VERSION 5.8 ;
BUSBITCHARS "[]" ;
DIVIDERCHAR "/" ;
UNITS
    DATABASE MICRONS 1000 ;
END UNITS

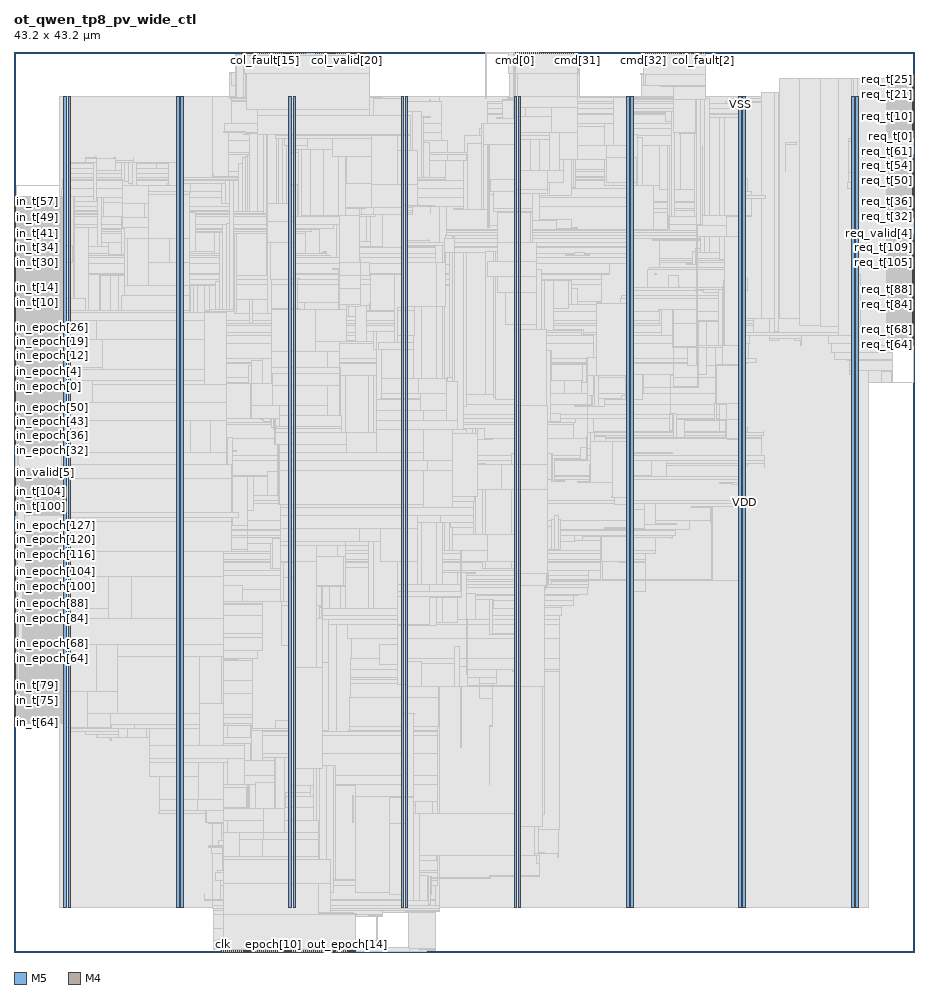
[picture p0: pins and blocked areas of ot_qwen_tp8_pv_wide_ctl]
MACRO ot_qwen_tp8_pv_wide_ctl
  FOREIGN ot_qwen_tp8_pv_wide_ctl 0 0 ;
  CLASS BLOCK ;
  SIZE 43.2 BY 43.2 ;
  PIN busy
    DIRECTION OUTPUT ;
    USE SIGNAL ;
    PORT
      LAYER M5 ;
        RECT  9.936 0 9.96 0.084 ;
    END
  END busy
  PIN clk
    DIRECTION INPUT ;
    USE SIGNAL ;
    PORT
      LAYER M5 ;
        RECT  10.032 0 10.056 0.084 ;
    END
  END clk
  PIN cmd[0]
    DIRECTION OUTPUT ;
    USE SIGNAL ;
    PORT
      LAYER M5 ;
        RECT  24.048 43.116 24.072 43.2 ;
    END
  END cmd[0]
  PIN cmd[10]
    DIRECTION OUTPUT ;
    USE SIGNAL ;
    PORT
      LAYER M5 ;
        RECT  25.008 43.116 25.032 43.2 ;
    END
  END cmd[10]
  PIN cmd[11]
    DIRECTION OUTPUT ;
    USE SIGNAL ;
    PORT
      LAYER M5 ;
        RECT  25.104 43.116 25.128 43.2 ;
    END
  END cmd[11]
  PIN cmd[12]
    DIRECTION OUTPUT ;
    USE SIGNAL ;
    PORT
      LAYER M5 ;
        RECT  25.2 43.116 25.224 43.2 ;
    END
  END cmd[12]
  PIN cmd[13]
    DIRECTION OUTPUT ;
    USE SIGNAL ;
    PORT
      LAYER M5 ;
        RECT  25.296 43.116 25.32 43.2 ;
    END
  END cmd[13]
  PIN cmd[14]
    DIRECTION OUTPUT ;
    USE SIGNAL ;
    PORT
      LAYER M5 ;
        RECT  25.392 43.116 25.416 43.2 ;
    END
  END cmd[14]
  PIN cmd[15]
    DIRECTION OUTPUT ;
    USE SIGNAL ;
    PORT
      LAYER M5 ;
        RECT  25.488 43.116 25.512 43.2 ;
    END
  END cmd[15]
  PIN cmd[16]
    DIRECTION OUTPUT ;
    USE SIGNAL ;
    PORT
      LAYER M5 ;
        RECT  25.584 43.116 25.608 43.2 ;
    END
  END cmd[16]
  PIN cmd[17]
    DIRECTION OUTPUT ;
    USE SIGNAL ;
    PORT
      LAYER M5 ;
        RECT  25.68 43.116 25.704 43.2 ;
    END
  END cmd[17]
  PIN cmd[18]
    DIRECTION OUTPUT ;
    USE SIGNAL ;
    PORT
      LAYER M5 ;
        RECT  25.776 43.116 25.8 43.2 ;
    END
  END cmd[18]
  PIN cmd[19]
    DIRECTION OUTPUT ;
    USE SIGNAL ;
    PORT
      LAYER M5 ;
        RECT  25.872 43.116 25.896 43.2 ;
    END
  END cmd[19]
  PIN cmd[1]
    DIRECTION OUTPUT ;
    USE SIGNAL ;
    PORT
      LAYER M5 ;
        RECT  24.144 43.116 24.168 43.2 ;
    END
  END cmd[1]
  PIN cmd[20]
    DIRECTION OUTPUT ;
    USE SIGNAL ;
    PORT
      LAYER M5 ;
        RECT  25.968 43.116 25.992 43.2 ;
    END
  END cmd[20]
  PIN cmd[21]
    DIRECTION OUTPUT ;
    USE SIGNAL ;
    PORT
      LAYER M5 ;
        RECT  26.064 43.116 26.088 43.2 ;
    END
  END cmd[21]
  PIN cmd[22]
    DIRECTION OUTPUT ;
    USE SIGNAL ;
    PORT
      LAYER M5 ;
        RECT  26.16 43.116 26.184 43.2 ;
    END
  END cmd[22]
  PIN cmd[23]
    DIRECTION OUTPUT ;
    USE SIGNAL ;
    PORT
      LAYER M5 ;
        RECT  26.256 43.116 26.28 43.2 ;
    END
  END cmd[23]
  PIN cmd[24]
    DIRECTION OUTPUT ;
    USE SIGNAL ;
    PORT
      LAYER M5 ;
        RECT  26.352 43.116 26.376 43.2 ;
    END
  END cmd[24]
  PIN cmd[25]
    DIRECTION OUTPUT ;
    USE SIGNAL ;
    PORT
      LAYER M5 ;
        RECT  26.448 43.116 26.472 43.2 ;
    END
  END cmd[25]
  PIN cmd[26]
    DIRECTION OUTPUT ;
    USE SIGNAL ;
    PORT
      LAYER M5 ;
        RECT  26.544 43.116 26.568 43.2 ;
    END
  END cmd[26]
  PIN cmd[27]
    DIRECTION OUTPUT ;
    USE SIGNAL ;
    PORT
      LAYER M5 ;
        RECT  26.64 43.116 26.664 43.2 ;
    END
  END cmd[27]
  PIN cmd[28]
    DIRECTION OUTPUT ;
    USE SIGNAL ;
    PORT
      LAYER M5 ;
        RECT  26.736 43.116 26.76 43.2 ;
    END
  END cmd[28]
  PIN cmd[29]
    DIRECTION OUTPUT ;
    USE SIGNAL ;
    PORT
      LAYER M5 ;
        RECT  26.832 43.116 26.856 43.2 ;
    END
  END cmd[29]
  PIN cmd[2]
    DIRECTION OUTPUT ;
    USE SIGNAL ;
    PORT
      LAYER M5 ;
        RECT  24.24 43.116 24.264 43.2 ;
    END
  END cmd[2]
  PIN cmd[30]
    DIRECTION OUTPUT ;
    USE SIGNAL ;
    PORT
      LAYER M5 ;
        RECT  26.928 43.116 26.952 43.2 ;
    END
  END cmd[30]
  PIN cmd[31]
    DIRECTION OUTPUT ;
    USE SIGNAL ;
    PORT
      LAYER M5 ;
        RECT  27.024 43.116 27.048 43.2 ;
    END
  END cmd[31]
  PIN cmd[32]
    DIRECTION OUTPUT ;
    USE SIGNAL ;
    PORT
      LAYER M5 ;
        RECT  30.192 43.116 30.216 43.2 ;
    END
  END cmd[32]
  PIN cmd[33]
    DIRECTION OUTPUT ;
    USE SIGNAL ;
    PORT
      LAYER M5 ;
        RECT  30.288 43.116 30.312 43.2 ;
    END
  END cmd[33]
  PIN cmd[34]
    DIRECTION OUTPUT ;
    USE SIGNAL ;
    PORT
      LAYER M5 ;
        RECT  30.384 43.116 30.408 43.2 ;
    END
  END cmd[34]
  PIN cmd[35]
    DIRECTION OUTPUT ;
    USE SIGNAL ;
    PORT
      LAYER M5 ;
        RECT  30.48 43.116 30.504 43.2 ;
    END
  END cmd[35]
  PIN cmd[36]
    DIRECTION OUTPUT ;
    USE SIGNAL ;
    PORT
      LAYER M5 ;
        RECT  30.576 43.116 30.6 43.2 ;
    END
  END cmd[36]
  PIN cmd[37]
    DIRECTION OUTPUT ;
    USE SIGNAL ;
    PORT
      LAYER M5 ;
        RECT  30.672 43.116 30.696 43.2 ;
    END
  END cmd[37]
  PIN cmd[38]
    DIRECTION OUTPUT ;
    USE SIGNAL ;
    PORT
      LAYER M5 ;
        RECT  30.768 43.116 30.792 43.2 ;
    END
  END cmd[38]
  PIN cmd[39]
    DIRECTION OUTPUT ;
    USE SIGNAL ;
    PORT
      LAYER M5 ;
        RECT  30.864 43.116 30.888 43.2 ;
    END
  END cmd[39]
  PIN cmd[3]
    DIRECTION OUTPUT ;
    USE SIGNAL ;
    PORT
      LAYER M5 ;
        RECT  24.336 43.116 24.36 43.2 ;
    END
  END cmd[3]
  PIN cmd[40]
    DIRECTION OUTPUT ;
    USE SIGNAL ;
    PORT
      LAYER M5 ;
        RECT  30.96 43.116 30.984 43.2 ;
    END
  END cmd[40]
  PIN cmd[41]
    DIRECTION OUTPUT ;
    USE SIGNAL ;
    PORT
      LAYER M5 ;
        RECT  31.056 43.116 31.08 43.2 ;
    END
  END cmd[41]
  PIN cmd[42]
    DIRECTION OUTPUT ;
    USE SIGNAL ;
    PORT
      LAYER M5 ;
        RECT  31.152 43.116 31.176 43.2 ;
    END
  END cmd[42]
  PIN cmd[43]
    DIRECTION OUTPUT ;
    USE SIGNAL ;
    PORT
      LAYER M5 ;
        RECT  31.248 43.116 31.272 43.2 ;
    END
  END cmd[43]
  PIN cmd[44]
    DIRECTION OUTPUT ;
    USE SIGNAL ;
    PORT
      LAYER M5 ;
        RECT  31.344 43.116 31.368 43.2 ;
    END
  END cmd[44]
  PIN cmd[45]
    DIRECTION OUTPUT ;
    USE SIGNAL ;
    PORT
      LAYER M5 ;
        RECT  31.44 43.116 31.464 43.2 ;
    END
  END cmd[45]
  PIN cmd[46]
    DIRECTION OUTPUT ;
    USE SIGNAL ;
    PORT
      LAYER M5 ;
        RECT  31.536 43.116 31.56 43.2 ;
    END
  END cmd[46]
  PIN cmd[47]
    DIRECTION OUTPUT ;
    USE SIGNAL ;
    PORT
      LAYER M5 ;
        RECT  31.632 43.116 31.656 43.2 ;
    END
  END cmd[47]
  PIN cmd[48]
    DIRECTION OUTPUT ;
    USE SIGNAL ;
    PORT
      LAYER M5 ;
        RECT  31.728 43.116 31.752 43.2 ;
    END
  END cmd[48]
  PIN cmd[49]
    DIRECTION OUTPUT ;
    USE SIGNAL ;
    PORT
      LAYER M5 ;
        RECT  31.824 43.116 31.848 43.2 ;
    END
  END cmd[49]
  PIN cmd[4]
    DIRECTION OUTPUT ;
    USE SIGNAL ;
    PORT
      LAYER M5 ;
        RECT  24.432 43.116 24.456 43.2 ;
    END
  END cmd[4]
  PIN cmd[50]
    DIRECTION OUTPUT ;
    USE SIGNAL ;
    PORT
      LAYER M5 ;
        RECT  31.92 43.116 31.944 43.2 ;
    END
  END cmd[50]
  PIN cmd[51]
    DIRECTION OUTPUT ;
    USE SIGNAL ;
    PORT
      LAYER M5 ;
        RECT  32.016 43.116 32.04 43.2 ;
    END
  END cmd[51]
  PIN cmd[52]
    DIRECTION OUTPUT ;
    USE SIGNAL ;
    PORT
      LAYER M5 ;
        RECT  32.112 43.116 32.136 43.2 ;
    END
  END cmd[52]
  PIN cmd[53]
    DIRECTION OUTPUT ;
    USE SIGNAL ;
    PORT
      LAYER M5 ;
        RECT  32.208 43.116 32.232 43.2 ;
    END
  END cmd[53]
  PIN cmd[54]
    DIRECTION OUTPUT ;
    USE SIGNAL ;
    PORT
      LAYER M5 ;
        RECT  32.304 43.116 32.328 43.2 ;
    END
  END cmd[54]
  PIN cmd[55]
    DIRECTION OUTPUT ;
    USE SIGNAL ;
    PORT
      LAYER M5 ;
        RECT  32.4 43.116 32.424 43.2 ;
    END
  END cmd[55]
  PIN cmd[56]
    DIRECTION OUTPUT ;
    USE SIGNAL ;
    PORT
      LAYER M5 ;
        RECT  32.496 43.116 32.52 43.2 ;
    END
  END cmd[56]
  PIN cmd[57]
    DIRECTION OUTPUT ;
    USE SIGNAL ;
    PORT
      LAYER M5 ;
        RECT  32.592 43.116 32.616 43.2 ;
    END
  END cmd[57]
  PIN cmd[58]
    DIRECTION OUTPUT ;
    USE SIGNAL ;
    PORT
      LAYER M5 ;
        RECT  32.688 43.116 32.712 43.2 ;
    END
  END cmd[58]
  PIN cmd[59]
    DIRECTION OUTPUT ;
    USE SIGNAL ;
    PORT
      LAYER M5 ;
        RECT  32.784 43.116 32.808 43.2 ;
    END
  END cmd[59]
  PIN cmd[5]
    DIRECTION OUTPUT ;
    USE SIGNAL ;
    PORT
      LAYER M5 ;
        RECT  24.528 43.116 24.552 43.2 ;
    END
  END cmd[5]
  PIN cmd[6]
    DIRECTION OUTPUT ;
    USE SIGNAL ;
    PORT
      LAYER M5 ;
        RECT  24.624 43.116 24.648 43.2 ;
    END
  END cmd[6]
  PIN cmd[7]
    DIRECTION OUTPUT ;
    USE SIGNAL ;
    PORT
      LAYER M5 ;
        RECT  24.72 43.116 24.744 43.2 ;
    END
  END cmd[7]
  PIN cmd[8]
    DIRECTION OUTPUT ;
    USE SIGNAL ;
    PORT
      LAYER M5 ;
        RECT  24.816 43.116 24.84 43.2 ;
    END
  END cmd[8]
  PIN cmd[9]
    DIRECTION OUTPUT ;
    USE SIGNAL ;
    PORT
      LAYER M5 ;
        RECT  24.912 43.116 24.936 43.2 ;
    END
  END cmd[9]
  PIN col_fault[0]
    DIRECTION INPUT ;
    USE SIGNAL ;
    PORT
      LAYER M5 ;
        RECT  32.88 43.116 32.904 43.2 ;
    END
  END col_fault[0]
  PIN col_fault[10]
    DIRECTION INPUT ;
    USE SIGNAL ;
    PORT
      LAYER M5 ;
        RECT  11.568 43.116 11.592 43.2 ;
    END
  END col_fault[10]
  PIN col_fault[11]
    DIRECTION INPUT ;
    USE SIGNAL ;
    PORT
      LAYER M5 ;
        RECT  11.664 43.116 11.688 43.2 ;
    END
  END col_fault[11]
  PIN col_fault[12]
    DIRECTION INPUT ;
    USE SIGNAL ;
    PORT
      LAYER M5 ;
        RECT  11.76 43.116 11.784 43.2 ;
    END
  END col_fault[12]
  PIN col_fault[13]
    DIRECTION INPUT ;
    USE SIGNAL ;
    PORT
      LAYER M5 ;
        RECT  11.856 43.116 11.88 43.2 ;
    END
  END col_fault[13]
  PIN col_fault[14]
    DIRECTION INPUT ;
    USE SIGNAL ;
    PORT
      LAYER M5 ;
        RECT  11.952 43.116 11.976 43.2 ;
    END
  END col_fault[14]
  PIN col_fault[15]
    DIRECTION INPUT ;
    USE SIGNAL ;
    PORT
      LAYER M5 ;
        RECT  12.048 43.116 12.072 43.2 ;
    END
  END col_fault[15]
  PIN col_fault[16]
    DIRECTION INPUT ;
    USE SIGNAL ;
    PORT
      LAYER M5 ;
        RECT  12.144 43.116 12.168 43.2 ;
    END
  END col_fault[16]
  PIN col_fault[17]
    DIRECTION INPUT ;
    USE SIGNAL ;
    PORT
      LAYER M5 ;
        RECT  12.24 43.116 12.264 43.2 ;
    END
  END col_fault[17]
  PIN col_fault[18]
    DIRECTION INPUT ;
    USE SIGNAL ;
    PORT
      LAYER M5 ;
        RECT  12.336 43.116 12.36 43.2 ;
    END
  END col_fault[18]
  PIN col_fault[19]
    DIRECTION INPUT ;
    USE SIGNAL ;
    PORT
      LAYER M5 ;
        RECT  12.432 43.116 12.456 43.2 ;
    END
  END col_fault[19]
  PIN col_fault[1]
    DIRECTION INPUT ;
    USE SIGNAL ;
    PORT
      LAYER M5 ;
        RECT  32.976 43.116 33 43.2 ;
    END
  END col_fault[1]
  PIN col_fault[20]
    DIRECTION INPUT ;
    USE SIGNAL ;
    PORT
      LAYER M5 ;
        RECT  12.528 43.116 12.552 43.2 ;
    END
  END col_fault[20]
  PIN col_fault[21]
    DIRECTION INPUT ;
    USE SIGNAL ;
    PORT
      LAYER M5 ;
        RECT  12.624 43.116 12.648 43.2 ;
    END
  END col_fault[21]
  PIN col_fault[22]
    DIRECTION INPUT ;
    USE SIGNAL ;
    PORT
      LAYER M5 ;
        RECT  12.72 43.116 12.744 43.2 ;
    END
  END col_fault[22]
  PIN col_fault[23]
    DIRECTION INPUT ;
    USE SIGNAL ;
    PORT
      LAYER M5 ;
        RECT  12.816 43.116 12.84 43.2 ;
    END
  END col_fault[23]
  PIN col_fault[24]
    DIRECTION INPUT ;
    USE SIGNAL ;
    PORT
      LAYER M5 ;
        RECT  12.912 43.116 12.936 43.2 ;
    END
  END col_fault[24]
  PIN col_fault[25]
    DIRECTION INPUT ;
    USE SIGNAL ;
    PORT
      LAYER M5 ;
        RECT  13.008 43.116 13.032 43.2 ;
    END
  END col_fault[25]
  PIN col_fault[26]
    DIRECTION INPUT ;
    USE SIGNAL ;
    PORT
      LAYER M5 ;
        RECT  13.104 43.116 13.128 43.2 ;
    END
  END col_fault[26]
  PIN col_fault[27]
    DIRECTION INPUT ;
    USE SIGNAL ;
    PORT
      LAYER M5 ;
        RECT  13.2 43.116 13.224 43.2 ;
    END
  END col_fault[27]
  PIN col_fault[28]
    DIRECTION INPUT ;
    USE SIGNAL ;
    PORT
      LAYER M5 ;
        RECT  13.296 43.116 13.32 43.2 ;
    END
  END col_fault[28]
  PIN col_fault[29]
    DIRECTION INPUT ;
    USE SIGNAL ;
    PORT
      LAYER M5 ;
        RECT  13.392 43.116 13.416 43.2 ;
    END
  END col_fault[29]
  PIN col_fault[2]
    DIRECTION INPUT ;
    USE SIGNAL ;
    PORT
      LAYER M5 ;
        RECT  33.072 43.116 33.096 43.2 ;
    END
  END col_fault[2]
  PIN col_fault[30]
    DIRECTION INPUT ;
    USE SIGNAL ;
    PORT
      LAYER M5 ;
        RECT  13.488 43.116 13.512 43.2 ;
    END
  END col_fault[30]
  PIN col_fault[31]
    DIRECTION INPUT ;
    USE SIGNAL ;
    PORT
      LAYER M5 ;
        RECT  13.584 43.116 13.608 43.2 ;
    END
  END col_fault[31]
  PIN col_fault[3]
    DIRECTION INPUT ;
    USE SIGNAL ;
    PORT
      LAYER M5 ;
        RECT  33.168 43.116 33.192 43.2 ;
    END
  END col_fault[3]
  PIN col_fault[4]
    DIRECTION INPUT ;
    USE SIGNAL ;
    PORT
      LAYER M5 ;
        RECT  10.992 43.116 11.016 43.2 ;
    END
  END col_fault[4]
  PIN col_fault[5]
    DIRECTION INPUT ;
    USE SIGNAL ;
    PORT
      LAYER M5 ;
        RECT  11.088 43.116 11.112 43.2 ;
    END
  END col_fault[5]
  PIN col_fault[6]
    DIRECTION INPUT ;
    USE SIGNAL ;
    PORT
      LAYER M5 ;
        RECT  11.184 43.116 11.208 43.2 ;
    END
  END col_fault[6]
  PIN col_fault[7]
    DIRECTION INPUT ;
    USE SIGNAL ;
    PORT
      LAYER M5 ;
        RECT  11.28 43.116 11.304 43.2 ;
    END
  END col_fault[7]
  PIN col_fault[8]
    DIRECTION INPUT ;
    USE SIGNAL ;
    PORT
      LAYER M5 ;
        RECT  11.376 43.116 11.4 43.2 ;
    END
  END col_fault[8]
  PIN col_fault[9]
    DIRECTION INPUT ;
    USE SIGNAL ;
    PORT
      LAYER M5 ;
        RECT  11.472 43.116 11.496 43.2 ;
    END
  END col_fault[9]
  PIN col_valid[0]
    DIRECTION INPUT ;
    USE SIGNAL ;
    PORT
      LAYER M5 ;
        RECT  13.68 43.116 13.704 43.2 ;
    END
  END col_valid[0]
  PIN col_valid[10]
    DIRECTION INPUT ;
    USE SIGNAL ;
    PORT
      LAYER M5 ;
        RECT  15.024 43.116 15.048 43.2 ;
    END
  END col_valid[10]
  PIN col_valid[11]
    DIRECTION INPUT ;
    USE SIGNAL ;
    PORT
      LAYER M5 ;
        RECT  15.12 43.116 15.144 43.2 ;
    END
  END col_valid[11]
  PIN col_valid[12]
    DIRECTION INPUT ;
    USE SIGNAL ;
    PORT
      LAYER M5 ;
        RECT  15.216 43.116 15.24 43.2 ;
    END
  END col_valid[12]
  PIN col_valid[13]
    DIRECTION INPUT ;
    USE SIGNAL ;
    PORT
      LAYER M5 ;
        RECT  15.312 43.116 15.336 43.2 ;
    END
  END col_valid[13]
  PIN col_valid[14]
    DIRECTION INPUT ;
    USE SIGNAL ;
    PORT
      LAYER M5 ;
        RECT  15.408 43.116 15.432 43.2 ;
    END
  END col_valid[14]
  PIN col_valid[15]
    DIRECTION INPUT ;
    USE SIGNAL ;
    PORT
      LAYER M5 ;
        RECT  15.504 43.116 15.528 43.2 ;
    END
  END col_valid[15]
  PIN col_valid[16]
    DIRECTION INPUT ;
    USE SIGNAL ;
    PORT
      LAYER M5 ;
        RECT  15.6 43.116 15.624 43.2 ;
    END
  END col_valid[16]
  PIN col_valid[17]
    DIRECTION INPUT ;
    USE SIGNAL ;
    PORT
      LAYER M5 ;
        RECT  15.696 43.116 15.72 43.2 ;
    END
  END col_valid[17]
  PIN col_valid[18]
    DIRECTION INPUT ;
    USE SIGNAL ;
    PORT
      LAYER M5 ;
        RECT  15.792 43.116 15.816 43.2 ;
    END
  END col_valid[18]
  PIN col_valid[19]
    DIRECTION INPUT ;
    USE SIGNAL ;
    PORT
      LAYER M5 ;
        RECT  15.888 43.116 15.912 43.2 ;
    END
  END col_valid[19]
  PIN col_valid[1]
    DIRECTION INPUT ;
    USE SIGNAL ;
    PORT
      LAYER M5 ;
        RECT  13.776 43.116 13.8 43.2 ;
    END
  END col_valid[1]
  PIN col_valid[20]
    DIRECTION INPUT ;
    USE SIGNAL ;
    PORT
      LAYER M5 ;
        RECT  15.984 43.116 16.008 43.2 ;
    END
  END col_valid[20]
  PIN col_valid[21]
    DIRECTION INPUT ;
    USE SIGNAL ;
    PORT
      LAYER M5 ;
        RECT  16.08 43.116 16.104 43.2 ;
    END
  END col_valid[21]
  PIN col_valid[22]
    DIRECTION INPUT ;
    USE SIGNAL ;
    PORT
      LAYER M5 ;
        RECT  16.176 43.116 16.2 43.2 ;
    END
  END col_valid[22]
  PIN col_valid[23]
    DIRECTION INPUT ;
    USE SIGNAL ;
    PORT
      LAYER M5 ;
        RECT  16.272 43.116 16.296 43.2 ;
    END
  END col_valid[23]
  PIN col_valid[24]
    DIRECTION INPUT ;
    USE SIGNAL ;
    PORT
      LAYER M5 ;
        RECT  16.368 43.116 16.392 43.2 ;
    END
  END col_valid[24]
  PIN col_valid[25]
    DIRECTION INPUT ;
    USE SIGNAL ;
    PORT
      LAYER M5 ;
        RECT  16.464 43.116 16.488 43.2 ;
    END
  END col_valid[25]
  PIN col_valid[26]
    DIRECTION INPUT ;
    USE SIGNAL ;
    PORT
      LAYER M5 ;
        RECT  16.56 43.116 16.584 43.2 ;
    END
  END col_valid[26]
  PIN col_valid[27]
    DIRECTION INPUT ;
    USE SIGNAL ;
    PORT
      LAYER M5 ;
        RECT  16.656 43.116 16.68 43.2 ;
    END
  END col_valid[27]
  PIN col_valid[28]
    DIRECTION INPUT ;
    USE SIGNAL ;
    PORT
      LAYER M5 ;
        RECT  16.752 43.116 16.776 43.2 ;
    END
  END col_valid[28]
  PIN col_valid[29]
    DIRECTION INPUT ;
    USE SIGNAL ;
    PORT
      LAYER M5 ;
        RECT  16.848 43.116 16.872 43.2 ;
    END
  END col_valid[29]
  PIN col_valid[2]
    DIRECTION INPUT ;
    USE SIGNAL ;
    PORT
      LAYER M5 ;
        RECT  13.872 43.116 13.896 43.2 ;
    END
  END col_valid[2]
  PIN col_valid[30]
    DIRECTION INPUT ;
    USE SIGNAL ;
    PORT
      LAYER M5 ;
        RECT  16.944 43.116 16.968 43.2 ;
    END
  END col_valid[30]
  PIN col_valid[31]
    DIRECTION INPUT ;
    USE SIGNAL ;
    PORT
      LAYER M5 ;
        RECT  17.04 43.116 17.064 43.2 ;
    END
  END col_valid[31]
  PIN col_valid[3]
    DIRECTION INPUT ;
    USE SIGNAL ;
    PORT
      LAYER M5 ;
        RECT  13.968 43.116 13.992 43.2 ;
    END
  END col_valid[3]
  PIN col_valid[4]
    DIRECTION INPUT ;
    USE SIGNAL ;
    PORT
      LAYER M5 ;
        RECT  14.448 43.116 14.472 43.2 ;
    END
  END col_valid[4]
  PIN col_valid[5]
    DIRECTION INPUT ;
    USE SIGNAL ;
    PORT
      LAYER M5 ;
        RECT  14.544 43.116 14.568 43.2 ;
    END
  END col_valid[5]
  PIN col_valid[6]
    DIRECTION INPUT ;
    USE SIGNAL ;
    PORT
      LAYER M5 ;
        RECT  14.64 43.116 14.664 43.2 ;
    END
  END col_valid[6]
  PIN col_valid[7]
    DIRECTION INPUT ;
    USE SIGNAL ;
    PORT
      LAYER M5 ;
        RECT  14.736 43.116 14.76 43.2 ;
    END
  END col_valid[7]
  PIN col_valid[8]
    DIRECTION INPUT ;
    USE SIGNAL ;
    PORT
      LAYER M5 ;
        RECT  14.832 43.116 14.856 43.2 ;
    END
  END col_valid[8]
  PIN col_valid[9]
    DIRECTION INPUT ;
    USE SIGNAL ;
    PORT
      LAYER M5 ;
        RECT  14.928 43.116 14.952 43.2 ;
    END
  END col_valid[9]
  PIN context_len[0]
    DIRECTION INPUT ;
    USE SIGNAL ;
    PORT
      LAYER M5 ;
        RECT  10.128 0 10.152 0.084 ;
    END
  END context_len[0]
  PIN context_len[10]
    DIRECTION INPUT ;
    USE SIGNAL ;
    PORT
      LAYER M5 ;
        RECT  11.088 0 11.112 0.084 ;
    END
  END context_len[10]
  PIN context_len[11]
    DIRECTION INPUT ;
    USE SIGNAL ;
    PORT
      LAYER M5 ;
        RECT  11.184 0 11.208 0.084 ;
    END
  END context_len[11]
  PIN context_len[12]
    DIRECTION INPUT ;
    USE SIGNAL ;
    PORT
      LAYER M5 ;
        RECT  11.28 0 11.304 0.084 ;
    END
  END context_len[12]
  PIN context_len[13]
    DIRECTION INPUT ;
    USE SIGNAL ;
    PORT
      LAYER M5 ;
        RECT  11.376 0 11.4 0.084 ;
    END
  END context_len[13]
  PIN context_len[1]
    DIRECTION INPUT ;
    USE SIGNAL ;
    PORT
      LAYER M5 ;
        RECT  10.224 0 10.248 0.084 ;
    END
  END context_len[1]
  PIN context_len[2]
    DIRECTION INPUT ;
    USE SIGNAL ;
    PORT
      LAYER M5 ;
        RECT  10.32 0 10.344 0.084 ;
    END
  END context_len[2]
  PIN context_len[3]
    DIRECTION INPUT ;
    USE SIGNAL ;
    PORT
      LAYER M5 ;
        RECT  10.416 0 10.44 0.084 ;
    END
  END context_len[3]
  PIN context_len[4]
    DIRECTION INPUT ;
    USE SIGNAL ;
    PORT
      LAYER M5 ;
        RECT  10.512 0 10.536 0.084 ;
    END
  END context_len[4]
  PIN context_len[5]
    DIRECTION INPUT ;
    USE SIGNAL ;
    PORT
      LAYER M5 ;
        RECT  10.608 0 10.632 0.084 ;
    END
  END context_len[5]
  PIN context_len[6]
    DIRECTION INPUT ;
    USE SIGNAL ;
    PORT
      LAYER M5 ;
        RECT  10.704 0 10.728 0.084 ;
    END
  END context_len[6]
  PIN context_len[7]
    DIRECTION INPUT ;
    USE SIGNAL ;
    PORT
      LAYER M5 ;
        RECT  10.8 0 10.824 0.084 ;
    END
  END context_len[7]
  PIN context_len[8]
    DIRECTION INPUT ;
    USE SIGNAL ;
    PORT
      LAYER M5 ;
        RECT  10.896 0 10.92 0.084 ;
    END
  END context_len[8]
  PIN context_len[9]
    DIRECTION INPUT ;
    USE SIGNAL ;
    PORT
      LAYER M5 ;
        RECT  10.992 0 11.016 0.084 ;
    END
  END context_len[9]
  PIN epoch[0]
    DIRECTION INPUT ;
    USE SIGNAL ;
    PORT
      LAYER M5 ;
        RECT  11.472 0 11.496 0.084 ;
    END
  END epoch[0]
  PIN epoch[10]
    DIRECTION INPUT ;
    USE SIGNAL ;
    PORT
      LAYER M5 ;
        RECT  12.432 0 12.456 0.084 ;
    END
  END epoch[10]
  PIN epoch[11]
    DIRECTION INPUT ;
    USE SIGNAL ;
    PORT
      LAYER M5 ;
        RECT  12.528 0 12.552 0.084 ;
    END
  END epoch[11]
  PIN epoch[12]
    DIRECTION INPUT ;
    USE SIGNAL ;
    PORT
      LAYER M5 ;
        RECT  12.624 0 12.648 0.084 ;
    END
  END epoch[12]
  PIN epoch[13]
    DIRECTION INPUT ;
    USE SIGNAL ;
    PORT
      LAYER M5 ;
        RECT  12.72 0 12.744 0.084 ;
    END
  END epoch[13]
  PIN epoch[14]
    DIRECTION INPUT ;
    USE SIGNAL ;
    PORT
      LAYER M5 ;
        RECT  12.816 0 12.84 0.084 ;
    END
  END epoch[14]
  PIN epoch[15]
    DIRECTION INPUT ;
    USE SIGNAL ;
    PORT
      LAYER M5 ;
        RECT  12.912 0 12.936 0.084 ;
    END
  END epoch[15]
  PIN epoch[1]
    DIRECTION INPUT ;
    USE SIGNAL ;
    PORT
      LAYER M5 ;
        RECT  11.568 0 11.592 0.084 ;
    END
  END epoch[1]
  PIN epoch[2]
    DIRECTION INPUT ;
    USE SIGNAL ;
    PORT
      LAYER M5 ;
        RECT  11.664 0 11.688 0.084 ;
    END
  END epoch[2]
  PIN epoch[3]
    DIRECTION INPUT ;
    USE SIGNAL ;
    PORT
      LAYER M5 ;
        RECT  11.76 0 11.784 0.084 ;
    END
  END epoch[3]
  PIN epoch[4]
    DIRECTION INPUT ;
    USE SIGNAL ;
    PORT
      LAYER M5 ;
        RECT  11.856 0 11.88 0.084 ;
    END
  END epoch[4]
  PIN epoch[5]
    DIRECTION INPUT ;
    USE SIGNAL ;
    PORT
      LAYER M5 ;
        RECT  11.952 0 11.976 0.084 ;
    END
  END epoch[5]
  PIN epoch[6]
    DIRECTION INPUT ;
    USE SIGNAL ;
    PORT
      LAYER M5 ;
        RECT  12.048 0 12.072 0.084 ;
    END
  END epoch[6]
  PIN epoch[7]
    DIRECTION INPUT ;
    USE SIGNAL ;
    PORT
      LAYER M5 ;
        RECT  12.144 0 12.168 0.084 ;
    END
  END epoch[7]
  PIN epoch[8]
    DIRECTION INPUT ;
    USE SIGNAL ;
    PORT
      LAYER M5 ;
        RECT  12.24 0 12.264 0.084 ;
    END
  END epoch[8]
  PIN epoch[9]
    DIRECTION INPUT ;
    USE SIGNAL ;
    PORT
      LAYER M5 ;
        RECT  12.336 0 12.36 0.084 ;
    END
  END epoch[9]
  PIN fault
    DIRECTION OUTPUT ;
    USE SIGNAL ;
    PORT
      LAYER M5 ;
        RECT  13.008 0 13.032 0.084 ;
    END
  END fault
  PIN in_epoch[0]
    DIRECTION INPUT ;
    USE SIGNAL ;
    PORT
      LAYER M4 ;
        RECT  0 27.12 0.084 27.144 ;
    END
  END in_epoch[0]
  PIN in_epoch[100]
    DIRECTION INPUT ;
    USE SIGNAL ;
    PORT
      LAYER M4 ;
        RECT  0 17.52 0.084 17.544 ;
    END
  END in_epoch[100]
  PIN in_epoch[101]
    DIRECTION INPUT ;
    USE SIGNAL ;
    PORT
      LAYER M4 ;
        RECT  0 17.616 0.084 17.64 ;
    END
  END in_epoch[101]
  PIN in_epoch[102]
    DIRECTION INPUT ;
    USE SIGNAL ;
    PORT
      LAYER M4 ;
        RECT  0 17.712 0.084 17.736 ;
    END
  END in_epoch[102]
  PIN in_epoch[103]
    DIRECTION INPUT ;
    USE SIGNAL ;
    PORT
      LAYER M4 ;
        RECT  0 17.808 0.084 17.832 ;
    END
  END in_epoch[103]
  PIN in_epoch[104]
    DIRECTION INPUT ;
    USE SIGNAL ;
    PORT
      LAYER M4 ;
        RECT  0 17.904 0.084 17.928 ;
    END
  END in_epoch[104]
  PIN in_epoch[105]
    DIRECTION INPUT ;
    USE SIGNAL ;
    PORT
      LAYER M4 ;
        RECT  0 18 0.084 18.024 ;
    END
  END in_epoch[105]
  PIN in_epoch[106]
    DIRECTION INPUT ;
    USE SIGNAL ;
    PORT
      LAYER M4 ;
        RECT  0 18.096 0.084 18.12 ;
    END
  END in_epoch[106]
  PIN in_epoch[107]
    DIRECTION INPUT ;
    USE SIGNAL ;
    PORT
      LAYER M4 ;
        RECT  0 18.192 0.084 18.216 ;
    END
  END in_epoch[107]
  PIN in_epoch[108]
    DIRECTION INPUT ;
    USE SIGNAL ;
    PORT
      LAYER M4 ;
        RECT  0 18.288 0.084 18.312 ;
    END
  END in_epoch[108]
  PIN in_epoch[109]
    DIRECTION INPUT ;
    USE SIGNAL ;
    PORT
      LAYER M4 ;
        RECT  0 18.384 0.084 18.408 ;
    END
  END in_epoch[109]
  PIN in_epoch[10]
    DIRECTION INPUT ;
    USE SIGNAL ;
    PORT
      LAYER M4 ;
        RECT  0 28.08 0.084 28.104 ;
    END
  END in_epoch[10]
  PIN in_epoch[110]
    DIRECTION INPUT ;
    USE SIGNAL ;
    PORT
      LAYER M4 ;
        RECT  0 18.48 0.084 18.504 ;
    END
  END in_epoch[110]
  PIN in_epoch[111]
    DIRECTION INPUT ;
    USE SIGNAL ;
    PORT
      LAYER M4 ;
        RECT  0 18.576 0.084 18.6 ;
    END
  END in_epoch[111]
  PIN in_epoch[112]
    DIRECTION INPUT ;
    USE SIGNAL ;
    PORT
      LAYER M4 ;
        RECT  0 18.672 0.084 18.696 ;
    END
  END in_epoch[112]
  PIN in_epoch[113]
    DIRECTION INPUT ;
    USE SIGNAL ;
    PORT
      LAYER M4 ;
        RECT  0 18.768 0.084 18.792 ;
    END
  END in_epoch[113]
  PIN in_epoch[114]
    DIRECTION INPUT ;
    USE SIGNAL ;
    PORT
      LAYER M4 ;
        RECT  0 18.864 0.084 18.888 ;
    END
  END in_epoch[114]
  PIN in_epoch[115]
    DIRECTION INPUT ;
    USE SIGNAL ;
    PORT
      LAYER M4 ;
        RECT  0 18.96 0.084 18.984 ;
    END
  END in_epoch[115]
  PIN in_epoch[116]
    DIRECTION INPUT ;
    USE SIGNAL ;
    PORT
      LAYER M4 ;
        RECT  0 19.056 0.084 19.08 ;
    END
  END in_epoch[116]
  PIN in_epoch[117]
    DIRECTION INPUT ;
    USE SIGNAL ;
    PORT
      LAYER M4 ;
        RECT  0 19.152 0.084 19.176 ;
    END
  END in_epoch[117]
  PIN in_epoch[118]
    DIRECTION INPUT ;
    USE SIGNAL ;
    PORT
      LAYER M4 ;
        RECT  0 19.248 0.084 19.272 ;
    END
  END in_epoch[118]
  PIN in_epoch[119]
    DIRECTION INPUT ;
    USE SIGNAL ;
    PORT
      LAYER M4 ;
        RECT  0 19.344 0.084 19.368 ;
    END
  END in_epoch[119]
  PIN in_epoch[11]
    DIRECTION INPUT ;
    USE SIGNAL ;
    PORT
      LAYER M4 ;
        RECT  0 28.176 0.084 28.2 ;
    END
  END in_epoch[11]
  PIN in_epoch[120]
    DIRECTION INPUT ;
    USE SIGNAL ;
    PORT
      LAYER M4 ;
        RECT  0 19.44 0.084 19.464 ;
    END
  END in_epoch[120]
  PIN in_epoch[121]
    DIRECTION INPUT ;
    USE SIGNAL ;
    PORT
      LAYER M4 ;
        RECT  0 19.536 0.084 19.56 ;
    END
  END in_epoch[121]
  PIN in_epoch[122]
    DIRECTION INPUT ;
    USE SIGNAL ;
    PORT
      LAYER M4 ;
        RECT  0 19.632 0.084 19.656 ;
    END
  END in_epoch[122]
  PIN in_epoch[123]
    DIRECTION INPUT ;
    USE SIGNAL ;
    PORT
      LAYER M4 ;
        RECT  0 19.728 0.084 19.752 ;
    END
  END in_epoch[123]
  PIN in_epoch[124]
    DIRECTION INPUT ;
    USE SIGNAL ;
    PORT
      LAYER M4 ;
        RECT  0 19.824 0.084 19.848 ;
    END
  END in_epoch[124]
  PIN in_epoch[125]
    DIRECTION INPUT ;
    USE SIGNAL ;
    PORT
      LAYER M4 ;
        RECT  0 19.92 0.084 19.944 ;
    END
  END in_epoch[125]
  PIN in_epoch[126]
    DIRECTION INPUT ;
    USE SIGNAL ;
    PORT
      LAYER M4 ;
        RECT  0 20.016 0.084 20.04 ;
    END
  END in_epoch[126]
  PIN in_epoch[127]
    DIRECTION INPUT ;
    USE SIGNAL ;
    PORT
      LAYER M4 ;
        RECT  0 20.112 0.084 20.136 ;
    END
  END in_epoch[127]
  PIN in_epoch[12]
    DIRECTION INPUT ;
    USE SIGNAL ;
    PORT
      LAYER M4 ;
        RECT  0 28.272 0.084 28.296 ;
    END
  END in_epoch[12]
  PIN in_epoch[13]
    DIRECTION INPUT ;
    USE SIGNAL ;
    PORT
      LAYER M4 ;
        RECT  0 28.368 0.084 28.392 ;
    END
  END in_epoch[13]
  PIN in_epoch[14]
    DIRECTION INPUT ;
    USE SIGNAL ;
    PORT
      LAYER M4 ;
        RECT  0 28.464 0.084 28.488 ;
    END
  END in_epoch[14]
  PIN in_epoch[15]
    DIRECTION INPUT ;
    USE SIGNAL ;
    PORT
      LAYER M4 ;
        RECT  0 28.56 0.084 28.584 ;
    END
  END in_epoch[15]
  PIN in_epoch[16]
    DIRECTION INPUT ;
    USE SIGNAL ;
    PORT
      LAYER M4 ;
        RECT  0 28.656 0.084 28.68 ;
    END
  END in_epoch[16]
  PIN in_epoch[17]
    DIRECTION INPUT ;
    USE SIGNAL ;
    PORT
      LAYER M4 ;
        RECT  0 28.752 0.084 28.776 ;
    END
  END in_epoch[17]
  PIN in_epoch[18]
    DIRECTION INPUT ;
    USE SIGNAL ;
    PORT
      LAYER M4 ;
        RECT  0 28.848 0.084 28.872 ;
    END
  END in_epoch[18]
  PIN in_epoch[19]
    DIRECTION INPUT ;
    USE SIGNAL ;
    PORT
      LAYER M4 ;
        RECT  0 28.944 0.084 28.968 ;
    END
  END in_epoch[19]
  PIN in_epoch[1]
    DIRECTION INPUT ;
    USE SIGNAL ;
    PORT
      LAYER M4 ;
        RECT  0 27.216 0.084 27.24 ;
    END
  END in_epoch[1]
  PIN in_epoch[20]
    DIRECTION INPUT ;
    USE SIGNAL ;
    PORT
      LAYER M4 ;
        RECT  0 29.04 0.084 29.064 ;
    END
  END in_epoch[20]
  PIN in_epoch[21]
    DIRECTION INPUT ;
    USE SIGNAL ;
    PORT
      LAYER M4 ;
        RECT  0 29.136 0.084 29.16 ;
    END
  END in_epoch[21]
  PIN in_epoch[22]
    DIRECTION INPUT ;
    USE SIGNAL ;
    PORT
      LAYER M4 ;
        RECT  0 29.232 0.084 29.256 ;
    END
  END in_epoch[22]
  PIN in_epoch[23]
    DIRECTION INPUT ;
    USE SIGNAL ;
    PORT
      LAYER M4 ;
        RECT  0 29.328 0.084 29.352 ;
    END
  END in_epoch[23]
  PIN in_epoch[24]
    DIRECTION INPUT ;
    USE SIGNAL ;
    PORT
      LAYER M4 ;
        RECT  0 29.424 0.084 29.448 ;
    END
  END in_epoch[24]
  PIN in_epoch[25]
    DIRECTION INPUT ;
    USE SIGNAL ;
    PORT
      LAYER M4 ;
        RECT  0 29.52 0.084 29.544 ;
    END
  END in_epoch[25]
  PIN in_epoch[26]
    DIRECTION INPUT ;
    USE SIGNAL ;
    PORT
      LAYER M4 ;
        RECT  0 29.616 0.084 29.64 ;
    END
  END in_epoch[26]
  PIN in_epoch[27]
    DIRECTION INPUT ;
    USE SIGNAL ;
    PORT
      LAYER M4 ;
        RECT  0 29.712 0.084 29.736 ;
    END
  END in_epoch[27]
  PIN in_epoch[28]
    DIRECTION INPUT ;
    USE SIGNAL ;
    PORT
      LAYER M4 ;
        RECT  0 29.808 0.084 29.832 ;
    END
  END in_epoch[28]
  PIN in_epoch[29]
    DIRECTION INPUT ;
    USE SIGNAL ;
    PORT
      LAYER M4 ;
        RECT  0 29.904 0.084 29.928 ;
    END
  END in_epoch[29]
  PIN in_epoch[2]
    DIRECTION INPUT ;
    USE SIGNAL ;
    PORT
      LAYER M4 ;
        RECT  0 27.312 0.084 27.336 ;
    END
  END in_epoch[2]
  PIN in_epoch[30]
    DIRECTION INPUT ;
    USE SIGNAL ;
    PORT
      LAYER M4 ;
        RECT  0 30 0.084 30.024 ;
    END
  END in_epoch[30]
  PIN in_epoch[31]
    DIRECTION INPUT ;
    USE SIGNAL ;
    PORT
      LAYER M4 ;
        RECT  0 30.096 0.084 30.12 ;
    END
  END in_epoch[31]
  PIN in_epoch[32]
    DIRECTION INPUT ;
    USE SIGNAL ;
    PORT
      LAYER M4 ;
        RECT  0 24.048 0.084 24.072 ;
    END
  END in_epoch[32]
  PIN in_epoch[33]
    DIRECTION INPUT ;
    USE SIGNAL ;
    PORT
      LAYER M4 ;
        RECT  0 24.144 0.084 24.168 ;
    END
  END in_epoch[33]
  PIN in_epoch[34]
    DIRECTION INPUT ;
    USE SIGNAL ;
    PORT
      LAYER M4 ;
        RECT  0 24.24 0.084 24.264 ;
    END
  END in_epoch[34]
  PIN in_epoch[35]
    DIRECTION INPUT ;
    USE SIGNAL ;
    PORT
      LAYER M4 ;
        RECT  0 24.336 0.084 24.36 ;
    END
  END in_epoch[35]
  PIN in_epoch[36]
    DIRECTION INPUT ;
    USE SIGNAL ;
    PORT
      LAYER M4 ;
        RECT  0 24.432 0.084 24.456 ;
    END
  END in_epoch[36]
  PIN in_epoch[37]
    DIRECTION INPUT ;
    USE SIGNAL ;
    PORT
      LAYER M4 ;
        RECT  0 24.528 0.084 24.552 ;
    END
  END in_epoch[37]
  PIN in_epoch[38]
    DIRECTION INPUT ;
    USE SIGNAL ;
    PORT
      LAYER M4 ;
        RECT  0 24.624 0.084 24.648 ;
    END
  END in_epoch[38]
  PIN in_epoch[39]
    DIRECTION INPUT ;
    USE SIGNAL ;
    PORT
      LAYER M4 ;
        RECT  0 24.72 0.084 24.744 ;
    END
  END in_epoch[39]
  PIN in_epoch[3]
    DIRECTION INPUT ;
    USE SIGNAL ;
    PORT
      LAYER M4 ;
        RECT  0 27.408 0.084 27.432 ;
    END
  END in_epoch[3]
  PIN in_epoch[40]
    DIRECTION INPUT ;
    USE SIGNAL ;
    PORT
      LAYER M4 ;
        RECT  0 24.816 0.084 24.84 ;
    END
  END in_epoch[40]
  PIN in_epoch[41]
    DIRECTION INPUT ;
    USE SIGNAL ;
    PORT
      LAYER M4 ;
        RECT  0 24.912 0.084 24.936 ;
    END
  END in_epoch[41]
  PIN in_epoch[42]
    DIRECTION INPUT ;
    USE SIGNAL ;
    PORT
      LAYER M4 ;
        RECT  0 25.008 0.084 25.032 ;
    END
  END in_epoch[42]
  PIN in_epoch[43]
    DIRECTION INPUT ;
    USE SIGNAL ;
    PORT
      LAYER M4 ;
        RECT  0 25.104 0.084 25.128 ;
    END
  END in_epoch[43]
  PIN in_epoch[44]
    DIRECTION INPUT ;
    USE SIGNAL ;
    PORT
      LAYER M4 ;
        RECT  0 25.2 0.084 25.224 ;
    END
  END in_epoch[44]
  PIN in_epoch[45]
    DIRECTION INPUT ;
    USE SIGNAL ;
    PORT
      LAYER M4 ;
        RECT  0 25.296 0.084 25.32 ;
    END
  END in_epoch[45]
  PIN in_epoch[46]
    DIRECTION INPUT ;
    USE SIGNAL ;
    PORT
      LAYER M4 ;
        RECT  0 25.392 0.084 25.416 ;
    END
  END in_epoch[46]
  PIN in_epoch[47]
    DIRECTION INPUT ;
    USE SIGNAL ;
    PORT
      LAYER M4 ;
        RECT  0 25.488 0.084 25.512 ;
    END
  END in_epoch[47]
  PIN in_epoch[48]
    DIRECTION INPUT ;
    USE SIGNAL ;
    PORT
      LAYER M4 ;
        RECT  0 25.584 0.084 25.608 ;
    END
  END in_epoch[48]
  PIN in_epoch[49]
    DIRECTION INPUT ;
    USE SIGNAL ;
    PORT
      LAYER M4 ;
        RECT  0 25.68 0.084 25.704 ;
    END
  END in_epoch[49]
  PIN in_epoch[4]
    DIRECTION INPUT ;
    USE SIGNAL ;
    PORT
      LAYER M4 ;
        RECT  0 27.504 0.084 27.528 ;
    END
  END in_epoch[4]
  PIN in_epoch[50]
    DIRECTION INPUT ;
    USE SIGNAL ;
    PORT
      LAYER M4 ;
        RECT  0 25.776 0.084 25.8 ;
    END
  END in_epoch[50]
  PIN in_epoch[51]
    DIRECTION INPUT ;
    USE SIGNAL ;
    PORT
      LAYER M4 ;
        RECT  0 25.872 0.084 25.896 ;
    END
  END in_epoch[51]
  PIN in_epoch[52]
    DIRECTION INPUT ;
    USE SIGNAL ;
    PORT
      LAYER M4 ;
        RECT  0 25.968 0.084 25.992 ;
    END
  END in_epoch[52]
  PIN in_epoch[53]
    DIRECTION INPUT ;
    USE SIGNAL ;
    PORT
      LAYER M4 ;
        RECT  0 26.064 0.084 26.088 ;
    END
  END in_epoch[53]
  PIN in_epoch[54]
    DIRECTION INPUT ;
    USE SIGNAL ;
    PORT
      LAYER M4 ;
        RECT  0 26.16 0.084 26.184 ;
    END
  END in_epoch[54]
  PIN in_epoch[55]
    DIRECTION INPUT ;
    USE SIGNAL ;
    PORT
      LAYER M4 ;
        RECT  0 26.256 0.084 26.28 ;
    END
  END in_epoch[55]
  PIN in_epoch[56]
    DIRECTION INPUT ;
    USE SIGNAL ;
    PORT
      LAYER M4 ;
        RECT  0 26.352 0.084 26.376 ;
    END
  END in_epoch[56]
  PIN in_epoch[57]
    DIRECTION INPUT ;
    USE SIGNAL ;
    PORT
      LAYER M4 ;
        RECT  0 26.448 0.084 26.472 ;
    END
  END in_epoch[57]
  PIN in_epoch[58]
    DIRECTION INPUT ;
    USE SIGNAL ;
    PORT
      LAYER M4 ;
        RECT  0 26.544 0.084 26.568 ;
    END
  END in_epoch[58]
  PIN in_epoch[59]
    DIRECTION INPUT ;
    USE SIGNAL ;
    PORT
      LAYER M4 ;
        RECT  0 26.64 0.084 26.664 ;
    END
  END in_epoch[59]
  PIN in_epoch[5]
    DIRECTION INPUT ;
    USE SIGNAL ;
    PORT
      LAYER M4 ;
        RECT  0 27.6 0.084 27.624 ;
    END
  END in_epoch[5]
  PIN in_epoch[60]
    DIRECTION INPUT ;
    USE SIGNAL ;
    PORT
      LAYER M4 ;
        RECT  0 26.736 0.084 26.76 ;
    END
  END in_epoch[60]
  PIN in_epoch[61]
    DIRECTION INPUT ;
    USE SIGNAL ;
    PORT
      LAYER M4 ;
        RECT  0 26.832 0.084 26.856 ;
    END
  END in_epoch[61]
  PIN in_epoch[62]
    DIRECTION INPUT ;
    USE SIGNAL ;
    PORT
      LAYER M4 ;
        RECT  0 26.928 0.084 26.952 ;
    END
  END in_epoch[62]
  PIN in_epoch[63]
    DIRECTION INPUT ;
    USE SIGNAL ;
    PORT
      LAYER M4 ;
        RECT  0 27.024 0.084 27.048 ;
    END
  END in_epoch[63]
  PIN in_epoch[64]
    DIRECTION INPUT ;
    USE SIGNAL ;
    PORT
      LAYER M4 ;
        RECT  0 14.064 0.084 14.088 ;
    END
  END in_epoch[64]
  PIN in_epoch[65]
    DIRECTION INPUT ;
    USE SIGNAL ;
    PORT
      LAYER M4 ;
        RECT  0 14.16 0.084 14.184 ;
    END
  END in_epoch[65]
  PIN in_epoch[66]
    DIRECTION INPUT ;
    USE SIGNAL ;
    PORT
      LAYER M4 ;
        RECT  0 14.256 0.084 14.28 ;
    END
  END in_epoch[66]
  PIN in_epoch[67]
    DIRECTION INPUT ;
    USE SIGNAL ;
    PORT
      LAYER M4 ;
        RECT  0 14.352 0.084 14.376 ;
    END
  END in_epoch[67]
  PIN in_epoch[68]
    DIRECTION INPUT ;
    USE SIGNAL ;
    PORT
      LAYER M4 ;
        RECT  0 14.448 0.084 14.472 ;
    END
  END in_epoch[68]
  PIN in_epoch[69]
    DIRECTION INPUT ;
    USE SIGNAL ;
    PORT
      LAYER M4 ;
        RECT  0 14.544 0.084 14.568 ;
    END
  END in_epoch[69]
  PIN in_epoch[6]
    DIRECTION INPUT ;
    USE SIGNAL ;
    PORT
      LAYER M4 ;
        RECT  0 27.696 0.084 27.72 ;
    END
  END in_epoch[6]
  PIN in_epoch[70]
    DIRECTION INPUT ;
    USE SIGNAL ;
    PORT
      LAYER M4 ;
        RECT  0 14.64 0.084 14.664 ;
    END
  END in_epoch[70]
  PIN in_epoch[71]
    DIRECTION INPUT ;
    USE SIGNAL ;
    PORT
      LAYER M4 ;
        RECT  0 14.736 0.084 14.76 ;
    END
  END in_epoch[71]
  PIN in_epoch[72]
    DIRECTION INPUT ;
    USE SIGNAL ;
    PORT
      LAYER M4 ;
        RECT  0 14.832 0.084 14.856 ;
    END
  END in_epoch[72]
  PIN in_epoch[73]
    DIRECTION INPUT ;
    USE SIGNAL ;
    PORT
      LAYER M4 ;
        RECT  0 14.928 0.084 14.952 ;
    END
  END in_epoch[73]
  PIN in_epoch[74]
    DIRECTION INPUT ;
    USE SIGNAL ;
    PORT
      LAYER M4 ;
        RECT  0 15.024 0.084 15.048 ;
    END
  END in_epoch[74]
  PIN in_epoch[75]
    DIRECTION INPUT ;
    USE SIGNAL ;
    PORT
      LAYER M4 ;
        RECT  0 15.12 0.084 15.144 ;
    END
  END in_epoch[75]
  PIN in_epoch[76]
    DIRECTION INPUT ;
    USE SIGNAL ;
    PORT
      LAYER M4 ;
        RECT  0 15.216 0.084 15.24 ;
    END
  END in_epoch[76]
  PIN in_epoch[77]
    DIRECTION INPUT ;
    USE SIGNAL ;
    PORT
      LAYER M4 ;
        RECT  0 15.312 0.084 15.336 ;
    END
  END in_epoch[77]
  PIN in_epoch[78]
    DIRECTION INPUT ;
    USE SIGNAL ;
    PORT
      LAYER M4 ;
        RECT  0 15.408 0.084 15.432 ;
    END
  END in_epoch[78]
  PIN in_epoch[79]
    DIRECTION INPUT ;
    USE SIGNAL ;
    PORT
      LAYER M4 ;
        RECT  0 15.504 0.084 15.528 ;
    END
  END in_epoch[79]
  PIN in_epoch[7]
    DIRECTION INPUT ;
    USE SIGNAL ;
    PORT
      LAYER M4 ;
        RECT  0 27.792 0.084 27.816 ;
    END
  END in_epoch[7]
  PIN in_epoch[80]
    DIRECTION INPUT ;
    USE SIGNAL ;
    PORT
      LAYER M4 ;
        RECT  0 15.6 0.084 15.624 ;
    END
  END in_epoch[80]
  PIN in_epoch[81]
    DIRECTION INPUT ;
    USE SIGNAL ;
    PORT
      LAYER M4 ;
        RECT  0 15.696 0.084 15.72 ;
    END
  END in_epoch[81]
  PIN in_epoch[82]
    DIRECTION INPUT ;
    USE SIGNAL ;
    PORT
      LAYER M4 ;
        RECT  0 15.792 0.084 15.816 ;
    END
  END in_epoch[82]
  PIN in_epoch[83]
    DIRECTION INPUT ;
    USE SIGNAL ;
    PORT
      LAYER M4 ;
        RECT  0 15.888 0.084 15.912 ;
    END
  END in_epoch[83]
  PIN in_epoch[84]
    DIRECTION INPUT ;
    USE SIGNAL ;
    PORT
      LAYER M4 ;
        RECT  0 15.984 0.084 16.008 ;
    END
  END in_epoch[84]
  PIN in_epoch[85]
    DIRECTION INPUT ;
    USE SIGNAL ;
    PORT
      LAYER M4 ;
        RECT  0 16.08 0.084 16.104 ;
    END
  END in_epoch[85]
  PIN in_epoch[86]
    DIRECTION INPUT ;
    USE SIGNAL ;
    PORT
      LAYER M4 ;
        RECT  0 16.176 0.084 16.2 ;
    END
  END in_epoch[86]
  PIN in_epoch[87]
    DIRECTION INPUT ;
    USE SIGNAL ;
    PORT
      LAYER M4 ;
        RECT  0 16.272 0.084 16.296 ;
    END
  END in_epoch[87]
  PIN in_epoch[88]
    DIRECTION INPUT ;
    USE SIGNAL ;
    PORT
      LAYER M4 ;
        RECT  0 16.368 0.084 16.392 ;
    END
  END in_epoch[88]
  PIN in_epoch[89]
    DIRECTION INPUT ;
    USE SIGNAL ;
    PORT
      LAYER M4 ;
        RECT  0 16.464 0.084 16.488 ;
    END
  END in_epoch[89]
  PIN in_epoch[8]
    DIRECTION INPUT ;
    USE SIGNAL ;
    PORT
      LAYER M4 ;
        RECT  0 27.888 0.084 27.912 ;
    END
  END in_epoch[8]
  PIN in_epoch[90]
    DIRECTION INPUT ;
    USE SIGNAL ;
    PORT
      LAYER M4 ;
        RECT  0 16.56 0.084 16.584 ;
    END
  END in_epoch[90]
  PIN in_epoch[91]
    DIRECTION INPUT ;
    USE SIGNAL ;
    PORT
      LAYER M4 ;
        RECT  0 16.656 0.084 16.68 ;
    END
  END in_epoch[91]
  PIN in_epoch[92]
    DIRECTION INPUT ;
    USE SIGNAL ;
    PORT
      LAYER M4 ;
        RECT  0 16.752 0.084 16.776 ;
    END
  END in_epoch[92]
  PIN in_epoch[93]
    DIRECTION INPUT ;
    USE SIGNAL ;
    PORT
      LAYER M4 ;
        RECT  0 16.848 0.084 16.872 ;
    END
  END in_epoch[93]
  PIN in_epoch[94]
    DIRECTION INPUT ;
    USE SIGNAL ;
    PORT
      LAYER M4 ;
        RECT  0 16.944 0.084 16.968 ;
    END
  END in_epoch[94]
  PIN in_epoch[95]
    DIRECTION INPUT ;
    USE SIGNAL ;
    PORT
      LAYER M4 ;
        RECT  0 17.04 0.084 17.064 ;
    END
  END in_epoch[95]
  PIN in_epoch[96]
    DIRECTION INPUT ;
    USE SIGNAL ;
    PORT
      LAYER M4 ;
        RECT  0 17.136 0.084 17.16 ;
    END
  END in_epoch[96]
  PIN in_epoch[97]
    DIRECTION INPUT ;
    USE SIGNAL ;
    PORT
      LAYER M4 ;
        RECT  0 17.232 0.084 17.256 ;
    END
  END in_epoch[97]
  PIN in_epoch[98]
    DIRECTION INPUT ;
    USE SIGNAL ;
    PORT
      LAYER M4 ;
        RECT  0 17.328 0.084 17.352 ;
    END
  END in_epoch[98]
  PIN in_epoch[99]
    DIRECTION INPUT ;
    USE SIGNAL ;
    PORT
      LAYER M4 ;
        RECT  0 17.424 0.084 17.448 ;
    END
  END in_epoch[99]
  PIN in_epoch[9]
    DIRECTION INPUT ;
    USE SIGNAL ;
    PORT
      LAYER M4 ;
        RECT  0 27.984 0.084 28.008 ;
    END
  END in_epoch[9]
  PIN in_t[0]
    DIRECTION INPUT ;
    USE SIGNAL ;
    PORT
      LAYER M4 ;
        RECT  0 30.192 0.084 30.216 ;
    END
  END in_t[0]
  PIN in_t[100]
    DIRECTION INPUT ;
    USE SIGNAL ;
    PORT
      LAYER M4 ;
        RECT  0 21.36 0.084 21.384 ;
    END
  END in_t[100]
  PIN in_t[101]
    DIRECTION INPUT ;
    USE SIGNAL ;
    PORT
      LAYER M4 ;
        RECT  0 21.456 0.084 21.48 ;
    END
  END in_t[101]
  PIN in_t[102]
    DIRECTION INPUT ;
    USE SIGNAL ;
    PORT
      LAYER M4 ;
        RECT  0 21.552 0.084 21.576 ;
    END
  END in_t[102]
  PIN in_t[103]
    DIRECTION INPUT ;
    USE SIGNAL ;
    PORT
      LAYER M4 ;
        RECT  0 21.648 0.084 21.672 ;
    END
  END in_t[103]
  PIN in_t[104]
    DIRECTION INPUT ;
    USE SIGNAL ;
    PORT
      LAYER M4 ;
        RECT  0 21.744 0.084 21.768 ;
    END
  END in_t[104]
  PIN in_t[105]
    DIRECTION INPUT ;
    USE SIGNAL ;
    PORT
      LAYER M4 ;
        RECT  0 21.84 0.084 21.864 ;
    END
  END in_t[105]
  PIN in_t[106]
    DIRECTION INPUT ;
    USE SIGNAL ;
    PORT
      LAYER M4 ;
        RECT  0 21.936 0.084 21.96 ;
    END
  END in_t[106]
  PIN in_t[107]
    DIRECTION INPUT ;
    USE SIGNAL ;
    PORT
      LAYER M4 ;
        RECT  0 22.032 0.084 22.056 ;
    END
  END in_t[107]
  PIN in_t[108]
    DIRECTION INPUT ;
    USE SIGNAL ;
    PORT
      LAYER M4 ;
        RECT  0 22.128 0.084 22.152 ;
    END
  END in_t[108]
  PIN in_t[109]
    DIRECTION INPUT ;
    USE SIGNAL ;
    PORT
      LAYER M4 ;
        RECT  0 22.224 0.084 22.248 ;
    END
  END in_t[109]
  PIN in_t[10]
    DIRECTION INPUT ;
    USE SIGNAL ;
    PORT
      LAYER M4 ;
        RECT  0 31.152 0.084 31.176 ;
    END
  END in_t[10]
  PIN in_t[110]
    DIRECTION INPUT ;
    USE SIGNAL ;
    PORT
      LAYER M4 ;
        RECT  0 22.32 0.084 22.344 ;
    END
  END in_t[110]
  PIN in_t[111]
    DIRECTION INPUT ;
    USE SIGNAL ;
    PORT
      LAYER M4 ;
        RECT  0 22.416 0.084 22.44 ;
    END
  END in_t[111]
  PIN in_t[11]
    DIRECTION INPUT ;
    USE SIGNAL ;
    PORT
      LAYER M4 ;
        RECT  0 31.248 0.084 31.272 ;
    END
  END in_t[11]
  PIN in_t[12]
    DIRECTION INPUT ;
    USE SIGNAL ;
    PORT
      LAYER M4 ;
        RECT  0 31.344 0.084 31.368 ;
    END
  END in_t[12]
  PIN in_t[13]
    DIRECTION INPUT ;
    USE SIGNAL ;
    PORT
      LAYER M4 ;
        RECT  0 31.44 0.084 31.464 ;
    END
  END in_t[13]
  PIN in_t[14]
    DIRECTION INPUT ;
    USE SIGNAL ;
    PORT
      LAYER M4 ;
        RECT  0 31.536 0.084 31.56 ;
    END
  END in_t[14]
  PIN in_t[15]
    DIRECTION INPUT ;
    USE SIGNAL ;
    PORT
      LAYER M4 ;
        RECT  0 31.632 0.084 31.656 ;
    END
  END in_t[15]
  PIN in_t[16]
    DIRECTION INPUT ;
    USE SIGNAL ;
    PORT
      LAYER M4 ;
        RECT  0 31.728 0.084 31.752 ;
    END
  END in_t[16]
  PIN in_t[17]
    DIRECTION INPUT ;
    USE SIGNAL ;
    PORT
      LAYER M4 ;
        RECT  0 31.824 0.084 31.848 ;
    END
  END in_t[17]
  PIN in_t[18]
    DIRECTION INPUT ;
    USE SIGNAL ;
    PORT
      LAYER M4 ;
        RECT  0 31.92 0.084 31.944 ;
    END
  END in_t[18]
  PIN in_t[19]
    DIRECTION INPUT ;
    USE SIGNAL ;
    PORT
      LAYER M4 ;
        RECT  0 32.016 0.084 32.04 ;
    END
  END in_t[19]
  PIN in_t[1]
    DIRECTION INPUT ;
    USE SIGNAL ;
    PORT
      LAYER M4 ;
        RECT  0 30.288 0.084 30.312 ;
    END
  END in_t[1]
  PIN in_t[20]
    DIRECTION INPUT ;
    USE SIGNAL ;
    PORT
      LAYER M4 ;
        RECT  0 32.112 0.084 32.136 ;
    END
  END in_t[20]
  PIN in_t[21]
    DIRECTION INPUT ;
    USE SIGNAL ;
    PORT
      LAYER M4 ;
        RECT  0 32.208 0.084 32.232 ;
    END
  END in_t[21]
  PIN in_t[22]
    DIRECTION INPUT ;
    USE SIGNAL ;
    PORT
      LAYER M4 ;
        RECT  0 32.304 0.084 32.328 ;
    END
  END in_t[22]
  PIN in_t[23]
    DIRECTION INPUT ;
    USE SIGNAL ;
    PORT
      LAYER M4 ;
        RECT  0 32.4 0.084 32.424 ;
    END
  END in_t[23]
  PIN in_t[24]
    DIRECTION INPUT ;
    USE SIGNAL ;
    PORT
      LAYER M4 ;
        RECT  0 32.496 0.084 32.52 ;
    END
  END in_t[24]
  PIN in_t[25]
    DIRECTION INPUT ;
    USE SIGNAL ;
    PORT
      LAYER M4 ;
        RECT  0 32.592 0.084 32.616 ;
    END
  END in_t[25]
  PIN in_t[26]
    DIRECTION INPUT ;
    USE SIGNAL ;
    PORT
      LAYER M4 ;
        RECT  0 32.688 0.084 32.712 ;
    END
  END in_t[26]
  PIN in_t[27]
    DIRECTION INPUT ;
    USE SIGNAL ;
    PORT
      LAYER M4 ;
        RECT  0 32.784 0.084 32.808 ;
    END
  END in_t[27]
  PIN in_t[28]
    DIRECTION INPUT ;
    USE SIGNAL ;
    PORT
      LAYER M4 ;
        RECT  0 32.88 0.084 32.904 ;
    END
  END in_t[28]
  PIN in_t[29]
    DIRECTION INPUT ;
    USE SIGNAL ;
    PORT
      LAYER M4 ;
        RECT  0 32.976 0.084 33 ;
    END
  END in_t[29]
  PIN in_t[2]
    DIRECTION INPUT ;
    USE SIGNAL ;
    PORT
      LAYER M4 ;
        RECT  0 30.384 0.084 30.408 ;
    END
  END in_t[2]
  PIN in_t[30]
    DIRECTION INPUT ;
    USE SIGNAL ;
    PORT
      LAYER M4 ;
        RECT  0 33.072 0.084 33.096 ;
    END
  END in_t[30]
  PIN in_t[31]
    DIRECTION INPUT ;
    USE SIGNAL ;
    PORT
      LAYER M4 ;
        RECT  0 33.168 0.084 33.192 ;
    END
  END in_t[31]
  PIN in_t[32]
    DIRECTION INPUT ;
    USE SIGNAL ;
    PORT
      LAYER M4 ;
        RECT  0 33.264 0.084 33.288 ;
    END
  END in_t[32]
  PIN in_t[33]
    DIRECTION INPUT ;
    USE SIGNAL ;
    PORT
      LAYER M4 ;
        RECT  0 33.36 0.084 33.384 ;
    END
  END in_t[33]
  PIN in_t[34]
    DIRECTION INPUT ;
    USE SIGNAL ;
    PORT
      LAYER M4 ;
        RECT  0 33.456 0.084 33.48 ;
    END
  END in_t[34]
  PIN in_t[35]
    DIRECTION INPUT ;
    USE SIGNAL ;
    PORT
      LAYER M4 ;
        RECT  0 33.552 0.084 33.576 ;
    END
  END in_t[35]
  PIN in_t[36]
    DIRECTION INPUT ;
    USE SIGNAL ;
    PORT
      LAYER M4 ;
        RECT  0 33.648 0.084 33.672 ;
    END
  END in_t[36]
  PIN in_t[37]
    DIRECTION INPUT ;
    USE SIGNAL ;
    PORT
      LAYER M4 ;
        RECT  0 33.744 0.084 33.768 ;
    END
  END in_t[37]
  PIN in_t[38]
    DIRECTION INPUT ;
    USE SIGNAL ;
    PORT
      LAYER M4 ;
        RECT  0 33.84 0.084 33.864 ;
    END
  END in_t[38]
  PIN in_t[39]
    DIRECTION INPUT ;
    USE SIGNAL ;
    PORT
      LAYER M4 ;
        RECT  0 33.936 0.084 33.96 ;
    END
  END in_t[39]
  PIN in_t[3]
    DIRECTION INPUT ;
    USE SIGNAL ;
    PORT
      LAYER M4 ;
        RECT  0 30.48 0.084 30.504 ;
    END
  END in_t[3]
  PIN in_t[40]
    DIRECTION INPUT ;
    USE SIGNAL ;
    PORT
      LAYER M4 ;
        RECT  0 34.032 0.084 34.056 ;
    END
  END in_t[40]
  PIN in_t[41]
    DIRECTION INPUT ;
    USE SIGNAL ;
    PORT
      LAYER M4 ;
        RECT  0 34.128 0.084 34.152 ;
    END
  END in_t[41]
  PIN in_t[42]
    DIRECTION INPUT ;
    USE SIGNAL ;
    PORT
      LAYER M4 ;
        RECT  0 34.224 0.084 34.248 ;
    END
  END in_t[42]
  PIN in_t[43]
    DIRECTION INPUT ;
    USE SIGNAL ;
    PORT
      LAYER M4 ;
        RECT  0 34.32 0.084 34.344 ;
    END
  END in_t[43]
  PIN in_t[44]
    DIRECTION INPUT ;
    USE SIGNAL ;
    PORT
      LAYER M4 ;
        RECT  0 34.416 0.084 34.44 ;
    END
  END in_t[44]
  PIN in_t[45]
    DIRECTION INPUT ;
    USE SIGNAL ;
    PORT
      LAYER M4 ;
        RECT  0 34.512 0.084 34.536 ;
    END
  END in_t[45]
  PIN in_t[46]
    DIRECTION INPUT ;
    USE SIGNAL ;
    PORT
      LAYER M4 ;
        RECT  0 34.608 0.084 34.632 ;
    END
  END in_t[46]
  PIN in_t[47]
    DIRECTION INPUT ;
    USE SIGNAL ;
    PORT
      LAYER M4 ;
        RECT  0 34.704 0.084 34.728 ;
    END
  END in_t[47]
  PIN in_t[48]
    DIRECTION INPUT ;
    USE SIGNAL ;
    PORT
      LAYER M4 ;
        RECT  0 34.8 0.084 34.824 ;
    END
  END in_t[48]
  PIN in_t[49]
    DIRECTION INPUT ;
    USE SIGNAL ;
    PORT
      LAYER M4 ;
        RECT  0 34.896 0.084 34.92 ;
    END
  END in_t[49]
  PIN in_t[4]
    DIRECTION INPUT ;
    USE SIGNAL ;
    PORT
      LAYER M4 ;
        RECT  0 30.576 0.084 30.6 ;
    END
  END in_t[4]
  PIN in_t[50]
    DIRECTION INPUT ;
    USE SIGNAL ;
    PORT
      LAYER M4 ;
        RECT  0 34.992 0.084 35.016 ;
    END
  END in_t[50]
  PIN in_t[51]
    DIRECTION INPUT ;
    USE SIGNAL ;
    PORT
      LAYER M4 ;
        RECT  0 35.088 0.084 35.112 ;
    END
  END in_t[51]
  PIN in_t[52]
    DIRECTION INPUT ;
    USE SIGNAL ;
    PORT
      LAYER M4 ;
        RECT  0 35.184 0.084 35.208 ;
    END
  END in_t[52]
  PIN in_t[53]
    DIRECTION INPUT ;
    USE SIGNAL ;
    PORT
      LAYER M4 ;
        RECT  0 35.28 0.084 35.304 ;
    END
  END in_t[53]
  PIN in_t[54]
    DIRECTION INPUT ;
    USE SIGNAL ;
    PORT
      LAYER M4 ;
        RECT  0 35.376 0.084 35.4 ;
    END
  END in_t[54]
  PIN in_t[55]
    DIRECTION INPUT ;
    USE SIGNAL ;
    PORT
      LAYER M4 ;
        RECT  0 35.472 0.084 35.496 ;
    END
  END in_t[55]
  PIN in_t[56]
    DIRECTION INPUT ;
    USE SIGNAL ;
    PORT
      LAYER M4 ;
        RECT  0 35.568 0.084 35.592 ;
    END
  END in_t[56]
  PIN in_t[57]
    DIRECTION INPUT ;
    USE SIGNAL ;
    PORT
      LAYER M4 ;
        RECT  0 35.664 0.084 35.688 ;
    END
  END in_t[57]
  PIN in_t[58]
    DIRECTION INPUT ;
    USE SIGNAL ;
    PORT
      LAYER M4 ;
        RECT  0 35.76 0.084 35.784 ;
    END
  END in_t[58]
  PIN in_t[59]
    DIRECTION INPUT ;
    USE SIGNAL ;
    PORT
      LAYER M4 ;
        RECT  0 35.856 0.084 35.88 ;
    END
  END in_t[59]
  PIN in_t[5]
    DIRECTION INPUT ;
    USE SIGNAL ;
    PORT
      LAYER M4 ;
        RECT  0 30.672 0.084 30.696 ;
    END
  END in_t[5]
  PIN in_t[60]
    DIRECTION INPUT ;
    USE SIGNAL ;
    PORT
      LAYER M4 ;
        RECT  0 35.952 0.084 35.976 ;
    END
  END in_t[60]
  PIN in_t[61]
    DIRECTION INPUT ;
    USE SIGNAL ;
    PORT
      LAYER M4 ;
        RECT  0 36.048 0.084 36.072 ;
    END
  END in_t[61]
  PIN in_t[62]
    DIRECTION INPUT ;
    USE SIGNAL ;
    PORT
      LAYER M4 ;
        RECT  0 36.144 0.084 36.168 ;
    END
  END in_t[62]
  PIN in_t[63]
    DIRECTION INPUT ;
    USE SIGNAL ;
    PORT
      LAYER M4 ;
        RECT  0 36.24 0.084 36.264 ;
    END
  END in_t[63]
  PIN in_t[64]
    DIRECTION INPUT ;
    USE SIGNAL ;
    PORT
      LAYER M4 ;
        RECT  0 10.992 0.084 11.016 ;
    END
  END in_t[64]
  PIN in_t[65]
    DIRECTION INPUT ;
    USE SIGNAL ;
    PORT
      LAYER M4 ;
        RECT  0 11.088 0.084 11.112 ;
    END
  END in_t[65]
  PIN in_t[66]
    DIRECTION INPUT ;
    USE SIGNAL ;
    PORT
      LAYER M4 ;
        RECT  0 11.184 0.084 11.208 ;
    END
  END in_t[66]
  PIN in_t[67]
    DIRECTION INPUT ;
    USE SIGNAL ;
    PORT
      LAYER M4 ;
        RECT  0 11.28 0.084 11.304 ;
    END
  END in_t[67]
  PIN in_t[68]
    DIRECTION INPUT ;
    USE SIGNAL ;
    PORT
      LAYER M4 ;
        RECT  0 11.376 0.084 11.4 ;
    END
  END in_t[68]
  PIN in_t[69]
    DIRECTION INPUT ;
    USE SIGNAL ;
    PORT
      LAYER M4 ;
        RECT  0 11.472 0.084 11.496 ;
    END
  END in_t[69]
  PIN in_t[6]
    DIRECTION INPUT ;
    USE SIGNAL ;
    PORT
      LAYER M4 ;
        RECT  0 30.768 0.084 30.792 ;
    END
  END in_t[6]
  PIN in_t[70]
    DIRECTION INPUT ;
    USE SIGNAL ;
    PORT
      LAYER M4 ;
        RECT  0 11.568 0.084 11.592 ;
    END
  END in_t[70]
  PIN in_t[71]
    DIRECTION INPUT ;
    USE SIGNAL ;
    PORT
      LAYER M4 ;
        RECT  0 11.664 0.084 11.688 ;
    END
  END in_t[71]
  PIN in_t[72]
    DIRECTION INPUT ;
    USE SIGNAL ;
    PORT
      LAYER M4 ;
        RECT  0 11.76 0.084 11.784 ;
    END
  END in_t[72]
  PIN in_t[73]
    DIRECTION INPUT ;
    USE SIGNAL ;
    PORT
      LAYER M4 ;
        RECT  0 11.856 0.084 11.88 ;
    END
  END in_t[73]
  PIN in_t[74]
    DIRECTION INPUT ;
    USE SIGNAL ;
    PORT
      LAYER M4 ;
        RECT  0 11.952 0.084 11.976 ;
    END
  END in_t[74]
  PIN in_t[75]
    DIRECTION INPUT ;
    USE SIGNAL ;
    PORT
      LAYER M4 ;
        RECT  0 12.048 0.084 12.072 ;
    END
  END in_t[75]
  PIN in_t[76]
    DIRECTION INPUT ;
    USE SIGNAL ;
    PORT
      LAYER M4 ;
        RECT  0 12.144 0.084 12.168 ;
    END
  END in_t[76]
  PIN in_t[77]
    DIRECTION INPUT ;
    USE SIGNAL ;
    PORT
      LAYER M4 ;
        RECT  0 12.24 0.084 12.264 ;
    END
  END in_t[77]
  PIN in_t[78]
    DIRECTION INPUT ;
    USE SIGNAL ;
    PORT
      LAYER M4 ;
        RECT  0 12.336 0.084 12.36 ;
    END
  END in_t[78]
  PIN in_t[79]
    DIRECTION INPUT ;
    USE SIGNAL ;
    PORT
      LAYER M4 ;
        RECT  0 12.432 0.084 12.456 ;
    END
  END in_t[79]
  PIN in_t[7]
    DIRECTION INPUT ;
    USE SIGNAL ;
    PORT
      LAYER M4 ;
        RECT  0 30.864 0.084 30.888 ;
    END
  END in_t[7]
  PIN in_t[80]
    DIRECTION INPUT ;
    USE SIGNAL ;
    PORT
      LAYER M4 ;
        RECT  0 12.528 0.084 12.552 ;
    END
  END in_t[80]
  PIN in_t[81]
    DIRECTION INPUT ;
    USE SIGNAL ;
    PORT
      LAYER M4 ;
        RECT  0 12.624 0.084 12.648 ;
    END
  END in_t[81]
  PIN in_t[82]
    DIRECTION INPUT ;
    USE SIGNAL ;
    PORT
      LAYER M4 ;
        RECT  0 12.72 0.084 12.744 ;
    END
  END in_t[82]
  PIN in_t[83]
    DIRECTION INPUT ;
    USE SIGNAL ;
    PORT
      LAYER M4 ;
        RECT  0 12.816 0.084 12.84 ;
    END
  END in_t[83]
  PIN in_t[84]
    DIRECTION INPUT ;
    USE SIGNAL ;
    PORT
      LAYER M4 ;
        RECT  0 12.912 0.084 12.936 ;
    END
  END in_t[84]
  PIN in_t[85]
    DIRECTION INPUT ;
    USE SIGNAL ;
    PORT
      LAYER M4 ;
        RECT  0 13.008 0.084 13.032 ;
    END
  END in_t[85]
  PIN in_t[86]
    DIRECTION INPUT ;
    USE SIGNAL ;
    PORT
      LAYER M4 ;
        RECT  0 13.104 0.084 13.128 ;
    END
  END in_t[86]
  PIN in_t[87]
    DIRECTION INPUT ;
    USE SIGNAL ;
    PORT
      LAYER M4 ;
        RECT  0 13.2 0.084 13.224 ;
    END
  END in_t[87]
  PIN in_t[88]
    DIRECTION INPUT ;
    USE SIGNAL ;
    PORT
      LAYER M4 ;
        RECT  0 13.296 0.084 13.32 ;
    END
  END in_t[88]
  PIN in_t[89]
    DIRECTION INPUT ;
    USE SIGNAL ;
    PORT
      LAYER M4 ;
        RECT  0 13.392 0.084 13.416 ;
    END
  END in_t[89]
  PIN in_t[8]
    DIRECTION INPUT ;
    USE SIGNAL ;
    PORT
      LAYER M4 ;
        RECT  0 30.96 0.084 30.984 ;
    END
  END in_t[8]
  PIN in_t[90]
    DIRECTION INPUT ;
    USE SIGNAL ;
    PORT
      LAYER M4 ;
        RECT  0 13.488 0.084 13.512 ;
    END
  END in_t[90]
  PIN in_t[91]
    DIRECTION INPUT ;
    USE SIGNAL ;
    PORT
      LAYER M4 ;
        RECT  0 13.584 0.084 13.608 ;
    END
  END in_t[91]
  PIN in_t[92]
    DIRECTION INPUT ;
    USE SIGNAL ;
    PORT
      LAYER M4 ;
        RECT  0 13.68 0.084 13.704 ;
    END
  END in_t[92]
  PIN in_t[93]
    DIRECTION INPUT ;
    USE SIGNAL ;
    PORT
      LAYER M4 ;
        RECT  0 13.776 0.084 13.8 ;
    END
  END in_t[93]
  PIN in_t[94]
    DIRECTION INPUT ;
    USE SIGNAL ;
    PORT
      LAYER M4 ;
        RECT  0 13.872 0.084 13.896 ;
    END
  END in_t[94]
  PIN in_t[95]
    DIRECTION INPUT ;
    USE SIGNAL ;
    PORT
      LAYER M4 ;
        RECT  0 13.968 0.084 13.992 ;
    END
  END in_t[95]
  PIN in_t[96]
    DIRECTION INPUT ;
    USE SIGNAL ;
    PORT
      LAYER M4 ;
        RECT  0 20.976 0.084 21 ;
    END
  END in_t[96]
  PIN in_t[97]
    DIRECTION INPUT ;
    USE SIGNAL ;
    PORT
      LAYER M4 ;
        RECT  0 21.072 0.084 21.096 ;
    END
  END in_t[97]
  PIN in_t[98]
    DIRECTION INPUT ;
    USE SIGNAL ;
    PORT
      LAYER M4 ;
        RECT  0 21.168 0.084 21.192 ;
    END
  END in_t[98]
  PIN in_t[99]
    DIRECTION INPUT ;
    USE SIGNAL ;
    PORT
      LAYER M4 ;
        RECT  0 21.264 0.084 21.288 ;
    END
  END in_t[99]
  PIN in_t[9]
    DIRECTION INPUT ;
    USE SIGNAL ;
    PORT
      LAYER M4 ;
        RECT  0 31.056 0.084 31.08 ;
    END
  END in_t[9]
  PIN in_valid[0]
    DIRECTION INPUT ;
    USE SIGNAL ;
    PORT
      LAYER M4 ;
        RECT  0 22.512 0.084 22.536 ;
    END
  END in_valid[0]
  PIN in_valid[1]
    DIRECTION INPUT ;
    USE SIGNAL ;
    PORT
      LAYER M4 ;
        RECT  0 22.608 0.084 22.632 ;
    END
  END in_valid[1]
  PIN in_valid[2]
    DIRECTION INPUT ;
    USE SIGNAL ;
    PORT
      LAYER M4 ;
        RECT  0 22.704 0.084 22.728 ;
    END
  END in_valid[2]
  PIN in_valid[3]
    DIRECTION INPUT ;
    USE SIGNAL ;
    PORT
      LAYER M4 ;
        RECT  0 22.8 0.084 22.824 ;
    END
  END in_valid[3]
  PIN in_valid[4]
    DIRECTION INPUT ;
    USE SIGNAL ;
    PORT
      LAYER M4 ;
        RECT  0 22.896 0.084 22.92 ;
    END
  END in_valid[4]
  PIN in_valid[5]
    DIRECTION INPUT ;
    USE SIGNAL ;
    PORT
      LAYER M4 ;
        RECT  0 22.992 0.084 23.016 ;
    END
  END in_valid[5]
  PIN in_valid[6]
    DIRECTION INPUT ;
    USE SIGNAL ;
    PORT
      LAYER M4 ;
        RECT  0 23.088 0.084 23.112 ;
    END
  END in_valid[6]
  PIN in_valid[7]
    DIRECTION INPUT ;
    USE SIGNAL ;
    PORT
      LAYER M4 ;
        RECT  0 23.184 0.084 23.208 ;
    END
  END in_valid[7]
  PIN out_age[0]
    DIRECTION OUTPUT ;
    USE SIGNAL ;
    PORT
      LAYER M5 ;
        RECT  13.104 0 13.128 0.084 ;
    END
  END out_age[0]
  PIN out_age[10]
    DIRECTION OUTPUT ;
    USE SIGNAL ;
    PORT
      LAYER M5 ;
        RECT  14.064 0 14.088 0.084 ;
    END
  END out_age[10]
  PIN out_age[11]
    DIRECTION OUTPUT ;
    USE SIGNAL ;
    PORT
      LAYER M5 ;
        RECT  14.16 0 14.184 0.084 ;
    END
  END out_age[11]
  PIN out_age[12]
    DIRECTION OUTPUT ;
    USE SIGNAL ;
    PORT
      LAYER M5 ;
        RECT  14.256 0 14.28 0.084 ;
    END
  END out_age[12]
  PIN out_age[13]
    DIRECTION OUTPUT ;
    USE SIGNAL ;
    PORT
      LAYER M5 ;
        RECT  14.352 0 14.376 0.084 ;
    END
  END out_age[13]
  PIN out_age[14]
    DIRECTION OUTPUT ;
    USE SIGNAL ;
    PORT
      LAYER M5 ;
        RECT  14.448 0 14.472 0.084 ;
    END
  END out_age[14]
  PIN out_age[15]
    DIRECTION OUTPUT ;
    USE SIGNAL ;
    PORT
      LAYER M5 ;
        RECT  14.544 0 14.568 0.084 ;
    END
  END out_age[15]
  PIN out_age[1]
    DIRECTION OUTPUT ;
    USE SIGNAL ;
    PORT
      LAYER M5 ;
        RECT  13.2 0 13.224 0.084 ;
    END
  END out_age[1]
  PIN out_age[2]
    DIRECTION OUTPUT ;
    USE SIGNAL ;
    PORT
      LAYER M5 ;
        RECT  13.296 0 13.32 0.084 ;
    END
  END out_age[2]
  PIN out_age[3]
    DIRECTION OUTPUT ;
    USE SIGNAL ;
    PORT
      LAYER M5 ;
        RECT  13.392 0 13.416 0.084 ;
    END
  END out_age[3]
  PIN out_age[4]
    DIRECTION OUTPUT ;
    USE SIGNAL ;
    PORT
      LAYER M5 ;
        RECT  13.488 0 13.512 0.084 ;
    END
  END out_age[4]
  PIN out_age[5]
    DIRECTION OUTPUT ;
    USE SIGNAL ;
    PORT
      LAYER M5 ;
        RECT  13.584 0 13.608 0.084 ;
    END
  END out_age[5]
  PIN out_age[6]
    DIRECTION OUTPUT ;
    USE SIGNAL ;
    PORT
      LAYER M5 ;
        RECT  13.68 0 13.704 0.084 ;
    END
  END out_age[6]
  PIN out_age[7]
    DIRECTION OUTPUT ;
    USE SIGNAL ;
    PORT
      LAYER M5 ;
        RECT  13.776 0 13.8 0.084 ;
    END
  END out_age[7]
  PIN out_age[8]
    DIRECTION OUTPUT ;
    USE SIGNAL ;
    PORT
      LAYER M5 ;
        RECT  13.872 0 13.896 0.084 ;
    END
  END out_age[8]
  PIN out_age[9]
    DIRECTION OUTPUT ;
    USE SIGNAL ;
    PORT
      LAYER M5 ;
        RECT  13.968 0 13.992 0.084 ;
    END
  END out_age[9]
  PIN out_epoch[0]
    DIRECTION OUTPUT ;
    USE SIGNAL ;
    PORT
      LAYER M5 ;
        RECT  14.64 0 14.664 0.084 ;
    END
  END out_epoch[0]
  PIN out_epoch[10]
    DIRECTION OUTPUT ;
    USE SIGNAL ;
    PORT
      LAYER M5 ;
        RECT  15.6 0 15.624 0.084 ;
    END
  END out_epoch[10]
  PIN out_epoch[11]
    DIRECTION OUTPUT ;
    USE SIGNAL ;
    PORT
      LAYER M5 ;
        RECT  15.696 0 15.72 0.084 ;
    END
  END out_epoch[11]
  PIN out_epoch[12]
    DIRECTION OUTPUT ;
    USE SIGNAL ;
    PORT
      LAYER M5 ;
        RECT  15.792 0 15.816 0.084 ;
    END
  END out_epoch[12]
  PIN out_epoch[13]
    DIRECTION OUTPUT ;
    USE SIGNAL ;
    PORT
      LAYER M5 ;
        RECT  15.888 0 15.912 0.084 ;
    END
  END out_epoch[13]
  PIN out_epoch[14]
    DIRECTION OUTPUT ;
    USE SIGNAL ;
    PORT
      LAYER M5 ;
        RECT  15.984 0 16.008 0.084 ;
    END
  END out_epoch[14]
  PIN out_epoch[15]
    DIRECTION OUTPUT ;
    USE SIGNAL ;
    PORT
      LAYER M5 ;
        RECT  16.08 0 16.104 0.084 ;
    END
  END out_epoch[15]
  PIN out_epoch[1]
    DIRECTION OUTPUT ;
    USE SIGNAL ;
    PORT
      LAYER M5 ;
        RECT  14.736 0 14.76 0.084 ;
    END
  END out_epoch[1]
  PIN out_epoch[2]
    DIRECTION OUTPUT ;
    USE SIGNAL ;
    PORT
      LAYER M5 ;
        RECT  14.832 0 14.856 0.084 ;
    END
  END out_epoch[2]
  PIN out_epoch[3]
    DIRECTION OUTPUT ;
    USE SIGNAL ;
    PORT
      LAYER M5 ;
        RECT  14.928 0 14.952 0.084 ;
    END
  END out_epoch[3]
  PIN out_epoch[4]
    DIRECTION OUTPUT ;
    USE SIGNAL ;
    PORT
      LAYER M5 ;
        RECT  15.024 0 15.048 0.084 ;
    END
  END out_epoch[4]
  PIN out_epoch[5]
    DIRECTION OUTPUT ;
    USE SIGNAL ;
    PORT
      LAYER M5 ;
        RECT  15.12 0 15.144 0.084 ;
    END
  END out_epoch[5]
  PIN out_epoch[6]
    DIRECTION OUTPUT ;
    USE SIGNAL ;
    PORT
      LAYER M5 ;
        RECT  15.216 0 15.24 0.084 ;
    END
  END out_epoch[6]
  PIN out_epoch[7]
    DIRECTION OUTPUT ;
    USE SIGNAL ;
    PORT
      LAYER M5 ;
        RECT  15.312 0 15.336 0.084 ;
    END
  END out_epoch[7]
  PIN out_epoch[8]
    DIRECTION OUTPUT ;
    USE SIGNAL ;
    PORT
      LAYER M5 ;
        RECT  15.408 0 15.432 0.084 ;
    END
  END out_epoch[8]
  PIN out_epoch[9]
    DIRECTION OUTPUT ;
    USE SIGNAL ;
    PORT
      LAYER M5 ;
        RECT  15.504 0 15.528 0.084 ;
    END
  END out_epoch[9]
  PIN pair_id
    DIRECTION INPUT ;
    USE SIGNAL ;
    PORT
      LAYER M5 ;
        RECT  16.176 0 16.2 0.084 ;
    END
  END pair_id
  PIN req_t[0]
    DIRECTION OUTPUT ;
    USE SIGNAL ;
    PORT
      LAYER M4 ;
        RECT  43.116 39.12 43.2 39.144 ;
    END
  END req_t[0]
  PIN req_t[100]
    DIRECTION OUTPUT ;
    USE SIGNAL ;
    PORT
      LAYER M4 ;
        RECT  43.116 32.592 43.2 32.616 ;
    END
  END req_t[100]
  PIN req_t[101]
    DIRECTION OUTPUT ;
    USE SIGNAL ;
    PORT
      LAYER M4 ;
        RECT  43.116 32.688 43.2 32.712 ;
    END
  END req_t[101]
  PIN req_t[102]
    DIRECTION OUTPUT ;
    USE SIGNAL ;
    PORT
      LAYER M4 ;
        RECT  43.116 32.784 43.2 32.808 ;
    END
  END req_t[102]
  PIN req_t[103]
    DIRECTION OUTPUT ;
    USE SIGNAL ;
    PORT
      LAYER M4 ;
        RECT  43.116 32.88 43.2 32.904 ;
    END
  END req_t[103]
  PIN req_t[104]
    DIRECTION OUTPUT ;
    USE SIGNAL ;
    PORT
      LAYER M4 ;
        RECT  43.116 32.976 43.2 33 ;
    END
  END req_t[104]
  PIN req_t[105]
    DIRECTION OUTPUT ;
    USE SIGNAL ;
    PORT
      LAYER M4 ;
        RECT  43.116 33.072 43.2 33.096 ;
    END
  END req_t[105]
  PIN req_t[106]
    DIRECTION OUTPUT ;
    USE SIGNAL ;
    PORT
      LAYER M4 ;
        RECT  43.116 33.168 43.2 33.192 ;
    END
  END req_t[106]
  PIN req_t[107]
    DIRECTION OUTPUT ;
    USE SIGNAL ;
    PORT
      LAYER M4 ;
        RECT  43.116 33.264 43.2 33.288 ;
    END
  END req_t[107]
  PIN req_t[108]
    DIRECTION OUTPUT ;
    USE SIGNAL ;
    PORT
      LAYER M4 ;
        RECT  43.116 33.36 43.2 33.384 ;
    END
  END req_t[108]
  PIN req_t[109]
    DIRECTION OUTPUT ;
    USE SIGNAL ;
    PORT
      LAYER M4 ;
        RECT  43.116 33.456 43.2 33.48 ;
    END
  END req_t[109]
  PIN req_t[10]
    DIRECTION OUTPUT ;
    USE SIGNAL ;
    PORT
      LAYER M4 ;
        RECT  43.116 40.08 43.2 40.104 ;
    END
  END req_t[10]
  PIN req_t[110]
    DIRECTION OUTPUT ;
    USE SIGNAL ;
    PORT
      LAYER M4 ;
        RECT  43.116 33.552 43.2 33.576 ;
    END
  END req_t[110]
  PIN req_t[111]
    DIRECTION OUTPUT ;
    USE SIGNAL ;
    PORT
      LAYER M4 ;
        RECT  43.116 33.648 43.2 33.672 ;
    END
  END req_t[111]
  PIN req_t[11]
    DIRECTION OUTPUT ;
    USE SIGNAL ;
    PORT
      LAYER M4 ;
        RECT  43.116 40.176 43.2 40.2 ;
    END
  END req_t[11]
  PIN req_t[12]
    DIRECTION OUTPUT ;
    USE SIGNAL ;
    PORT
      LAYER M4 ;
        RECT  43.116 40.272 43.2 40.296 ;
    END
  END req_t[12]
  PIN req_t[13]
    DIRECTION OUTPUT ;
    USE SIGNAL ;
    PORT
      LAYER M4 ;
        RECT  43.116 40.368 43.2 40.392 ;
    END
  END req_t[13]
  PIN req_t[14]
    DIRECTION OUTPUT ;
    USE SIGNAL ;
    PORT
      LAYER M4 ;
        RECT  43.116 40.464 43.2 40.488 ;
    END
  END req_t[14]
  PIN req_t[15]
    DIRECTION OUTPUT ;
    USE SIGNAL ;
    PORT
      LAYER M4 ;
        RECT  43.116 40.56 43.2 40.584 ;
    END
  END req_t[15]
  PIN req_t[16]
    DIRECTION OUTPUT ;
    USE SIGNAL ;
    PORT
      LAYER M4 ;
        RECT  43.116 40.656 43.2 40.68 ;
    END
  END req_t[16]
  PIN req_t[17]
    DIRECTION OUTPUT ;
    USE SIGNAL ;
    PORT
      LAYER M4 ;
        RECT  43.116 40.752 43.2 40.776 ;
    END
  END req_t[17]
  PIN req_t[18]
    DIRECTION OUTPUT ;
    USE SIGNAL ;
    PORT
      LAYER M4 ;
        RECT  43.116 40.848 43.2 40.872 ;
    END
  END req_t[18]
  PIN req_t[19]
    DIRECTION OUTPUT ;
    USE SIGNAL ;
    PORT
      LAYER M4 ;
        RECT  43.116 40.944 43.2 40.968 ;
    END
  END req_t[19]
  PIN req_t[1]
    DIRECTION OUTPUT ;
    USE SIGNAL ;
    PORT
      LAYER M4 ;
        RECT  43.116 39.216 43.2 39.24 ;
    END
  END req_t[1]
  PIN req_t[20]
    DIRECTION OUTPUT ;
    USE SIGNAL ;
    PORT
      LAYER M4 ;
        RECT  43.116 41.04 43.2 41.064 ;
    END
  END req_t[20]
  PIN req_t[21]
    DIRECTION OUTPUT ;
    USE SIGNAL ;
    PORT
      LAYER M4 ;
        RECT  43.116 41.136 43.2 41.16 ;
    END
  END req_t[21]
  PIN req_t[22]
    DIRECTION OUTPUT ;
    USE SIGNAL ;
    PORT
      LAYER M4 ;
        RECT  43.116 41.232 43.2 41.256 ;
    END
  END req_t[22]
  PIN req_t[23]
    DIRECTION OUTPUT ;
    USE SIGNAL ;
    PORT
      LAYER M4 ;
        RECT  43.116 41.328 43.2 41.352 ;
    END
  END req_t[23]
  PIN req_t[24]
    DIRECTION OUTPUT ;
    USE SIGNAL ;
    PORT
      LAYER M4 ;
        RECT  43.116 41.424 43.2 41.448 ;
    END
  END req_t[24]
  PIN req_t[25]
    DIRECTION OUTPUT ;
    USE SIGNAL ;
    PORT
      LAYER M4 ;
        RECT  43.116 41.52 43.2 41.544 ;
    END
  END req_t[25]
  PIN req_t[26]
    DIRECTION OUTPUT ;
    USE SIGNAL ;
    PORT
      LAYER M4 ;
        RECT  43.116 41.616 43.2 41.64 ;
    END
  END req_t[26]
  PIN req_t[27]
    DIRECTION OUTPUT ;
    USE SIGNAL ;
    PORT
      LAYER M4 ;
        RECT  43.116 41.712 43.2 41.736 ;
    END
  END req_t[27]
  PIN req_t[28]
    DIRECTION OUTPUT ;
    USE SIGNAL ;
    PORT
      LAYER M4 ;
        RECT  43.116 41.808 43.2 41.832 ;
    END
  END req_t[28]
  PIN req_t[29]
    DIRECTION OUTPUT ;
    USE SIGNAL ;
    PORT
      LAYER M4 ;
        RECT  43.116 41.904 43.2 41.928 ;
    END
  END req_t[29]
  PIN req_t[2]
    DIRECTION OUTPUT ;
    USE SIGNAL ;
    PORT
      LAYER M4 ;
        RECT  43.116 39.312 43.2 39.336 ;
    END
  END req_t[2]
  PIN req_t[30]
    DIRECTION OUTPUT ;
    USE SIGNAL ;
    PORT
      LAYER M4 ;
        RECT  43.116 42 43.2 42.024 ;
    END
  END req_t[30]
  PIN req_t[31]
    DIRECTION OUTPUT ;
    USE SIGNAL ;
    PORT
      LAYER M4 ;
        RECT  43.116 42.096 43.2 42.12 ;
    END
  END req_t[31]
  PIN req_t[32]
    DIRECTION OUTPUT ;
    USE SIGNAL ;
    PORT
      LAYER M4 ;
        RECT  43.116 35.28 43.2 35.304 ;
    END
  END req_t[32]
  PIN req_t[33]
    DIRECTION OUTPUT ;
    USE SIGNAL ;
    PORT
      LAYER M4 ;
        RECT  43.116 35.376 43.2 35.4 ;
    END
  END req_t[33]
  PIN req_t[34]
    DIRECTION OUTPUT ;
    USE SIGNAL ;
    PORT
      LAYER M4 ;
        RECT  43.116 35.472 43.2 35.496 ;
    END
  END req_t[34]
  PIN req_t[35]
    DIRECTION OUTPUT ;
    USE SIGNAL ;
    PORT
      LAYER M4 ;
        RECT  43.116 35.568 43.2 35.592 ;
    END
  END req_t[35]
  PIN req_t[36]
    DIRECTION OUTPUT ;
    USE SIGNAL ;
    PORT
      LAYER M4 ;
        RECT  43.116 35.664 43.2 35.688 ;
    END
  END req_t[36]
  PIN req_t[37]
    DIRECTION OUTPUT ;
    USE SIGNAL ;
    PORT
      LAYER M4 ;
        RECT  43.116 35.76 43.2 35.784 ;
    END
  END req_t[37]
  PIN req_t[38]
    DIRECTION OUTPUT ;
    USE SIGNAL ;
    PORT
      LAYER M4 ;
        RECT  43.116 35.856 43.2 35.88 ;
    END
  END req_t[38]
  PIN req_t[39]
    DIRECTION OUTPUT ;
    USE SIGNAL ;
    PORT
      LAYER M4 ;
        RECT  43.116 35.952 43.2 35.976 ;
    END
  END req_t[39]
  PIN req_t[3]
    DIRECTION OUTPUT ;
    USE SIGNAL ;
    PORT
      LAYER M4 ;
        RECT  43.116 39.408 43.2 39.432 ;
    END
  END req_t[3]
  PIN req_t[40]
    DIRECTION OUTPUT ;
    USE SIGNAL ;
    PORT
      LAYER M4 ;
        RECT  43.116 36.048 43.2 36.072 ;
    END
  END req_t[40]
  PIN req_t[41]
    DIRECTION OUTPUT ;
    USE SIGNAL ;
    PORT
      LAYER M4 ;
        RECT  43.116 36.144 43.2 36.168 ;
    END
  END req_t[41]
  PIN req_t[42]
    DIRECTION OUTPUT ;
    USE SIGNAL ;
    PORT
      LAYER M4 ;
        RECT  43.116 36.24 43.2 36.264 ;
    END
  END req_t[42]
  PIN req_t[43]
    DIRECTION OUTPUT ;
    USE SIGNAL ;
    PORT
      LAYER M4 ;
        RECT  43.116 36.336 43.2 36.36 ;
    END
  END req_t[43]
  PIN req_t[44]
    DIRECTION OUTPUT ;
    USE SIGNAL ;
    PORT
      LAYER M4 ;
        RECT  43.116 36.432 43.2 36.456 ;
    END
  END req_t[44]
  PIN req_t[45]
    DIRECTION OUTPUT ;
    USE SIGNAL ;
    PORT
      LAYER M4 ;
        RECT  43.116 36.528 43.2 36.552 ;
    END
  END req_t[45]
  PIN req_t[46]
    DIRECTION OUTPUT ;
    USE SIGNAL ;
    PORT
      LAYER M4 ;
        RECT  43.116 36.624 43.2 36.648 ;
    END
  END req_t[46]
  PIN req_t[47]
    DIRECTION OUTPUT ;
    USE SIGNAL ;
    PORT
      LAYER M4 ;
        RECT  43.116 36.72 43.2 36.744 ;
    END
  END req_t[47]
  PIN req_t[48]
    DIRECTION OUTPUT ;
    USE SIGNAL ;
    PORT
      LAYER M4 ;
        RECT  43.116 36.816 43.2 36.84 ;
    END
  END req_t[48]
  PIN req_t[49]
    DIRECTION OUTPUT ;
    USE SIGNAL ;
    PORT
      LAYER M4 ;
        RECT  43.116 36.912 43.2 36.936 ;
    END
  END req_t[49]
  PIN req_t[4]
    DIRECTION OUTPUT ;
    USE SIGNAL ;
    PORT
      LAYER M4 ;
        RECT  43.116 39.504 43.2 39.528 ;
    END
  END req_t[4]
  PIN req_t[50]
    DIRECTION OUTPUT ;
    USE SIGNAL ;
    PORT
      LAYER M4 ;
        RECT  43.116 37.008 43.2 37.032 ;
    END
  END req_t[50]
  PIN req_t[51]
    DIRECTION OUTPUT ;
    USE SIGNAL ;
    PORT
      LAYER M4 ;
        RECT  43.116 37.104 43.2 37.128 ;
    END
  END req_t[51]
  PIN req_t[52]
    DIRECTION OUTPUT ;
    USE SIGNAL ;
    PORT
      LAYER M4 ;
        RECT  43.116 37.2 43.2 37.224 ;
    END
  END req_t[52]
  PIN req_t[53]
    DIRECTION OUTPUT ;
    USE SIGNAL ;
    PORT
      LAYER M4 ;
        RECT  43.116 37.296 43.2 37.32 ;
    END
  END req_t[53]
  PIN req_t[54]
    DIRECTION OUTPUT ;
    USE SIGNAL ;
    PORT
      LAYER M4 ;
        RECT  43.116 37.392 43.2 37.416 ;
    END
  END req_t[54]
  PIN req_t[55]
    DIRECTION OUTPUT ;
    USE SIGNAL ;
    PORT
      LAYER M4 ;
        RECT  43.116 37.488 43.2 37.512 ;
    END
  END req_t[55]
  PIN req_t[56]
    DIRECTION OUTPUT ;
    USE SIGNAL ;
    PORT
      LAYER M4 ;
        RECT  43.116 37.584 43.2 37.608 ;
    END
  END req_t[56]
  PIN req_t[57]
    DIRECTION OUTPUT ;
    USE SIGNAL ;
    PORT
      LAYER M4 ;
        RECT  43.116 37.68 43.2 37.704 ;
    END
  END req_t[57]
  PIN req_t[58]
    DIRECTION OUTPUT ;
    USE SIGNAL ;
    PORT
      LAYER M4 ;
        RECT  43.116 37.776 43.2 37.8 ;
    END
  END req_t[58]
  PIN req_t[59]
    DIRECTION OUTPUT ;
    USE SIGNAL ;
    PORT
      LAYER M4 ;
        RECT  43.116 37.872 43.2 37.896 ;
    END
  END req_t[59]
  PIN req_t[5]
    DIRECTION OUTPUT ;
    USE SIGNAL ;
    PORT
      LAYER M4 ;
        RECT  43.116 39.6 43.2 39.624 ;
    END
  END req_t[5]
  PIN req_t[60]
    DIRECTION OUTPUT ;
    USE SIGNAL ;
    PORT
      LAYER M4 ;
        RECT  43.116 37.968 43.2 37.992 ;
    END
  END req_t[60]
  PIN req_t[61]
    DIRECTION OUTPUT ;
    USE SIGNAL ;
    PORT
      LAYER M4 ;
        RECT  43.116 38.064 43.2 38.088 ;
    END
  END req_t[61]
  PIN req_t[62]
    DIRECTION OUTPUT ;
    USE SIGNAL ;
    PORT
      LAYER M4 ;
        RECT  43.116 38.16 43.2 38.184 ;
    END
  END req_t[62]
  PIN req_t[63]
    DIRECTION OUTPUT ;
    USE SIGNAL ;
    PORT
      LAYER M4 ;
        RECT  43.116 38.256 43.2 38.28 ;
    END
  END req_t[63]
  PIN req_t[64]
    DIRECTION OUTPUT ;
    USE SIGNAL ;
    PORT
      LAYER M4 ;
        RECT  43.116 29.136 43.2 29.16 ;
    END
  END req_t[64]
  PIN req_t[65]
    DIRECTION OUTPUT ;
    USE SIGNAL ;
    PORT
      LAYER M4 ;
        RECT  43.116 29.232 43.2 29.256 ;
    END
  END req_t[65]
  PIN req_t[66]
    DIRECTION OUTPUT ;
    USE SIGNAL ;
    PORT
      LAYER M4 ;
        RECT  43.116 29.328 43.2 29.352 ;
    END
  END req_t[66]
  PIN req_t[67]
    DIRECTION OUTPUT ;
    USE SIGNAL ;
    PORT
      LAYER M4 ;
        RECT  43.116 29.424 43.2 29.448 ;
    END
  END req_t[67]
  PIN req_t[68]
    DIRECTION OUTPUT ;
    USE SIGNAL ;
    PORT
      LAYER M4 ;
        RECT  43.116 29.52 43.2 29.544 ;
    END
  END req_t[68]
  PIN req_t[69]
    DIRECTION OUTPUT ;
    USE SIGNAL ;
    PORT
      LAYER M4 ;
        RECT  43.116 29.616 43.2 29.64 ;
    END
  END req_t[69]
  PIN req_t[6]
    DIRECTION OUTPUT ;
    USE SIGNAL ;
    PORT
      LAYER M4 ;
        RECT  43.116 39.696 43.2 39.72 ;
    END
  END req_t[6]
  PIN req_t[70]
    DIRECTION OUTPUT ;
    USE SIGNAL ;
    PORT
      LAYER M4 ;
        RECT  43.116 29.712 43.2 29.736 ;
    END
  END req_t[70]
  PIN req_t[71]
    DIRECTION OUTPUT ;
    USE SIGNAL ;
    PORT
      LAYER M4 ;
        RECT  43.116 29.808 43.2 29.832 ;
    END
  END req_t[71]
  PIN req_t[72]
    DIRECTION OUTPUT ;
    USE SIGNAL ;
    PORT
      LAYER M4 ;
        RECT  43.116 29.904 43.2 29.928 ;
    END
  END req_t[72]
  PIN req_t[73]
    DIRECTION OUTPUT ;
    USE SIGNAL ;
    PORT
      LAYER M4 ;
        RECT  43.116 30 43.2 30.024 ;
    END
  END req_t[73]
  PIN req_t[74]
    DIRECTION OUTPUT ;
    USE SIGNAL ;
    PORT
      LAYER M4 ;
        RECT  43.116 30.096 43.2 30.12 ;
    END
  END req_t[74]
  PIN req_t[75]
    DIRECTION OUTPUT ;
    USE SIGNAL ;
    PORT
      LAYER M4 ;
        RECT  43.116 30.192 43.2 30.216 ;
    END
  END req_t[75]
  PIN req_t[76]
    DIRECTION OUTPUT ;
    USE SIGNAL ;
    PORT
      LAYER M4 ;
        RECT  43.116 30.288 43.2 30.312 ;
    END
  END req_t[76]
  PIN req_t[77]
    DIRECTION OUTPUT ;
    USE SIGNAL ;
    PORT
      LAYER M4 ;
        RECT  43.116 30.384 43.2 30.408 ;
    END
  END req_t[77]
  PIN req_t[78]
    DIRECTION OUTPUT ;
    USE SIGNAL ;
    PORT
      LAYER M4 ;
        RECT  43.116 30.48 43.2 30.504 ;
    END
  END req_t[78]
  PIN req_t[79]
    DIRECTION OUTPUT ;
    USE SIGNAL ;
    PORT
      LAYER M4 ;
        RECT  43.116 30.576 43.2 30.6 ;
    END
  END req_t[79]
  PIN req_t[7]
    DIRECTION OUTPUT ;
    USE SIGNAL ;
    PORT
      LAYER M4 ;
        RECT  43.116 39.792 43.2 39.816 ;
    END
  END req_t[7]
  PIN req_t[80]
    DIRECTION OUTPUT ;
    USE SIGNAL ;
    PORT
      LAYER M4 ;
        RECT  43.116 30.672 43.2 30.696 ;
    END
  END req_t[80]
  PIN req_t[81]
    DIRECTION OUTPUT ;
    USE SIGNAL ;
    PORT
      LAYER M4 ;
        RECT  43.116 30.768 43.2 30.792 ;
    END
  END req_t[81]
  PIN req_t[82]
    DIRECTION OUTPUT ;
    USE SIGNAL ;
    PORT
      LAYER M4 ;
        RECT  43.116 30.864 43.2 30.888 ;
    END
  END req_t[82]
  PIN req_t[83]
    DIRECTION OUTPUT ;
    USE SIGNAL ;
    PORT
      LAYER M4 ;
        RECT  43.116 30.96 43.2 30.984 ;
    END
  END req_t[83]
  PIN req_t[84]
    DIRECTION OUTPUT ;
    USE SIGNAL ;
    PORT
      LAYER M4 ;
        RECT  43.116 31.056 43.2 31.08 ;
    END
  END req_t[84]
  PIN req_t[85]
    DIRECTION OUTPUT ;
    USE SIGNAL ;
    PORT
      LAYER M4 ;
        RECT  43.116 31.152 43.2 31.176 ;
    END
  END req_t[85]
  PIN req_t[86]
    DIRECTION OUTPUT ;
    USE SIGNAL ;
    PORT
      LAYER M4 ;
        RECT  43.116 31.248 43.2 31.272 ;
    END
  END req_t[86]
  PIN req_t[87]
    DIRECTION OUTPUT ;
    USE SIGNAL ;
    PORT
      LAYER M4 ;
        RECT  43.116 31.344 43.2 31.368 ;
    END
  END req_t[87]
  PIN req_t[88]
    DIRECTION OUTPUT ;
    USE SIGNAL ;
    PORT
      LAYER M4 ;
        RECT  43.116 31.44 43.2 31.464 ;
    END
  END req_t[88]
  PIN req_t[89]
    DIRECTION OUTPUT ;
    USE SIGNAL ;
    PORT
      LAYER M4 ;
        RECT  43.116 31.536 43.2 31.56 ;
    END
  END req_t[89]
  PIN req_t[8]
    DIRECTION OUTPUT ;
    USE SIGNAL ;
    PORT
      LAYER M4 ;
        RECT  43.116 39.888 43.2 39.912 ;
    END
  END req_t[8]
  PIN req_t[90]
    DIRECTION OUTPUT ;
    USE SIGNAL ;
    PORT
      LAYER M4 ;
        RECT  43.116 31.632 43.2 31.656 ;
    END
  END req_t[90]
  PIN req_t[91]
    DIRECTION OUTPUT ;
    USE SIGNAL ;
    PORT
      LAYER M4 ;
        RECT  43.116 31.728 43.2 31.752 ;
    END
  END req_t[91]
  PIN req_t[92]
    DIRECTION OUTPUT ;
    USE SIGNAL ;
    PORT
      LAYER M4 ;
        RECT  43.116 31.824 43.2 31.848 ;
    END
  END req_t[92]
  PIN req_t[93]
    DIRECTION OUTPUT ;
    USE SIGNAL ;
    PORT
      LAYER M4 ;
        RECT  43.116 31.92 43.2 31.944 ;
    END
  END req_t[93]
  PIN req_t[94]
    DIRECTION OUTPUT ;
    USE SIGNAL ;
    PORT
      LAYER M4 ;
        RECT  43.116 32.016 43.2 32.04 ;
    END
  END req_t[94]
  PIN req_t[95]
    DIRECTION OUTPUT ;
    USE SIGNAL ;
    PORT
      LAYER M4 ;
        RECT  43.116 32.112 43.2 32.136 ;
    END
  END req_t[95]
  PIN req_t[96]
    DIRECTION OUTPUT ;
    USE SIGNAL ;
    PORT
      LAYER M4 ;
        RECT  43.116 32.208 43.2 32.232 ;
    END
  END req_t[96]
  PIN req_t[97]
    DIRECTION OUTPUT ;
    USE SIGNAL ;
    PORT
      LAYER M4 ;
        RECT  43.116 32.304 43.2 32.328 ;
    END
  END req_t[97]
  PIN req_t[98]
    DIRECTION OUTPUT ;
    USE SIGNAL ;
    PORT
      LAYER M4 ;
        RECT  43.116 32.4 43.2 32.424 ;
    END
  END req_t[98]
  PIN req_t[99]
    DIRECTION OUTPUT ;
    USE SIGNAL ;
    PORT
      LAYER M4 ;
        RECT  43.116 32.496 43.2 32.52 ;
    END
  END req_t[99]
  PIN req_t[9]
    DIRECTION OUTPUT ;
    USE SIGNAL ;
    PORT
      LAYER M4 ;
        RECT  43.116 39.984 43.2 40.008 ;
    END
  END req_t[9]
  PIN req_valid[0]
    DIRECTION OUTPUT ;
    USE SIGNAL ;
    PORT
      LAYER M4 ;
        RECT  43.116 33.744 43.2 33.768 ;
    END
  END req_valid[0]
  PIN req_valid[1]
    DIRECTION OUTPUT ;
    USE SIGNAL ;
    PORT
      LAYER M4 ;
        RECT  43.116 33.84 43.2 33.864 ;
    END
  END req_valid[1]
  PIN req_valid[2]
    DIRECTION OUTPUT ;
    USE SIGNAL ;
    PORT
      LAYER M4 ;
        RECT  43.116 33.936 43.2 33.96 ;
    END
  END req_valid[2]
  PIN req_valid[3]
    DIRECTION OUTPUT ;
    USE SIGNAL ;
    PORT
      LAYER M4 ;
        RECT  43.116 34.032 43.2 34.056 ;
    END
  END req_valid[3]
  PIN req_valid[4]
    DIRECTION OUTPUT ;
    USE SIGNAL ;
    PORT
      LAYER M4 ;
        RECT  43.116 34.128 43.2 34.152 ;
    END
  END req_valid[4]
  PIN req_valid[5]
    DIRECTION OUTPUT ;
    USE SIGNAL ;
    PORT
      LAYER M4 ;
        RECT  43.116 34.224 43.2 34.248 ;
    END
  END req_valid[5]
  PIN req_valid[6]
    DIRECTION OUTPUT ;
    USE SIGNAL ;
    PORT
      LAYER M4 ;
        RECT  43.116 34.32 43.2 34.344 ;
    END
  END req_valid[6]
  PIN req_valid[7]
    DIRECTION OUTPUT ;
    USE SIGNAL ;
    PORT
      LAYER M4 ;
        RECT  43.116 34.416 43.2 34.44 ;
    END
  END req_valid[7]
  PIN rst_n
    DIRECTION INPUT ;
    USE SIGNAL ;
    PORT
      LAYER M5 ;
        RECT  16.272 0 16.296 0.084 ;
    END
  END rst_n
  PIN start
    DIRECTION INPUT ;
    USE SIGNAL ;
    PORT
      LAYER M5 ;
        RECT  16.368 0 16.392 0.084 ;
    END
  END start
  PIN VDD
    DIRECTION INOUT ;
    USE POWER ;
    PORT
      LAYER M5 ;
        RECT  40.392 2.151 40.512 41.049 ;
        RECT  34.992 2.151 35.112 41.049 ;
        RECT  29.592 2.151 29.712 41.049 ;
        RECT  24.192 2.151 24.312 41.049 ;
        RECT  18.792 2.151 18.912 41.049 ;
        RECT  13.392 2.151 13.512 41.049 ;
        RECT  7.992 2.151 8.112 41.049 ;
        RECT  2.592 2.151 2.712 41.049 ;
    END
  END VDD
  PIN VSS
    DIRECTION INOUT ;
    USE GROUND ;
    PORT
      LAYER M5 ;
        RECT  40.2 2.137 40.32 41.063 ;
        RECT  34.8 2.137 34.92 41.063 ;
        RECT  29.4 2.137 29.52 41.063 ;
        RECT  24 2.137 24.12 41.063 ;
        RECT  18.6 2.137 18.72 41.063 ;
        RECT  13.2 2.137 13.32 41.063 ;
        RECT  7.8 2.137 7.92 41.063 ;
        RECT  2.4 2.137 2.52 41.063 ;
    END
  END VSS
  # OT_OBS_CLOSED layer=M5 d_um=1.536 added=107
  OBS
    LAYER RVTN ;
     RECT  2.16 2.16 41.04 2.295 ;
     RECT  2.16 2.565 41.04 2.835 ;
     RECT  2.16 3.105 41.04 3.375 ;
     RECT  2.16 3.645 41.04 3.915 ;
     RECT  2.16 4.185 41.04 4.455 ;
     RECT  2.16 4.725 41.04 4.995 ;
     RECT  2.16 5.265 41.04 5.535 ;
     RECT  2.16 5.805 41.04 6.075 ;
     RECT  2.16 6.345 41.04 6.615 ;
     RECT  2.16 6.885 41.04 7.155 ;
     RECT  2.16 7.425 41.04 7.695 ;
     RECT  2.16 7.965 41.04 8.235 ;
     RECT  2.16 8.505 41.04 8.775 ;
     RECT  2.16 9.045 41.04 9.315 ;
     RECT  2.16 9.585 41.04 9.855 ;
     RECT  2.16 10.125 41.04 10.395 ;
     RECT  2.16 10.665 41.04 10.935 ;
     RECT  2.16 11.205 41.04 11.475 ;
     RECT  2.16 11.745 41.04 12.015 ;
     RECT  2.16 12.285 41.04 12.555 ;
     RECT  2.16 12.825 41.04 13.095 ;
     RECT  2.16 13.365 41.04 13.635 ;
     RECT  2.16 13.905 41.04 14.175 ;
     RECT  2.16 14.445 41.04 14.715 ;
     RECT  2.16 14.985 41.04 15.255 ;
     RECT  2.16 15.525 41.04 15.795 ;
     RECT  2.16 16.065 41.04 16.335 ;
     RECT  2.16 16.605 41.04 16.875 ;
     RECT  2.16 17.145 41.04 17.415 ;
     RECT  2.16 17.685 41.04 17.955 ;
     RECT  2.16 18.225 41.04 18.495 ;
     RECT  2.16 18.765 41.04 19.035 ;
     RECT  2.16 19.305 41.04 19.575 ;
     RECT  2.16 19.845 41.04 20.115 ;
     RECT  2.16 20.385 41.04 20.655 ;
     RECT  2.16 20.925 41.04 21.195 ;
     RECT  2.16 21.465 41.04 21.735 ;
     RECT  2.16 22.005 41.04 22.275 ;
     RECT  2.16 22.545 41.04 22.815 ;
     RECT  2.16 23.085 41.04 23.355 ;
     RECT  2.16 23.625 41.04 23.895 ;
     RECT  2.16 24.165 41.04 24.435 ;
     RECT  2.16 24.705 41.04 24.975 ;
     RECT  2.16 25.245 41.04 25.515 ;
     RECT  2.16 25.785 41.04 26.055 ;
     RECT  2.16 26.325 41.04 26.595 ;
     RECT  2.16 26.865 41.04 27.135 ;
     RECT  2.16 27.405 41.04 27.675 ;
     RECT  2.16 27.945 41.04 28.215 ;
     RECT  2.16 28.485 41.04 28.755 ;
     RECT  2.16 29.025 41.04 29.295 ;
     RECT  2.16 29.565 41.04 29.835 ;
     RECT  2.16 30.105 41.04 30.375 ;
     RECT  2.16 30.645 41.04 30.915 ;
     RECT  2.16 31.185 41.04 31.455 ;
     RECT  2.16 31.725 41.04 31.995 ;
     RECT  2.16 32.265 41.04 32.535 ;
     RECT  2.16 32.805 41.04 33.075 ;
     RECT  2.16 33.345 41.04 33.615 ;
     RECT  2.16 33.885 41.04 34.155 ;
     RECT  2.16 34.425 41.04 34.695 ;
     RECT  2.16 34.965 41.04 35.235 ;
     RECT  2.16 35.505 41.04 35.775 ;
     RECT  2.16 36.045 41.04 36.315 ;
     RECT  2.16 36.585 41.04 36.855 ;
     RECT  2.16 37.125 41.04 37.395 ;
     RECT  2.16 37.665 41.04 37.935 ;
     RECT  2.16 38.205 41.04 38.475 ;
     RECT  2.16 38.745 41.04 39.015 ;
     RECT  2.16 39.285 41.04 39.555 ;
     RECT  2.16 39.825 41.04 40.095 ;
     RECT  2.16 40.365 41.04 40.635 ;
     RECT  2.16 40.905 41.04 41.04 ;
    LAYER RVTP ;
     RECT  2.16 2.295 41.04 2.565 ;
     RECT  2.16 2.835 41.04 3.105 ;
     RECT  2.16 3.375 41.04 3.645 ;
     RECT  2.16 3.915 41.04 4.185 ;
     RECT  2.16 4.455 41.04 4.725 ;
     RECT  2.16 4.995 41.04 5.265 ;
     RECT  2.16 5.535 41.04 5.805 ;
     RECT  2.16 6.075 41.04 6.345 ;
     RECT  2.16 6.615 41.04 6.885 ;
     RECT  2.16 7.155 41.04 7.425 ;
     RECT  2.16 7.695 41.04 7.965 ;
     RECT  2.16 8.235 41.04 8.505 ;
     RECT  2.16 8.775 41.04 9.045 ;
     RECT  2.16 9.315 41.04 9.585 ;
     RECT  2.16 9.855 41.04 10.125 ;
     RECT  2.16 10.395 41.04 10.665 ;
     RECT  2.16 10.935 41.04 11.205 ;
     RECT  2.16 11.475 41.04 11.745 ;
     RECT  2.16 12.015 41.04 12.285 ;
     RECT  2.16 12.555 41.04 12.825 ;
     RECT  2.16 13.095 41.04 13.365 ;
     RECT  2.16 13.635 41.04 13.905 ;
     RECT  2.16 14.175 41.04 14.445 ;
     RECT  2.16 14.715 41.04 14.985 ;
     RECT  2.16 15.255 41.04 15.525 ;
     RECT  2.16 15.795 41.04 16.065 ;
     RECT  2.16 16.335 41.04 16.605 ;
     RECT  2.16 16.875 41.04 17.145 ;
     RECT  2.16 17.415 41.04 17.685 ;
     RECT  2.16 17.955 41.04 18.225 ;
     RECT  2.16 18.495 41.04 18.765 ;
     RECT  2.16 19.035 41.04 19.305 ;
     RECT  2.16 19.575 41.04 19.845 ;
     RECT  2.16 20.115 41.04 20.385 ;
     RECT  2.16 20.655 41.04 20.925 ;
     RECT  2.16 21.195 41.04 21.465 ;
     RECT  2.16 21.735 41.04 22.005 ;
     RECT  2.16 22.275 41.04 22.545 ;
     RECT  2.16 22.815 41.04 23.085 ;
     RECT  2.16 23.355 41.04 23.625 ;
     RECT  2.16 23.895 41.04 24.165 ;
     RECT  2.16 24.435 41.04 24.705 ;
     RECT  2.16 24.975 41.04 25.245 ;
     RECT  2.16 25.515 41.04 25.785 ;
     RECT  2.16 26.055 41.04 26.325 ;
     RECT  2.16 26.595 41.04 26.865 ;
     RECT  2.16 27.135 41.04 27.405 ;
     RECT  2.16 27.675 41.04 27.945 ;
     RECT  2.16 28.215 41.04 28.485 ;
     RECT  2.16 28.755 41.04 29.025 ;
     RECT  2.16 29.295 41.04 29.565 ;
     RECT  2.16 29.835 41.04 30.105 ;
     RECT  2.16 30.375 41.04 30.645 ;
     RECT  2.16 30.915 41.04 31.185 ;
     RECT  2.16 31.455 41.04 31.725 ;
     RECT  2.16 31.995 41.04 32.265 ;
     RECT  2.16 32.535 41.04 32.805 ;
     RECT  2.16 33.075 41.04 33.345 ;
     RECT  2.16 33.615 41.04 33.885 ;
     RECT  2.16 34.155 41.04 34.425 ;
     RECT  2.16 34.695 41.04 34.965 ;
     RECT  2.16 35.235 41.04 35.505 ;
     RECT  2.16 35.775 41.04 36.045 ;
     RECT  2.16 36.315 41.04 36.585 ;
     RECT  2.16 36.855 41.04 37.125 ;
     RECT  2.16 37.395 41.04 37.665 ;
     RECT  2.16 37.935 41.04 38.205 ;
     RECT  2.16 38.475 41.04 38.745 ;
     RECT  2.16 39.015 41.04 39.285 ;
     RECT  2.16 39.555 41.04 39.825 ;
     RECT  2.16 40.095 41.04 40.365 ;
     RECT  2.16 40.635 41.04 40.905 ;
    LAYER M1 ;
     RECT  2.16 2.151 41.04 41.049 ;
    LAYER M2 ;
     RECT  0.103 22.131 0.139 22.608 ;
     RECT  0.103 13.41 0.175 13.428 ;
     RECT  0.103 23.832 0.175 23.85 ;
     RECT  0.103 17.082 0.203 17.1 ;
     RECT  0.211 18.576 0.347 18.594 ;
     RECT  0.139 22.131 0.347 22.77 ;
     RECT  0.211 34.056 0.383 34.074 ;
     RECT  0.175 12.87 0.535 13.428 ;
     RECT  0.103 14.76 0.535 14.778 ;
     RECT  0.347 22.59 0.535 22.77 ;
     RECT  0.175 23.832 0.535 24.498 ;
     RECT  0.211 25.56 0.535 25.578 ;
     RECT  0.535 33.858 1.147 33.876 ;
     RECT  1.147 33.858 1.175 34.182 ;
     RECT  1.687 32.004 2.119 32.022 ;
     RECT  0.535 11.178 2.16 11.196 ;
     RECT  0.535 12.834 2.16 13.428 ;
     RECT  0.535 14.22 2.16 14.778 ;
     RECT  0.103 19.89 2.16 19.908 ;
     RECT  0.535 22.59 2.16 25.578 ;
     RECT  0.103 29.034 2.16 29.628 ;
     RECT  2.119 32.004 2.16 32.292 ;
     RECT  0.535 33.048 2.16 33.066 ;
     RECT  1.175 34.164 2.16 34.182 ;
     RECT  0.103 36.792 2.16 36.81 ;
     RECT  2.16 2.151 9.535 41.049 ;
     RECT  9.535 2.07 11.191 41.049 ;
     RECT  11.191 1.926 13.307 41.049 ;
     RECT  13.307 1.998 13.451 41.049 ;
     RECT  13.451 2.106 14.647 41.049 ;
     RECT  14.647 2.07 15.475 41.049 ;
     RECT  15.475 1.998 17.095 41.049 ;
     RECT  15.223 0.531 17.447 0.549 ;
     RECT  17.095 1.926 17.671 41.049 ;
     RECT  17.671 1.881 18.815 41.049 ;
     RECT  18.815 1.926 20.435 41.049 ;
     RECT  20.435 2.151 41.04 41.049 ;
     RECT  41.04 27.342 41.639 40.194 ;
     RECT  41.639 27.342 42.107 39.474 ;
     RECT  42.107 27.342 42.143 27.864 ;
     RECT  42.143 27.342 42.179 27.774 ;
     RECT  42.107 29.196 42.179 39.474 ;
     RECT  42.179 29.196 42.215 33.642 ;
     RECT  42.179 34.776 42.215 39.474 ;
     RECT  42.215 29.196 42.251 29.826 ;
     RECT  42.215 30.816 42.251 32.796 ;
     RECT  42.251 29.196 42.287 29.754 ;
     RECT  42.215 34.776 42.287 38.844 ;
     RECT  42.251 30.816 42.323 32.526 ;
     RECT  42.287 29.196 43.007 29.664 ;
     RECT  42.287 34.776 43.015 37.584 ;
     RECT  42.287 38.754 43.015 38.844 ;
     RECT  42.323 31.23 43.051 32.526 ;
     RECT  43.015 34.776 43.051 38.844 ;
     RECT  42.215 33.588 43.079 33.642 ;
     RECT  43.051 34.776 43.079 39.429 ;
     RECT  43.007 29.376 43.115 29.664 ;
     RECT  43.051 30.852 43.115 32.526 ;
     RECT  43.079 33.624 43.115 33.642 ;
     RECT  43.079 35.514 43.115 39.429 ;
     RECT  43.115 29.646 43.151 29.664 ;
     RECT  43.115 30.852 43.151 31.446 ;
     RECT  43.115 36.936 43.151 36.954 ;
     RECT  43.115 39.411 43.151 39.429 ;
     RECT  42.179 27.342 43.187 27.36 ;
     RECT  43.151 31.428 43.187 31.446 ;
     RECT  43.087 41.616 43.187 41.634 ;
    LAYER M3 ;
     RECT  10.692 0.043 10.71 0.091 ;
     RECT  13.752 0.043 13.77 0.091 ;
     RECT  15.48 0.043 15.498 0.091 ;
     RECT  19.764 0.043 19.782 0.091 ;
     RECT  9.972 0.091 11.142 0.139 ;
     RECT  13.104 0.091 14.274 0.139 ;
     RECT  15.408 0.091 15.93 0.139 ;
     RECT  19.764 0.091 20.214 0.139 ;
     RECT  19.44 0.139 20.214 0.187 ;
     RECT  13.104 0.139 15.93 0.269 ;
     RECT  9.576 0.139 11.142 0.475 ;
     RECT  9.576 0.475 11.61 0.571 ;
     RECT  13.104 0.269 13.95 0.571 ;
     RECT  9.576 0.571 13.95 1.147 ;
     RECT  14.868 0.269 15.93 1.147 ;
     RECT  17.424 0.526 17.442 1.723 ;
     RECT  17.424 1.723 17.694 1.771 ;
     RECT  9.576 1.147 15.93 1.819 ;
     RECT  16.992 1.771 17.694 1.819 ;
     RECT  18.936 0.187 20.214 1.876 ;
     RECT  18.792 1.876 20.214 1.921 ;
     RECT  9.576 1.819 17.694 1.993 ;
     RECT  18.792 1.921 20.43 1.993 ;
     RECT  9.576 1.993 20.43 2.065 ;
     RECT  9.54 2.065 20.43 2.219 ;
     RECT  2.415 2.143 2.505 2.413 ;
     RECT  7.815 2.143 7.905 2.413 ;
     RECT  24.015 2.143 24.105 2.413 ;
     RECT  29.415 2.143 29.505 2.413 ;
     RECT  34.815 2.143 34.905 2.413 ;
     RECT  40.215 2.143 40.305 2.413 ;
     RECT  9.54 2.219 20.214 2.461 ;
     RECT  9.144 2.461 20.214 2.525 ;
     RECT  9.144 2.525 9.162 2.795 ;
     RECT  9.9 2.525 20.214 3.181 ;
     RECT  9.9 3.181 20.322 3.451 ;
     RECT  22.824 3.547 22.842 3.677 ;
     RECT  9.684 3.451 20.322 3.839 ;
     RECT  9.792 3.839 20.322 3.911 ;
     RECT  25.2 3.643 25.218 4.261 ;
     RECT  10.008 3.911 20.322 4.415 ;
     RECT  24.015 2.413 24.297 4.651 ;
     RECT  25.092 4.261 25.218 4.651 ;
     RECT  10.008 4.415 19.278 4.729 ;
     RECT  24.015 4.651 25.218 4.747 ;
     RECT  26.1 4.531 26.118 4.747 ;
     RECT  22.824 4.891 22.842 5.021 ;
     RECT  9.468 4.729 19.278 5.035 ;
     RECT  9.324 5.035 19.278 5.117 ;
     RECT  9.828 5.117 19.278 5.369 ;
     RECT  9.936 5.369 19.278 5.701 ;
     RECT  20.304 4.415 20.322 5.845 ;
     RECT  24.015 4.747 26.118 5.881 ;
     RECT  9.936 5.701 19.35 6.151 ;
     RECT  22.824 6.043 22.842 6.173 ;
     RECT  9.324 6.151 19.35 6.235 ;
     RECT  9.18 6.235 19.35 6.269 ;
     RECT  9.18 6.269 19.278 6.275 ;
     RECT  9.504 6.275 19.278 7.051 ;
     RECT  9.216 7.051 19.278 7.231 ;
     RECT  20.088 5.845 20.322 7.231 ;
     RECT  7.815 2.413 8.097 8.041 ;
     RECT  9.108 7.231 20.322 8.041 ;
     RECT  7.815 8.041 20.322 8.477 ;
     RECT  7.815 8.477 8.226 9.517 ;
     RECT  9 8.477 20.322 9.517 ;
     RECT  4.644 10.165 4.662 10.201 ;
     RECT  4.608 10.201 4.662 10.291 ;
     RECT  3.96 10.291 4.662 10.315 ;
     RECT  5.688 10.291 5.706 10.315 ;
     RECT  7.815 9.517 20.322 10.391 ;
     RECT  7.815 10.391 13.497 10.399 ;
     RECT  3.96 10.315 5.706 10.435 ;
     RECT  14.292 10.391 20.322 10.589 ;
     RECT  2.415 2.413 2.697 10.597 ;
     RECT  3.42 10.435 5.706 10.597 ;
     RECT  16.056 10.589 20.322 10.625 ;
     RECT  14.292 10.589 15.102 10.637 ;
     RECT  7.416 10.399 13.497 10.733 ;
     RECT  2.415 10.597 5.706 10.741 ;
     RECT  2.415 10.741 5.886 10.831 ;
     RECT  6.66 10.741 6.678 10.831 ;
     RECT  7.416 10.733 11.43 10.831 ;
     RECT  16.092 10.625 20.322 10.831 ;
     RECT  22.824 8.041 22.842 10.831 ;
     RECT  22.824 10.831 22.986 10.859 ;
     RECT  2.415 10.831 11.43 10.975 ;
     RECT  0.144 11.035 0.162 11.083 ;
     RECT  12.564 10.733 13.497 11.129 ;
     RECT  0.144 11.083 0.342 11.173 ;
     RECT  0.144 11.173 0.558 11.213 ;
     RECT  2.34 10.975 11.43 11.245 ;
     RECT  2.268 11.245 11.43 11.405 ;
     RECT  0.54 11.213 0.558 11.981 ;
     RECT  22.968 10.859 22.986 12.181 ;
     RECT  16.092 10.831 20.394 12.209 ;
     RECT  2.304 11.405 11.43 12.427 ;
     RECT  0.324 12.715 0.342 12.829 ;
     RECT  0.324 12.829 0.558 12.865 ;
     RECT  16.128 12.209 20.394 12.865 ;
     RECT  16.128 12.865 20.61 12.901 ;
     RECT  22.32 12.181 22.986 12.901 ;
     RECT  2.268 12.427 11.43 13.037 ;
     RECT  16.128 12.901 20.682 13.063 ;
     RECT  21.456 9.823 21.474 13.063 ;
     RECT  16.128 13.063 21.474 13.171 ;
     RECT  22.32 12.901 23.166 13.171 ;
     RECT  0.18 12.865 0.558 13.325 ;
     RECT  0.18 13.325 0.522 13.405 ;
     RECT  24.015 5.881 26.19 13.441 ;
     RECT  16.128 13.171 23.166 13.567 ;
     RECT  23.94 13.441 26.19 13.567 ;
     RECT  14.58 10.637 15.102 13.901 ;
     RECT  2.304 13.037 11.43 13.981 ;
     RECT  16.128 13.567 26.19 14.099 ;
     RECT  2.304 13.981 11.466 14.107 ;
     RECT  0.108 13.405 0.522 14.215 ;
     RECT  2.304 14.107 11.682 14.485 ;
     RECT  0.108 14.215 0.558 14.573 ;
     RECT  13.215 11.129 13.497 14.719 ;
     RECT  0.108 14.573 0.126 14.957 ;
     RECT  16.2 14.099 26.19 15.025 ;
     RECT  2.304 14.485 11.934 15.115 ;
     RECT  2.268 15.115 11.934 15.287 ;
     RECT  0.18 15.547 0.198 15.691 ;
     RECT  15.084 13.901 15.102 15.727 ;
     RECT  15.984 15.025 26.19 15.727 ;
     RECT  0.18 15.691 0.342 15.821 ;
     RECT  15.084 15.727 26.19 15.961 ;
     RECT  2.304 15.287 11.934 16.141 ;
     RECT  14.796 15.961 26.19 16.141 ;
     RECT  14.796 16.141 26.262 16.537 ;
     RECT  0.18 15.821 0.198 16.555 ;
     RECT  14.724 16.537 26.262 16.609 ;
     RECT  12.816 14.719 13.497 16.651 ;
     RECT  2.268 16.141 11.934 16.681 ;
     RECT  2.196 16.681 11.934 16.733 ;
     RECT  14.724 16.609 26.838 16.877 ;
     RECT  2.268 16.733 11.934 16.915 ;
     RECT  12.816 16.651 13.986 16.915 ;
     RECT  2.268 16.915 13.986 16.943 ;
     RECT  0.144 16.555 0.198 17.068 ;
     RECT  15.156 16.877 26.838 17.113 ;
     RECT  15.156 17.113 27.09 17.149 ;
     RECT  0.108 17.068 0.198 17.213 ;
     RECT  0.108 17.213 0.126 17.261 ;
     RECT  29.415 2.413 29.697 17.311 ;
     RECT  15.156 17.149 27.522 17.491 ;
     RECT  15.156 17.491 27.558 17.617 ;
     RECT  15.156 17.617 27.594 17.761 ;
     RECT  14.832 17.761 27.594 17.887 ;
     RECT  2.304 16.943 13.986 18.091 ;
     RECT  14.724 17.887 27.594 18.091 ;
     RECT  2.304 18.091 27.594 18.301 ;
     RECT  0.324 18.379 0.342 18.475 ;
     RECT  0.216 18.475 0.342 18.599 ;
     RECT  2.304 18.301 28.134 18.697 ;
     RECT  29.415 17.311 30.33 18.697 ;
     RECT  2.304 18.697 28.242 18.733 ;
     RECT  29.052 18.697 30.33 18.733 ;
     RECT  2.304 18.733 30.33 18.841 ;
     RECT  0.324 18.599 0.342 19.085 ;
     RECT  2.268 18.841 30.33 19.111 ;
     RECT  2.268 19.111 30.798 19.273 ;
     RECT  0.252 19.435 0.27 19.531 ;
     RECT  0.144 19.531 0.27 19.613 ;
     RECT  0.144 19.613 0.162 19.709 ;
     RECT  2.232 19.273 30.798 19.885 ;
     RECT  31.572 19.849 31.59 19.885 ;
     RECT  2.232 19.885 31.59 20.011 ;
     RECT  0.108 19.885 0.126 20.045 ;
     RECT  2.232 20.011 31.734 20.219 ;
     RECT  2.304 20.219 31.734 20.281 ;
     RECT  33.444 20.623 33.462 20.695 ;
     RECT  2.304 20.281 32.418 20.731 ;
     RECT  33.444 20.695 33.606 20.731 ;
     RECT  34.815 2.413 35.097 20.731 ;
     RECT  2.304 20.731 35.097 21.541 ;
     RECT  2.304 21.541 35.622 21.659 ;
     RECT  0.324 21.451 0.342 21.739 ;
     RECT  0.144 21.739 0.342 22.027 ;
     RECT  0.108 22.027 0.342 22.157 ;
     RECT  2.304 21.659 35.097 22.699 ;
     RECT  2.232 22.699 35.097 22.847 ;
     RECT  2.232 22.847 30.582 22.883 ;
     RECT  0.108 22.157 0.162 22.925 ;
     RECT  0.144 22.925 0.162 23.021 ;
     RECT  31.32 22.847 35.097 23.359 ;
     RECT  31.32 23.359 35.226 23.431 ;
     RECT  36 23.251 36.018 23.431 ;
     RECT  2.268 22.883 30.582 23.585 ;
     RECT  2.304 23.585 30.582 23.593 ;
     RECT  31.32 23.431 36.018 23.593 ;
     RECT  2.304 23.593 36.018 23.819 ;
     RECT  0.54 23.323 0.558 23.827 ;
     RECT  2.304 23.819 35.946 23.855 ;
     RECT  2.304 23.855 35.874 24.629 ;
     RECT  27.72 24.629 35.874 24.665 ;
     RECT  27.792 24.665 35.874 24.701 ;
     RECT  27.828 24.701 35.874 24.781 ;
     RECT  27.828 24.781 35.982 24.935 ;
     RECT  0.108 23.827 0.558 24.941 ;
     RECT  27.828 24.935 35.226 25.007 ;
     RECT  35.964 24.935 35.982 25.007 ;
     RECT  0.18 24.941 0.558 25.037 ;
     RECT  34.632 25.007 35.226 25.169 ;
     RECT  2.304 24.629 26.874 25.339 ;
     RECT  2.232 25.339 26.874 25.411 ;
     RECT  2.232 25.411 26.946 25.591 ;
     RECT  27.828 25.007 33.858 25.591 ;
     RECT  0.216 25.037 0.558 25.613 ;
     RECT  2.232 25.591 33.858 25.817 ;
     RECT  0.216 25.613 0.234 25.867 ;
     RECT  2.304 25.817 33.858 26.257 ;
     RECT  34.632 25.169 35.097 26.257 ;
     RECT  2.304 26.257 35.097 26.789 ;
     RECT  0.144 25.867 0.234 27.053 ;
     RECT  0.144 27.053 0.162 27.101 ;
     RECT  2.304 26.789 26.406 27.571 ;
     RECT  27.216 26.789 35.097 27.571 ;
     RECT  40.215 2.413 40.497 27.715 ;
     RECT  42.156 27.751 42.174 27.841 ;
     RECT  42.12 27.841 42.174 27.877 ;
     RECT  40.104 27.715 40.497 27.913 ;
     RECT  41.616 27.877 42.174 27.913 ;
     RECT  2.304 27.571 35.097 28.255 ;
     RECT  2.304 28.255 35.19 28.291 ;
     RECT  40.104 27.913 42.174 28.381 ;
     RECT  39.996 28.381 42.174 28.417 ;
     RECT  39.888 28.417 42.174 28.453 ;
     RECT  2.304 28.291 35.622 28.481 ;
     RECT  0.432 28.555 0.45 28.651 ;
     RECT  0.36 28.651 0.45 28.733 ;
     RECT  0.36 28.733 0.378 28.747 ;
     RECT  0.144 28.747 0.378 28.781 ;
     RECT  39.384 28.453 42.174 28.795 ;
     RECT  0.144 28.781 0.162 29.029 ;
     RECT  0.108 29.029 0.162 29.03 ;
     RECT  39.24 28.795 42.174 29.191 ;
     RECT  43.164 27.337 43.182 29.191 ;
     RECT  1.26 29.131 1.278 29.227 ;
     RECT  2.304 28.481 35.262 29.227 ;
     RECT  1.152 29.227 1.278 29.261 ;
     RECT  1.152 29.261 1.17 29.357 ;
     RECT  36.252 29.335 36.522 29.371 ;
     RECT  37.764 29.101 37.782 29.371 ;
     RECT  36.252 29.371 36.702 29.461 ;
     RECT  37.476 29.371 37.782 29.461 ;
     RECT  36.252 29.461 37.782 29.569 ;
     RECT  39.096 29.191 42.174 29.569 ;
     RECT  2.304 29.227 35.298 29.605 ;
     RECT  36.252 29.569 42.174 29.605 ;
     RECT  2.304 29.605 42.174 29.731 ;
     RECT  42.984 29.191 43.182 29.731 ;
     RECT  0.108 29.03 0.126 29.741 ;
     RECT  2.304 29.731 43.182 29.759 ;
     RECT  2.304 29.759 35.478 30.091 ;
     RECT  2.268 30.091 35.478 30.187 ;
     RECT  1.692 30.187 35.478 30.335 ;
     RECT  0.18 30.283 0.342 30.701 ;
     RECT  29.124 30.335 35.478 30.721 ;
     RECT  36.252 29.759 43.182 30.721 ;
     RECT  1.692 30.335 28.242 30.749 ;
     RECT  29.124 30.721 43.182 30.749 ;
     RECT  0.216 30.701 0.234 30.941 ;
     RECT  29.124 30.749 41.31 31.379 ;
     RECT  42.084 30.749 43.182 31.451 ;
     RECT  29.16 31.379 41.31 31.523 ;
     RECT  29.415 31.523 41.31 31.531 ;
     RECT  42.084 31.451 43.11 31.531 ;
     RECT  29.415 31.531 43.11 31.757 ;
     RECT  29.415 31.757 41.31 31.919 ;
     RECT  1.692 30.749 28.206 32.027 ;
     RECT  0.108 32.011 0.126 32.107 ;
     RECT  0.108 32.107 0.342 32.237 ;
     RECT  2.124 32.027 28.206 32.297 ;
     RECT  42.192 31.757 43.11 32.531 ;
     RECT  2.232 32.297 28.206 32.539 ;
     RECT  2.232 32.539 28.602 32.567 ;
     RECT  42.192 32.531 43.074 32.621 ;
     RECT  42.192 32.621 42.93 32.717 ;
     RECT  30.42 31.919 41.31 32.765 ;
     RECT  30.528 32.765 41.31 32.873 ;
     RECT  0.108 32.237 0.162 33.043 ;
     RECT  2.304 32.567 28.602 33.043 ;
     RECT  29.415 31.919 29.697 33.043 ;
     RECT  30.996 32.873 41.31 33.115 ;
     RECT  42.192 32.717 42.246 33.115 ;
     RECT  30.996 33.115 42.246 33.197 ;
     RECT  30.996 33.197 42.21 33.293 ;
     RECT  2.304 33.043 29.697 33.341 ;
     RECT  2.304 33.341 15.21 33.413 ;
     RECT  42.048 33.293 42.21 33.485 ;
     RECT  2.304 33.413 14.994 33.539 ;
     RECT  16.272 33.341 29.697 33.539 ;
     RECT  43.02 33.499 43.038 33.547 ;
     RECT  14.76 33.539 14.994 33.575 ;
     RECT  14.868 33.575 14.994 33.611 ;
     RECT  14.976 33.611 14.994 33.647 ;
     RECT  16.344 33.539 29.697 33.809 ;
     RECT  16.344 33.809 17.658 33.845 ;
     RECT  0.108 33.043 0.558 33.853 ;
     RECT  16.452 33.845 17.658 33.881 ;
     RECT  18.612 33.809 29.697 33.881 ;
     RECT  18.615 33.881 29.697 34.079 ;
     RECT  16.452 33.881 17.118 34.115 ;
     RECT  18.615 34.079 19.962 34.151 ;
     RECT  30.996 33.293 41.022 34.159 ;
     RECT  19.872 34.151 19.89 34.187 ;
     RECT  30.636 34.159 41.022 34.219 ;
     RECT  42.048 33.485 42.174 34.219 ;
     RECT  30.636 34.219 42.174 34.223 ;
     RECT  20.7 34.079 29.697 34.231 ;
     RECT  30.636 34.223 42.138 34.231 ;
     RECT  20.7 34.231 42.138 34.259 ;
     RECT  20.7 34.259 41.598 34.385 ;
     RECT  0.108 33.853 1.17 34.445 ;
     RECT  2.304 33.539 13.986 34.507 ;
     RECT  20.772 34.385 41.598 34.529 ;
     RECT  2.268 34.507 13.986 34.591 ;
     RECT  20.772 34.529 41.022 34.619 ;
     RECT  20.772 34.619 29.79 34.685 ;
     RECT  2.268 34.591 14.274 34.699 ;
     RECT  2.268 34.699 14.634 34.727 ;
     RECT  0.108 34.445 0.342 34.733 ;
     RECT  2.304 34.727 14.634 34.735 ;
     RECT  1.152 34.445 1.17 34.781 ;
     RECT  43.02 33.547 43.11 34.891 ;
     RECT  2.304 34.735 15.318 34.933 ;
     RECT  43.02 34.891 43.182 35.227 ;
     RECT  42.732 35.227 43.182 35.239 ;
     RECT  2.304 34.933 15.678 35.311 ;
     RECT  16.452 34.115 16.902 35.311 ;
     RECT  2.304 35.311 17.37 35.401 ;
     RECT  18.615 34.151 18.897 35.401 ;
     RECT  2.304 35.401 17.586 35.464 ;
     RECT  18.615 35.401 19.134 35.473 ;
     RECT  30.708 34.619 41.022 35.473 ;
     RECT  42.156 35.239 43.182 35.473 ;
     RECT  0.108 34.733 0.126 35.515 ;
     RECT  2.304 35.464 17.658 35.563 ;
     RECT  2.268 35.563 17.658 35.581 ;
     RECT  18.432 35.473 19.134 35.581 ;
     RECT  30.708 35.473 43.182 35.693 ;
     RECT  2.268 35.581 19.134 35.779 ;
     RECT  19.98 35.437 19.998 35.779 ;
     RECT  2.268 35.779 19.998 35.803 ;
     RECT  20.772 34.685 29.697 35.803 ;
     RECT  0.108 35.515 0.162 35.885 ;
     RECT  30.708 35.693 41.022 35.981 ;
     RECT  30.708 35.981 40.842 36.005 ;
     RECT  2.268 35.803 29.697 36.239 ;
     RECT  42.156 35.693 43.182 36.619 ;
     RECT  2.304 36.239 29.697 36.653 ;
     RECT  0.108 35.885 0.126 36.815 ;
     RECT  2.34 36.653 29.697 37.021 ;
     RECT  30.708 36.005 40.77 37.049 ;
     RECT  2.34 37.021 29.754 37.085 ;
     RECT  42.048 36.619 43.182 37.093 ;
     RECT  2.376 37.085 29.754 37.099 ;
     RECT  30.708 37.049 40.734 37.099 ;
     RECT  2.376 37.099 40.734 37.157 ;
     RECT  9.36 37.157 40.734 37.193 ;
     RECT  9.54 37.193 40.734 37.229 ;
     RECT  2.376 37.157 8.097 37.355 ;
     RECT  9.54 37.229 9.558 37.391 ;
     RECT  10.296 37.229 40.734 37.463 ;
     RECT  2.412 37.355 8.097 37.589 ;
     RECT  2.412 37.589 6.822 37.859 ;
     RECT  4.788 37.859 5.886 37.895 ;
     RECT  2.412 37.859 2.697 37.904 ;
     RECT  21.744 37.463 40.734 37.915 ;
     RECT  41.616 37.093 43.182 37.915 ;
     RECT  4.788 37.895 5.742 38.003 ;
     RECT  3.42 37.859 3.978 38.093 ;
     RECT  3.42 38.093 3.942 38.129 ;
     RECT  4.788 38.003 4.878 38.129 ;
     RECT  5.724 38.003 5.742 38.129 ;
     RECT  3.924 38.129 3.942 38.201 ;
     RECT  10.296 37.463 20.826 38.281 ;
     RECT  21.744 37.915 43.182 38.281 ;
     RECT  10.296 38.281 43.182 38.399 ;
     RECT  10.296 38.399 20.826 38.939 ;
     RECT  21.6 38.399 43.182 39.209 ;
     RECT  10.296 38.939 20.502 39.355 ;
     RECT  22.32 39.209 43.182 39.515 ;
     RECT  10.08 39.355 20.502 39.785 ;
     RECT  22.5 39.515 43.182 39.785 ;
     RECT  22.716 39.785 43.182 40.205 ;
     RECT  22.716 40.205 42.102 40.253 ;
     RECT  22.716 40.253 41.886 40.493 ;
     RECT  22.716 40.493 40.914 40.739 ;
     RECT  2.415 37.904 2.697 40.787 ;
     RECT  7.815 37.589 8.097 40.787 ;
     RECT  10.44 39.785 20.502 40.829 ;
     RECT  22.716 40.739 33.354 40.829 ;
     RECT  34.128 40.739 40.914 40.829 ;
     RECT  10.44 40.829 15.642 40.865 ;
     RECT  19.944 40.829 19.998 40.865 ;
     RECT  38.124 40.829 39.042 40.877 ;
     RECT  19.98 40.865 19.998 40.901 ;
     RECT  23.436 40.829 33.354 40.901 ;
     RECT  23.688 40.901 28.638 40.925 ;
     RECT  10.44 40.865 11.142 40.945 ;
     RECT  16.524 40.829 18.774 40.973 ;
     RECT  23.688 40.925 28.53 40.973 ;
     RECT  34.272 40.829 37.35 40.973 ;
     RECT  38.196 40.877 38.898 40.973 ;
     RECT  40.215 40.829 40.914 40.973 ;
     RECT  29.415 40.901 33.354 40.979 ;
     RECT  10.332 40.945 11.142 41.009 ;
     RECT  11.916 40.865 15.642 41.009 ;
     RECT  16.524 40.973 17.622 41.009 ;
     RECT  23.688 40.973 27.162 41.009 ;
     RECT  28.404 40.973 28.53 41.009 ;
     RECT  35.892 40.973 37.35 41.009 ;
     RECT  17.208 41.009 17.226 41.021 ;
     RECT  28.512 41.009 28.53 41.021 ;
     RECT  29.415 40.979 33.102 41.021 ;
     RECT  2.415 40.787 2.505 41.057 ;
     RECT  7.815 40.787 7.905 41.057 ;
     RECT  18.615 40.973 18.705 41.057 ;
     RECT  29.415 41.021 32.85 41.057 ;
     RECT  34.815 40.973 34.905 41.057 ;
     RECT  40.215 40.973 40.806 41.057 ;
     RECT  10.332 41.009 10.71 41.069 ;
     RECT  13.176 41.009 15.282 41.069 ;
     RECT  11.916 41.009 11.934 41.117 ;
     RECT  13.176 41.069 14.274 41.165 ;
     RECT  35.892 41.009 37.314 41.165 ;
     RECT  13.176 41.165 13.194 41.213 ;
     RECT  35.892 41.165 35.91 41.261 ;
     RECT  36.756 41.165 37.314 41.357 ;
     RECT  40.788 41.057 40.806 41.549 ;
     RECT  42.876 40.205 43.182 41.639 ;
     RECT  30.096 41.057 32.85 41.645 ;
     RECT  42.876 41.639 43.11 41.648 ;
     RECT  42.876 41.648 42.93 41.741 ;
     RECT  36.756 41.357 37.17 41.837 ;
     RECT  36.756 41.837 36.774 41.933 ;
     RECT  42.876 41.741 42.894 42.029 ;
     RECT  41.868 40.493 41.886 42.125 ;
     RECT  14.256 41.165 14.274 42.173 ;
     RECT  23.76 41.009 27.162 42.173 ;
     RECT  30.096 41.645 31.266 42.173 ;
     RECT  10.332 41.069 10.638 42.221 ;
     RECT  23.76 42.173 26.082 42.221 ;
     RECT  32.472 41.645 32.85 42.221 ;
     RECT  32.616 42.221 32.85 42.269 ;
     RECT  23.796 42.221 23.814 42.317 ;
     RECT  30.636 42.173 31.266 42.797 ;
     RECT  27.072 42.173 27.162 43.037 ;
     RECT  10.62 42.221 10.638 43.085 ;
     RECT  15.264 41.069 15.282 43.085 ;
     RECT  24.984 42.221 26.082 43.085 ;
     RECT  27.144 43.037 27.162 43.085 ;
     RECT  30.636 42.797 31.158 43.085 ;
     RECT  32.688 42.269 32.85 43.085 ;
     RECT  22.644 40.981 22.662 43.181 ;
     RECT  25.2 43.085 25.218 43.181 ;
    LAYER M4 ;
     RECT  0.084 10.992 2.408 11.016 ;
     RECT  0.06 11.016 2.408 11.088 ;
     RECT  0.084 11.088 2.408 11.112 ;
     RECT  0.06 11.112 2.408 11.184 ;
     RECT  0.084 11.184 2.408 11.208 ;
     RECT  0.06 11.208 2.408 11.28 ;
     RECT  0.084 11.28 2.408 11.304 ;
     RECT  0.06 11.304 2.408 11.376 ;
     RECT  0.084 11.376 2.408 11.4 ;
     RECT  0.06 11.4 2.408 11.472 ;
     RECT  0.084 11.472 2.408 11.496 ;
     RECT  0.06 11.496 2.408 11.568 ;
     RECT  0.084 11.568 2.408 11.592 ;
     RECT  0.06 11.592 2.408 11.664 ;
     RECT  0.084 11.664 2.408 11.688 ;
     RECT  0.06 11.688 2.408 11.76 ;
     RECT  0.084 11.76 2.408 11.784 ;
     RECT  0.06 11.784 2.408 11.856 ;
     RECT  0.084 11.856 2.408 11.88 ;
     RECT  0.06 11.88 2.408 11.952 ;
     RECT  0.084 11.952 2.408 11.976 ;
     RECT  0.06 11.976 2.408 12.048 ;
     RECT  0.084 12.048 2.408 12.072 ;
     RECT  0.06 12.072 2.408 12.144 ;
     RECT  0.084 12.144 2.408 12.168 ;
     RECT  0.06 12.168 2.408 12.24 ;
     RECT  0.084 12.24 2.408 12.264 ;
     RECT  0.06 12.264 2.408 12.336 ;
     RECT  0.084 12.336 2.408 12.36 ;
     RECT  0.06 12.36 2.408 12.432 ;
     RECT  0.084 12.432 2.408 12.456 ;
     RECT  0.06 12.456 2.408 12.528 ;
     RECT  0.084 12.528 2.408 12.552 ;
     RECT  0.06 12.552 2.408 12.624 ;
     RECT  0.084 12.624 2.408 12.648 ;
     RECT  0.06 12.648 2.408 12.72 ;
     RECT  0.084 12.72 2.408 12.744 ;
     RECT  0.06 12.744 2.408 12.816 ;
     RECT  0.084 12.816 2.408 12.84 ;
     RECT  0.06 12.84 2.408 12.912 ;
     RECT  0.084 12.912 2.408 12.936 ;
     RECT  0.06 12.936 2.408 13.008 ;
     RECT  0.084 13.008 2.408 13.032 ;
     RECT  0.06 13.032 2.408 13.104 ;
     RECT  0.084 13.104 2.408 13.128 ;
     RECT  0.06 13.128 2.408 13.2 ;
     RECT  0.084 13.2 2.408 13.224 ;
     RECT  0.06 13.224 2.408 13.296 ;
     RECT  0.084 13.296 2.408 13.32 ;
     RECT  0.06 13.32 2.408 13.392 ;
     RECT  0.084 13.392 2.408 13.416 ;
     RECT  0.06 13.416 2.408 13.488 ;
     RECT  0.084 13.488 2.408 13.512 ;
     RECT  0.06 13.512 2.408 13.584 ;
     RECT  0.084 13.584 2.408 13.608 ;
     RECT  0.06 13.608 2.408 13.68 ;
     RECT  0.084 13.68 2.408 13.704 ;
     RECT  0.06 13.704 2.408 13.776 ;
     RECT  0.084 13.776 2.408 13.8 ;
     RECT  0.06 13.8 2.408 13.872 ;
     RECT  0.084 13.872 2.408 13.896 ;
     RECT  0.06 13.896 2.408 13.968 ;
     RECT  0.084 13.968 2.408 13.992 ;
     RECT  0.06 13.992 2.408 14.064 ;
     RECT  0.084 14.064 2.408 14.088 ;
     RECT  0.06 14.088 2.408 14.16 ;
     RECT  0.084 14.16 2.408 14.184 ;
     RECT  0.06 14.184 2.408 14.256 ;
     RECT  0.084 14.256 2.408 14.28 ;
     RECT  0.06 14.28 2.408 14.352 ;
     RECT  0.084 14.352 2.408 14.376 ;
     RECT  0.06 14.376 2.408 14.448 ;
     RECT  0.084 14.448 2.408 14.472 ;
     RECT  0.06 14.472 2.408 14.544 ;
     RECT  0.084 14.544 2.408 14.568 ;
     RECT  0.06 14.568 2.408 14.64 ;
     RECT  0.084 14.64 2.408 14.664 ;
     RECT  0.06 14.664 2.408 14.736 ;
     RECT  0.084 14.736 2.408 14.76 ;
     RECT  0.06 14.76 2.408 14.832 ;
     RECT  0.084 14.832 2.408 14.856 ;
     RECT  0.06 14.856 2.408 14.928 ;
     RECT  0.084 14.928 2.408 14.952 ;
     RECT  0.06 14.952 2.408 15.024 ;
     RECT  0.084 15.024 2.408 15.048 ;
     RECT  0.06 15.048 2.408 15.12 ;
     RECT  0.084 15.12 2.408 15.144 ;
     RECT  0.06 15.144 2.408 15.216 ;
     RECT  0.084 15.216 2.408 15.24 ;
     RECT  0.06 15.24 2.408 15.312 ;
     RECT  0.084 15.312 2.408 15.336 ;
     RECT  0.06 15.336 2.408 15.408 ;
     RECT  0.084 15.408 2.408 15.432 ;
     RECT  0.06 15.432 2.408 15.504 ;
     RECT  0.084 15.504 2.408 15.528 ;
     RECT  0.06 15.528 2.408 15.6 ;
     RECT  0.084 15.6 2.408 15.624 ;
     RECT  0.06 15.624 2.408 15.696 ;
     RECT  0.084 15.696 2.408 15.72 ;
     RECT  0.06 15.72 2.408 15.792 ;
     RECT  0.084 15.792 2.408 15.816 ;
     RECT  0.06 15.816 2.408 15.888 ;
     RECT  0.084 15.888 2.408 15.912 ;
     RECT  0.06 15.912 2.408 15.984 ;
     RECT  0.084 15.984 2.408 16.008 ;
     RECT  0.06 16.008 2.408 16.08 ;
     RECT  0.084 16.08 2.408 16.104 ;
     RECT  0.06 16.104 2.408 16.176 ;
     RECT  0.084 16.176 2.408 16.2 ;
     RECT  0.06 16.2 2.408 16.272 ;
     RECT  0.084 16.272 2.408 16.296 ;
     RECT  0.06 16.296 2.408 16.368 ;
     RECT  0.084 16.368 2.408 16.392 ;
     RECT  0.06 16.392 2.408 16.464 ;
     RECT  0.084 16.464 2.408 16.488 ;
     RECT  0.06 16.488 2.408 16.56 ;
     RECT  0.084 16.56 2.408 16.584 ;
     RECT  0.06 16.584 2.408 16.656 ;
     RECT  0.084 16.656 2.408 16.68 ;
     RECT  0.06 16.68 2.408 16.752 ;
     RECT  0.084 16.752 2.408 16.776 ;
     RECT  0.06 16.776 2.408 16.848 ;
     RECT  0.084 16.848 2.408 16.872 ;
     RECT  0.06 16.872 2.408 16.944 ;
     RECT  0.084 16.944 2.408 16.968 ;
     RECT  0.06 16.968 2.408 17.04 ;
     RECT  0.084 17.04 2.408 17.064 ;
     RECT  0.06 17.064 2.408 17.136 ;
     RECT  0.084 17.136 2.408 17.16 ;
     RECT  0.06 17.16 2.408 17.232 ;
     RECT  0.084 17.232 2.408 17.256 ;
     RECT  0.06 17.256 2.408 17.328 ;
     RECT  0.084 17.328 2.408 17.352 ;
     RECT  0.06 17.352 2.408 17.424 ;
     RECT  0.084 17.424 2.408 17.448 ;
     RECT  0.06 17.448 2.408 17.52 ;
     RECT  0.084 17.52 2.408 17.544 ;
     RECT  0.06 17.544 2.408 17.616 ;
     RECT  0.084 17.616 2.408 17.64 ;
     RECT  0.06 17.64 2.408 17.712 ;
     RECT  0.084 17.712 2.408 17.736 ;
     RECT  0.06 17.736 2.408 17.808 ;
     RECT  0.084 17.808 2.408 17.832 ;
     RECT  0.06 17.832 2.408 17.904 ;
     RECT  0.084 17.904 2.408 17.928 ;
     RECT  0.06 17.928 2.408 18 ;
     RECT  0.084 18 2.408 18.024 ;
     RECT  0.06 18.024 2.408 18.096 ;
     RECT  0.084 18.096 2.408 18.12 ;
     RECT  0.06 18.12 2.408 18.192 ;
     RECT  0.084 18.192 2.408 18.216 ;
     RECT  0.06 18.216 2.408 18.288 ;
     RECT  0.084 18.288 2.408 18.312 ;
     RECT  0.06 18.312 2.408 18.384 ;
     RECT  0.084 18.384 2.408 18.408 ;
     RECT  0.06 18.408 2.408 18.48 ;
     RECT  0.084 18.48 2.408 18.504 ;
     RECT  0.06 18.504 2.408 18.576 ;
     RECT  0.084 18.576 2.408 18.6 ;
     RECT  0.06 18.6 2.408 18.672 ;
     RECT  0.084 18.672 2.408 18.696 ;
     RECT  0.06 18.696 2.408 18.768 ;
     RECT  0.084 18.768 2.408 18.792 ;
     RECT  0.06 18.792 2.408 18.864 ;
     RECT  0.084 18.864 2.408 18.888 ;
     RECT  0.06 18.888 2.408 18.96 ;
     RECT  0.084 18.96 2.408 18.984 ;
     RECT  0.06 18.984 2.408 19.056 ;
     RECT  0.084 19.056 2.408 19.08 ;
     RECT  0.06 19.08 2.408 19.152 ;
     RECT  0.084 19.152 2.408 19.176 ;
     RECT  0.06 19.176 2.408 19.248 ;
     RECT  0.084 19.248 2.408 19.272 ;
     RECT  0.06 19.272 2.408 19.344 ;
     RECT  0.084 19.344 2.408 19.368 ;
     RECT  0.06 19.368 2.408 19.44 ;
     RECT  0.084 19.44 2.408 19.464 ;
     RECT  0.06 19.464 2.408 19.536 ;
     RECT  0.084 19.536 2.408 19.56 ;
     RECT  0.06 19.56 2.408 19.632 ;
     RECT  0.084 19.632 2.408 19.656 ;
     RECT  0.06 19.656 2.408 19.728 ;
     RECT  0.084 19.728 2.408 19.752 ;
     RECT  0.06 19.752 2.408 19.824 ;
     RECT  0.084 19.824 2.408 19.848 ;
     RECT  0.06 19.848 2.408 19.92 ;
     RECT  0.084 19.92 2.408 19.944 ;
     RECT  0.06 19.944 2.408 20.016 ;
     RECT  0.084 20.016 2.408 20.04 ;
     RECT  0.06 20.04 2.408 20.112 ;
     RECT  0.084 20.112 2.408 20.136 ;
     RECT  0.06 20.136 2.408 20.976 ;
     RECT  0.084 20.976 2.408 21 ;
     RECT  0.06 21 2.408 21.072 ;
     RECT  0.084 21.072 2.408 21.096 ;
     RECT  0.06 21.096 2.408 21.168 ;
     RECT  0.084 21.168 2.408 21.192 ;
     RECT  0.06 21.192 2.408 21.264 ;
     RECT  0.084 21.264 2.408 21.288 ;
     RECT  0.06 21.288 2.408 21.36 ;
     RECT  0.084 21.36 2.408 21.384 ;
     RECT  0.06 21.384 2.408 21.456 ;
     RECT  0.084 21.456 2.408 21.48 ;
     RECT  0.06 21.48 2.408 21.552 ;
     RECT  0.084 21.552 2.408 21.576 ;
     RECT  0.06 21.576 2.408 21.648 ;
     RECT  0.084 21.648 2.408 21.672 ;
     RECT  0.06 21.672 2.408 21.744 ;
     RECT  0.084 21.744 2.408 21.768 ;
     RECT  0.06 21.768 2.408 21.84 ;
     RECT  0.084 21.84 2.408 21.864 ;
     RECT  0.06 21.864 2.408 21.936 ;
     RECT  0.084 21.936 2.408 21.96 ;
     RECT  0.06 21.96 2.408 22.032 ;
     RECT  0.084 22.032 2.408 22.056 ;
     RECT  0.06 22.056 2.408 22.128 ;
     RECT  0.084 22.128 2.408 22.152 ;
     RECT  0.06 22.152 2.408 22.224 ;
     RECT  0.084 22.224 2.408 22.248 ;
     RECT  0.06 22.248 2.408 22.32 ;
     RECT  0.084 22.32 2.408 22.344 ;
     RECT  0.06 22.344 2.408 22.416 ;
     RECT  0.084 22.416 2.408 22.44 ;
     RECT  0.06 22.44 2.408 22.512 ;
     RECT  0.084 22.512 2.408 22.536 ;
     RECT  0.06 22.536 2.408 22.608 ;
     RECT  0.084 22.608 2.408 22.632 ;
     RECT  0.06 22.632 2.408 22.704 ;
     RECT  0.084 22.704 2.408 22.728 ;
     RECT  0.06 22.728 2.408 22.8 ;
     RECT  0.084 22.8 2.408 22.824 ;
     RECT  0.06 22.824 2.408 22.896 ;
     RECT  0.084 22.896 2.408 22.92 ;
     RECT  0.06 22.92 2.408 22.992 ;
     RECT  0.084 22.992 2.408 23.016 ;
     RECT  0.06 23.016 2.408 23.088 ;
     RECT  0.084 23.088 2.408 23.112 ;
     RECT  0.06 23.112 2.408 23.184 ;
     RECT  0.084 23.184 2.408 23.208 ;
     RECT  0.06 23.208 2.408 24.048 ;
     RECT  0.084 24.048 2.408 24.072 ;
     RECT  0.06 24.072 2.408 24.144 ;
     RECT  0.084 24.144 2.408 24.168 ;
     RECT  0.06 24.168 2.408 24.24 ;
     RECT  0.084 24.24 2.408 24.264 ;
     RECT  0.06 24.264 2.408 24.336 ;
     RECT  0.084 24.336 2.408 24.36 ;
     RECT  0.06 24.36 2.408 24.432 ;
     RECT  0.084 24.432 2.408 24.456 ;
     RECT  0.06 24.456 2.408 24.528 ;
     RECT  0.084 24.528 2.408 24.552 ;
     RECT  0.06 24.552 2.408 24.624 ;
     RECT  0.084 24.624 2.408 24.648 ;
     RECT  0.06 24.648 2.408 24.72 ;
     RECT  0.084 24.72 2.408 24.744 ;
     RECT  0.06 24.744 2.408 24.816 ;
     RECT  0.084 24.816 2.408 24.84 ;
     RECT  0.06 24.84 2.408 24.912 ;
     RECT  0.084 24.912 2.408 24.936 ;
     RECT  0.06 24.936 2.408 25.008 ;
     RECT  0.084 25.008 2.408 25.032 ;
     RECT  0.06 25.032 2.408 25.104 ;
     RECT  0.084 25.104 2.408 25.128 ;
     RECT  0.06 25.128 2.408 25.2 ;
     RECT  0.084 25.2 2.408 25.224 ;
     RECT  0.06 25.224 2.408 25.296 ;
     RECT  0.084 25.296 2.408 25.32 ;
     RECT  0.06 25.32 2.408 25.392 ;
     RECT  0.084 25.392 2.408 25.416 ;
     RECT  0.06 25.416 2.408 25.488 ;
     RECT  0.084 25.488 2.408 25.512 ;
     RECT  0.06 25.512 2.408 25.584 ;
     RECT  0.084 25.584 2.408 25.608 ;
     RECT  0.06 25.608 2.408 25.68 ;
     RECT  0.084 25.68 2.408 25.704 ;
     RECT  0.06 25.704 2.408 25.776 ;
     RECT  0.084 25.776 2.408 25.8 ;
     RECT  0.06 25.8 2.408 25.872 ;
     RECT  0.084 25.872 2.408 25.896 ;
     RECT  0.06 25.896 2.408 25.968 ;
     RECT  0.084 25.968 2.408 25.992 ;
     RECT  0.06 25.992 2.408 26.064 ;
     RECT  0.084 26.064 2.408 26.088 ;
     RECT  0.06 26.088 2.408 26.16 ;
     RECT  0.084 26.16 2.408 26.184 ;
     RECT  0.06 26.184 2.408 26.256 ;
     RECT  0.084 26.256 2.408 26.28 ;
     RECT  0.06 26.28 2.408 26.352 ;
     RECT  0.084 26.352 2.408 26.376 ;
     RECT  0.06 26.376 2.408 26.448 ;
     RECT  0.084 26.448 2.408 26.472 ;
     RECT  0.06 26.472 2.408 26.544 ;
     RECT  0.084 26.544 2.408 26.568 ;
     RECT  0.06 26.568 2.408 26.64 ;
     RECT  0.084 26.64 2.408 26.664 ;
     RECT  0.06 26.664 2.408 26.736 ;
     RECT  0.084 26.736 2.408 26.76 ;
     RECT  0.06 26.76 2.408 26.832 ;
     RECT  0.084 26.832 2.408 26.856 ;
     RECT  0.06 26.856 2.408 26.928 ;
     RECT  0.084 26.928 2.408 26.952 ;
     RECT  0.06 26.952 2.408 27.024 ;
     RECT  0.084 27.024 2.408 27.048 ;
     RECT  0.06 27.048 2.408 27.12 ;
     RECT  0.084 27.12 2.408 27.144 ;
     RECT  0.06 27.144 2.408 27.216 ;
     RECT  0.084 27.216 2.408 27.24 ;
     RECT  0.06 27.24 2.408 27.312 ;
     RECT  0.084 27.312 2.408 27.336 ;
     RECT  0.06 27.336 2.408 27.408 ;
     RECT  0.084 27.408 2.408 27.432 ;
     RECT  0.06 27.432 2.408 27.504 ;
     RECT  0.084 27.504 2.408 27.528 ;
     RECT  0.06 27.528 2.408 27.6 ;
     RECT  0.084 27.6 2.408 27.624 ;
     RECT  0.06 27.624 2.408 27.696 ;
     RECT  0.084 27.696 2.408 27.72 ;
     RECT  0.06 27.72 2.408 27.792 ;
     RECT  0.084 27.792 2.408 27.816 ;
     RECT  0.06 27.816 2.408 27.888 ;
     RECT  0.084 27.888 2.408 27.912 ;
     RECT  0.06 27.912 2.408 27.984 ;
     RECT  0.084 27.984 2.408 28.008 ;
     RECT  0.06 28.008 2.408 28.08 ;
     RECT  0.084 28.08 2.408 28.104 ;
     RECT  0.06 28.104 2.408 28.176 ;
     RECT  0.084 28.176 2.408 28.2 ;
     RECT  0.06 28.2 2.408 28.272 ;
     RECT  0.084 28.272 2.408 28.296 ;
     RECT  0.06 28.296 2.408 28.368 ;
     RECT  0.084 28.368 2.408 28.392 ;
     RECT  0.06 28.392 2.408 28.464 ;
     RECT  0.084 28.464 2.408 28.488 ;
     RECT  0.06 28.488 2.408 28.56 ;
     RECT  0.084 28.56 2.408 28.584 ;
     RECT  0.06 28.584 2.408 28.656 ;
     RECT  0.084 28.656 2.408 28.68 ;
     RECT  0.06 28.68 2.408 28.752 ;
     RECT  0.084 28.752 2.408 28.776 ;
     RECT  0.06 28.776 2.408 28.848 ;
     RECT  0.084 28.848 2.408 28.872 ;
     RECT  0.06 28.872 2.408 28.944 ;
     RECT  0.084 28.944 2.408 28.968 ;
     RECT  0.06 28.968 2.408 29.04 ;
     RECT  0.084 29.04 2.408 29.064 ;
     RECT  0.06 29.064 2.408 29.136 ;
     RECT  0.084 29.136 2.408 29.16 ;
     RECT  0.06 29.16 2.408 29.232 ;
     RECT  0.084 29.232 2.408 29.256 ;
     RECT  0.06 29.256 2.408 29.328 ;
     RECT  0.084 29.328 2.408 29.352 ;
     RECT  0.06 29.352 2.408 29.424 ;
     RECT  0.084 29.424 2.408 29.448 ;
     RECT  0.06 29.448 2.408 29.52 ;
     RECT  0.084 29.52 2.408 29.544 ;
     RECT  0.06 29.544 2.408 29.616 ;
     RECT  0.084 29.616 2.408 29.64 ;
     RECT  0.06 29.64 2.408 29.712 ;
     RECT  0.084 29.712 2.408 29.736 ;
     RECT  0.06 29.736 2.408 29.808 ;
     RECT  0.084 29.808 2.408 29.832 ;
     RECT  0.06 29.832 2.408 29.904 ;
     RECT  0.084 29.904 2.408 29.928 ;
     RECT  0.06 29.928 2.408 30 ;
     RECT  0.084 30 2.408 30.024 ;
     RECT  0.06 30.024 2.408 30.096 ;
     RECT  0.084 30.096 2.408 30.12 ;
     RECT  0.06 30.12 2.408 30.192 ;
     RECT  0.084 30.192 2.408 30.216 ;
     RECT  0.06 30.216 2.408 30.288 ;
     RECT  0.084 30.288 2.408 30.312 ;
     RECT  0.06 30.312 2.408 30.384 ;
     RECT  0.084 30.384 2.408 30.408 ;
     RECT  0.06 30.408 2.408 30.48 ;
     RECT  0.084 30.48 2.408 30.504 ;
     RECT  0.06 30.504 2.408 30.576 ;
     RECT  0.084 30.576 2.408 30.6 ;
     RECT  0.06 30.6 2.408 30.672 ;
     RECT  0.084 30.672 2.408 30.696 ;
     RECT  0.06 30.696 2.408 30.768 ;
     RECT  0.084 30.768 2.408 30.792 ;
     RECT  0.06 30.792 2.408 30.864 ;
     RECT  0.084 30.864 2.408 30.888 ;
     RECT  0.06 30.888 2.408 30.96 ;
     RECT  0.084 30.96 2.408 30.984 ;
     RECT  0.06 30.984 2.408 31.056 ;
     RECT  0.084 31.056 2.408 31.08 ;
     RECT  0.06 31.08 2.408 31.152 ;
     RECT  0.084 31.152 2.408 31.176 ;
     RECT  0.06 31.176 2.408 31.248 ;
     RECT  0.084 31.248 2.408 31.272 ;
     RECT  0.06 31.272 2.408 31.344 ;
     RECT  0.084 31.344 2.408 31.368 ;
     RECT  0.06 31.368 2.408 31.44 ;
     RECT  0.084 31.44 2.408 31.464 ;
     RECT  0.06 31.464 2.408 31.536 ;
     RECT  0.084 31.536 2.408 31.56 ;
     RECT  0.06 31.56 2.408 31.632 ;
     RECT  0.084 31.632 2.408 31.656 ;
     RECT  0.06 31.656 2.408 31.728 ;
     RECT  0.084 31.728 2.408 31.752 ;
     RECT  0.06 31.752 2.408 31.824 ;
     RECT  0.084 31.824 2.408 31.848 ;
     RECT  0.06 31.848 2.408 31.92 ;
     RECT  0.084 31.92 2.408 31.944 ;
     RECT  0.06 31.944 2.408 32.016 ;
     RECT  0.084 32.016 2.408 32.04 ;
     RECT  0.06 32.04 2.408 32.112 ;
     RECT  0.084 32.112 2.408 32.136 ;
     RECT  0.06 32.136 2.408 32.208 ;
     RECT  0.084 32.208 2.408 32.232 ;
     RECT  0.06 32.232 2.408 32.304 ;
     RECT  0.084 32.304 2.408 32.328 ;
     RECT  0.06 32.328 2.408 32.4 ;
     RECT  0.084 32.4 2.408 32.424 ;
     RECT  0.06 32.424 2.408 32.496 ;
     RECT  0.084 32.496 2.408 32.52 ;
     RECT  0.06 32.52 2.408 32.592 ;
     RECT  0.084 32.592 2.408 32.616 ;
     RECT  0.06 32.616 2.408 32.688 ;
     RECT  0.084 32.688 2.408 32.712 ;
     RECT  0.06 32.712 2.408 32.784 ;
     RECT  0.084 32.784 2.408 32.808 ;
     RECT  0.06 32.808 2.408 32.88 ;
     RECT  0.084 32.88 2.408 32.904 ;
     RECT  0.06 32.904 2.408 32.976 ;
     RECT  0.084 32.976 2.408 33 ;
     RECT  0.06 33 2.408 33.072 ;
     RECT  0.084 33.072 2.408 33.096 ;
     RECT  0.06 33.096 2.408 33.168 ;
     RECT  0.084 33.168 2.408 33.192 ;
     RECT  0.06 33.192 2.408 33.264 ;
     RECT  0.084 33.264 2.408 33.288 ;
     RECT  0.06 33.288 2.408 33.36 ;
     RECT  0.084 33.36 2.408 33.384 ;
     RECT  0.06 33.384 2.408 33.456 ;
     RECT  0.084 33.456 2.408 33.48 ;
     RECT  0.06 33.48 2.408 33.552 ;
     RECT  0.084 33.552 2.408 33.576 ;
     RECT  0.06 33.576 2.408 33.648 ;
     RECT  0.084 33.648 2.408 33.672 ;
     RECT  0.06 33.672 2.408 33.744 ;
     RECT  0.084 33.744 2.408 33.768 ;
     RECT  0.06 33.768 2.408 33.84 ;
     RECT  0.084 33.84 2.408 33.864 ;
     RECT  0.06 33.864 2.408 33.936 ;
     RECT  0.084 33.936 2.408 33.96 ;
     RECT  0.06 33.96 2.408 34.032 ;
     RECT  0.084 34.032 2.408 34.056 ;
     RECT  0.06 34.056 2.408 34.128 ;
     RECT  0.084 34.128 2.408 34.152 ;
     RECT  0.06 34.152 2.408 34.224 ;
     RECT  0.084 34.224 2.408 34.248 ;
     RECT  0.06 34.248 2.408 34.32 ;
     RECT  0.084 34.32 2.408 34.344 ;
     RECT  0.06 34.344 2.408 34.416 ;
     RECT  0.084 34.416 2.408 34.44 ;
     RECT  0.06 34.44 2.408 34.512 ;
     RECT  0.084 34.512 2.408 34.536 ;
     RECT  0.06 34.536 2.408 34.608 ;
     RECT  0.084 34.608 2.408 34.632 ;
     RECT  0.06 34.632 2.408 34.704 ;
     RECT  0.084 34.704 2.408 34.728 ;
     RECT  0.06 34.728 2.408 34.8 ;
     RECT  0.084 34.8 2.408 34.824 ;
     RECT  0.06 34.824 2.408 34.896 ;
     RECT  0.084 34.896 2.408 34.92 ;
     RECT  0.06 34.92 2.408 34.992 ;
     RECT  0.084 34.992 2.408 35.016 ;
     RECT  0.06 35.016 2.408 35.088 ;
     RECT  0.084 35.088 2.408 35.112 ;
     RECT  0.06 35.112 2.408 35.184 ;
     RECT  0.084 35.184 2.408 35.208 ;
     RECT  0.06 35.208 2.408 35.28 ;
     RECT  0.084 35.28 2.408 35.304 ;
     RECT  0.06 35.304 2.408 35.376 ;
     RECT  0.084 35.376 2.408 35.4 ;
     RECT  0.06 35.4 2.408 35.472 ;
     RECT  0.084 35.472 2.408 35.496 ;
     RECT  0.06 35.496 2.408 35.568 ;
     RECT  0.084 35.568 2.408 35.592 ;
     RECT  0.06 35.592 2.408 35.664 ;
     RECT  0.084 35.664 2.408 35.688 ;
     RECT  0.06 35.688 2.408 35.76 ;
     RECT  0.084 35.76 2.408 35.784 ;
     RECT  0.06 35.784 2.408 35.856 ;
     RECT  0.084 35.856 2.408 35.88 ;
     RECT  0.06 35.88 2.408 35.952 ;
     RECT  0.084 35.952 2.408 35.976 ;
     RECT  0.06 35.976 2.408 36.048 ;
     RECT  0.084 36.048 2.408 36.072 ;
     RECT  0.06 36.072 2.408 36.144 ;
     RECT  0.084 36.144 2.408 36.168 ;
     RECT  0.06 36.168 2.408 36.24 ;
     RECT  0.084 36.24 2.408 36.264 ;
     RECT  2.401 37.872 2.408 37.896 ;
     RECT  2.408 2.148 2.512 41.052 ;
     RECT  2.512 2.418 2.704 40.782 ;
     RECT  2.704 10.8 2.873 36.264 ;
     RECT  2.873 13.584 2.909 36.264 ;
     RECT  2.873 10.8 2.915 12.36 ;
     RECT  2.915 10.8 3.269 11.256 ;
     RECT  2.909 13.584 3.557 34.776 ;
     RECT  2.909 36.048 3.805 36.264 ;
     RECT  2.704 37.872 3.805 37.896 ;
     RECT  2.915 12.24 3.925 12.36 ;
     RECT  3.805 36.048 3.949 37.896 ;
     RECT  3.949 36.048 3.953 38.088 ;
     RECT  3.557 33.888 3.985 34.776 ;
     RECT  3.953 36.048 3.985 36.216 ;
     RECT  3.557 13.584 4.097 32.52 ;
     RECT  3.925 12.24 4.165 12.552 ;
     RECT  4.097 13.584 4.165 32.472 ;
     RECT  3.985 33.888 4.205 36.216 ;
     RECT  4.205 35.328 4.313 36.216 ;
     RECT  4.205 33.888 4.525 34.056 ;
     RECT  3.269 10.8 4.604 10.872 ;
     RECT  4.604 10.752 4.645 10.872 ;
     RECT  4.165 12.24 4.645 32.472 ;
     RECT  3.953 37.536 4.889 38.088 ;
     RECT  4.645 10.752 5.029 32.472 ;
     RECT  4.889 37.536 5.137 37.896 ;
     RECT  4.525 33.504 5.173 34.056 ;
     RECT  4.313 35.328 5.173 35.688 ;
     RECT  5.173 33.504 5.281 35.688 ;
     RECT  5.137 37.056 5.281 37.896 ;
     RECT  5.281 33.504 5.315 35.928 ;
     RECT  5.029 10.32 5.461 32.472 ;
     RECT  5.315 33.504 5.461 34.248 ;
     RECT  5.281 37.008 5.497 37.896 ;
     RECT  5.315 35.28 5.677 35.928 ;
     RECT  5.497 36.912 5.677 37.896 ;
     RECT  5.677 35.28 5.897 37.896 ;
     RECT  5.461 10.32 6.361 34.248 ;
     RECT  5.897 35.28 6.361 36.792 ;
     RECT  6.361 10.32 7.045 36.792 ;
     RECT  7.045 9.504 7.381 36.792 ;
     RECT  6.949 6.672 7.808 6.696 ;
     RECT  6.517 8.448 7.808 8.472 ;
     RECT  7.381 9.504 7.808 36.888 ;
     RECT  5.897 37.872 7.808 37.896 ;
     RECT  7.808 2.148 7.912 41.052 ;
     RECT  7.912 2.418 8.104 40.782 ;
     RECT  8.104 9.504 8.201 15 ;
     RECT  8.201 9.504 8.243 14.808 ;
     RECT  8.104 15.984 8.273 32.28 ;
     RECT  8.243 11.952 8.345 14.808 ;
     RECT  8.104 36.48 8.461 36.888 ;
     RECT  8.273 15.984 8.483 31.992 ;
     RECT  8.483 15.984 8.525 27.96 ;
     RECT  8.525 25.536 8.533 27.96 ;
     RECT  8.533 25.536 8.597 27.912 ;
     RECT  8.483 29.088 8.597 31.992 ;
     RECT  8.104 33.648 8.705 35.496 ;
     RECT  8.525 15.984 8.749 23.976 ;
     RECT  8.597 25.536 8.771 27.768 ;
     RECT  8.771 26.112 8.813 27.768 ;
     RECT  8.597 29.616 8.813 31.992 ;
     RECT  8.813 26.112 8.849 27.336 ;
     RECT  8.345 11.952 8.957 14.232 ;
     RECT  8.749 15.984 9.021 23.832 ;
     RECT  9.021 15.984 9.101 18.456 ;
     RECT  9.021 19.872 9.101 23.832 ;
     RECT  8.957 13.344 9.107 14.232 ;
     RECT  8.813 30.672 9.155 31.992 ;
     RECT  8.104 6.672 9.169 7.368 ;
     RECT  8.849 26.736 9.173 27.336 ;
     RECT  9.169 6.24 9.245 7.368 ;
     RECT  9.101 19.872 9.245 22.824 ;
     RECT  8.104 8.352 9.277 8.472 ;
     RECT  8.243 9.504 9.277 10.968 ;
     RECT  9.277 8.352 9.313 10.968 ;
     RECT  9.313 7.968 9.353 10.968 ;
     RECT  8.957 11.952 9.353 12.264 ;
     RECT  9.155 30.816 9.389 31.992 ;
     RECT  9.101 16.032 9.533 18.456 ;
     RECT  8.705 33.648 9.637 34.536 ;
     RECT  9.107 13.344 9.641 14.136 ;
     RECT  9.389 30.864 9.673 31.992 ;
     RECT  9.641 13.344 9.713 14.04 ;
     RECT  9.565 0.144 9.745 0.168 ;
     RECT  9.713 13.584 9.749 14.04 ;
     RECT  9.673 30.864 9.853 32.184 ;
     RECT  9.637 33.552 9.853 34.536 ;
     RECT  9.745 0.144 9.917 0.6 ;
     RECT  8.461 36.528 9.961 36.888 ;
     RECT  9.353 11.952 9.971 11.976 ;
     RECT  9.313 5.088 9.997 5.112 ;
     RECT  9.853 30.864 9.997 34.536 ;
     RECT  9.533 16.032 10.001 17.592 ;
     RECT  9.997 4.56 10.105 5.112 ;
     RECT  9.353 9.12 10.109 10.968 ;
     RECT  9.961 35.952 10.141 36.888 ;
     RECT  9.917 0.096 10.163 0.6 ;
     RECT  9.997 30.864 10.177 34.92 ;
     RECT  9.353 7.968 10.213 7.992 ;
     RECT  9.245 20.496 10.241 22.824 ;
     RECT  9.817 24.048 10.241 24.696 ;
     RECT  10.213 2.208 10.309 2.232 ;
     RECT  10.177 30.864 10.321 34.968 ;
     RECT  10.141 35.952 10.321 37.032 ;
     RECT  9.173 26.784 10.429 27.336 ;
     RECT  10.321 42.192 10.429 42.216 ;
     RECT  10.241 20.496 10.469 24.696 ;
     RECT  10.469 20.496 10.477 24.072 ;
     RECT  10.321 30.864 10.541 37.032 ;
     RECT  10.309 1.728 10.556 2.232 ;
     RECT  10.541 30.864 10.573 34.488 ;
     RECT  10.429 41.616 10.609 42.216 ;
     RECT  10.163 0.096 10.681 0.552 ;
     RECT  10.213 7.92 10.681 7.992 ;
     RECT  10.609 41.616 10.681 43.08 ;
     RECT  10.477 24.048 10.685 24.072 ;
     RECT  10.573 30.672 10.685 34.488 ;
     RECT  10.105 4.416 10.717 5.112 ;
     RECT  9.245 6.24 10.717 6.84 ;
     RECT  9.749 14.016 10.721 14.04 ;
     RECT  10.429 26.4 10.721 27.336 ;
     RECT  10.541 35.568 10.789 37.032 ;
     RECT  10.789 35.568 10.969 37.848 ;
     RECT  10.001 16.848 10.973 17.592 ;
     RECT  10.717 4.416 11.005 6.84 ;
     RECT  10.753 25.968 11.005 25.992 ;
     RECT  10.069 39.36 11.005 39.384 ;
     RECT  10.681 41.04 11.027 43.08 ;
     RECT  10.969 35.568 11.113 38.136 ;
     RECT  11.005 39.264 11.117 39.384 ;
     RECT  11.005 3.648 11.121 6.84 ;
     RECT  10.681 7.92 11.121 8.04 ;
     RECT  11.027 41.04 11.123 42.216 ;
     RECT  11.123 41.04 11.173 41.64 ;
     RECT  10.165 19.248 11.185 19.32 ;
     RECT  10.477 20.496 11.185 22.824 ;
     RECT  11.113 35.568 11.185 38.184 ;
     RECT  11.185 19.248 11.225 22.824 ;
     RECT  10.556 1.728 11.257 2.28 ;
     RECT  11.121 3.648 11.257 8.04 ;
     RECT  10.721 27.264 11.257 27.336 ;
     RECT  11.257 1.728 11.293 8.04 ;
     RECT  10.685 30.672 11.293 31.32 ;
     RECT  11.185 35.568 11.293 38.232 ;
     RECT  11.117 39.264 11.293 39.288 ;
     RECT  10.109 9.216 11.333 10.968 ;
     RECT  11.257 27.264 11.401 28.152 ;
     RECT  11.333 9.216 11.411 10.872 ;
     RECT  11.173 40.464 11.411 41.64 ;
     RECT  11.293 30.192 11.441 31.32 ;
     RECT  11.225 21.216 11.477 22.824 ;
     RECT  11.293 1.68 11.581 8.04 ;
     RECT  11.293 35.568 11.699 39.288 ;
     RECT  11.005 25.632 11.833 25.992 ;
     RECT  11.401 27.264 11.941 28.392 ;
     RECT  11.411 9.216 11.945 10.632 ;
     RECT  10.681 0.048 11.977 0.552 ;
     RECT  11.833 25.584 11.977 25.992 ;
     RECT  11.699 35.568 11.977 39.24 ;
     RECT  11.411 40.464 12.083 41.112 ;
     RECT  10.685 32.496 12.133 34.488 ;
     RECT  11.977 35.472 12.133 39.24 ;
     RECT  11.477 21.936 12.157 22.824 ;
     RECT  11.441 30.672 12.157 31.32 ;
     RECT  12.133 32.496 12.157 39.24 ;
     RECT  11.225 19.248 12.301 19.608 ;
     RECT  11.977 25.488 12.332 25.992 ;
     RECT  12.332 25.488 12.373 26.28 ;
     RECT  11.941 27.264 12.373 28.488 ;
     RECT  12.301 18.432 12.409 19.608 ;
     RECT  12.373 25.2 12.469 26.28 ;
     RECT  12.373 27.264 12.469 28.536 ;
     RECT  12.469 25.2 12.476 28.536 ;
     RECT  11.581 1.68 12.481 8.136 ;
     RECT  11.945 9.216 12.481 9.336 ;
     RECT  12.476 25.104 12.517 28.536 ;
     RECT  11.977 0.048 12.553 0.6 ;
     RECT  12.481 1.68 12.553 9.336 ;
     RECT  12.524 29.616 12.589 29.64 ;
     RECT  12.157 30.672 12.589 39.24 ;
     RECT  12.157 21.936 12.661 23.064 ;
     RECT  12.517 24.384 12.661 28.536 ;
     RECT  12.589 29.616 12.697 39.24 ;
     RECT  12.661 21.936 12.709 28.536 ;
     RECT  10.973 16.848 12.769 17.4 ;
     RECT  12.409 18.432 12.769 19.848 ;
     RECT  12.769 16.848 12.805 19.848 ;
     RECT  12.709 21.504 12.877 28.536 ;
     RECT  12.697 29.616 12.901 39.336 ;
     RECT  12.083 40.464 12.901 40.536 ;
     RECT  12.805 16.848 12.949 20.136 ;
     RECT  12.877 21.168 12.949 28.536 ;
     RECT  12.553 0.048 12.989 9.336 ;
     RECT  12.901 29.616 13.057 40.536 ;
     RECT  13.057 29.568 13.093 40.536 ;
     RECT  13.093 29.568 13.165 40.584 ;
     RECT  12.989 2.148 13.208 9.336 ;
     RECT  11.945 10.608 13.208 10.632 ;
     RECT  12.949 16.848 13.208 28.536 ;
     RECT  13.165 29.568 13.208 41.208 ;
     RECT  13.208 2.148 13.312 41.208 ;
     RECT  13.312 2.418 13.331 41.208 ;
     RECT  13.189 42.816 13.381 42.84 ;
     RECT  13.381 42.816 13.429 42.936 ;
     RECT  13.331 2.418 13.504 41.16 ;
     RECT  12.989 0.048 13.523 1.128 ;
     RECT  13.504 26.064 13.529 33.288 ;
     RECT  13.529 26.064 13.619 32.328 ;
     RECT  13.504 35.328 13.637 41.16 ;
     RECT  13.619 32.304 13.709 32.328 ;
     RECT  13.523 0.048 13.781 0.552 ;
     RECT  13.637 35.328 13.781 40.488 ;
     RECT  13.429 42.144 13.861 43.032 ;
     RECT  13.504 2.418 13.889 9.336 ;
     RECT  13.619 26.064 13.961 31.176 ;
     RECT  13.861 42.144 14.099 43.08 ;
     RECT  13.781 35.376 14.249 40.488 ;
     RECT  14.099 42.144 14.285 42.168 ;
     RECT  13.504 10.608 14.321 10.632 ;
     RECT  13.889 2.418 14.341 8.952 ;
     RECT  13.504 16.656 14.485 24.984 ;
     RECT  13.961 26.064 14.485 29.544 ;
     RECT  13.781 0.096 14.533 0.552 ;
     RECT  14.341 1.728 14.533 8.952 ;
     RECT  14.485 13.68 14.609 13.704 ;
     RECT  14.533 0.096 14.645 8.952 ;
     RECT  14.485 16.656 14.741 29.544 ;
     RECT  14.249 40.464 14.821 40.488 ;
     RECT  14.741 10.512 14.825 10.536 ;
     RECT  14.741 15.984 14.825 29.544 ;
     RECT  14.821 40.464 14.857 40.728 ;
     RECT  14.249 35.376 14.861 39.336 ;
     RECT  14.857 40.464 14.994 41.064 ;
     RECT  14.645 1.728 15.005 8.952 ;
     RECT  14.825 16.512 15.149 29.544 ;
     RECT  14.994 40.464 15.155 41.016 ;
     RECT  14.645 0.096 15.257 0.552 ;
     RECT  15.005 2.88 15.329 8.952 ;
     RECT  15.155 40.464 15.329 40.728 ;
     RECT  15.257 0.096 15.436 0.216 ;
     RECT  15.329 3.504 15.437 8.952 ;
     RECT  15.149 29.328 15.437 29.544 ;
     RECT  15.253 43.056 15.443 43.08 ;
     RECT  13.961 30.528 15.577 31.176 ;
     RECT  15.289 32.784 15.577 32.808 ;
     RECT  14.861 35.376 15.589 38.712 ;
     RECT  15.149 16.512 15.661 28.056 ;
     RECT  15.329 40.464 15.685 40.632 ;
     RECT  15.661 16.512 15.923 27.672 ;
     RECT  15.005 1.728 16.045 1.8 ;
     RECT  15.577 30.528 16.049 32.808 ;
     RECT  16.049 32.496 16.117 32.808 ;
     RECT  16.045 1.728 16.21 1.848 ;
     RECT  15.589 35.328 16.265 38.712 ;
     RECT  16.21 1.728 16.309 1.896 ;
     RECT  16.117 32.496 16.333 33.24 ;
     RECT  15.685 39.888 16.357 40.632 ;
     RECT  15.437 3.504 16.369 7.992 ;
     RECT  15.437 29.328 16.405 29.352 ;
     RECT  16.049 30.528 16.405 31.032 ;
     RECT  16.369 2.88 16.409 7.992 ;
     RECT  16.309 1.728 16.417 1.848 ;
     RECT  16.357 39.888 16.453 40.728 ;
     RECT  16.333 32.496 16.595 33.816 ;
     RECT  16.595 32.496 16.625 33.24 ;
     RECT  16.265 35.424 16.693 38.712 ;
     RECT  16.453 39.888 16.693 41.016 ;
     RECT  16.405 29.328 16.913 31.032 ;
     RECT  15.923 16.512 17.017 18.456 ;
     RECT  15.923 19.536 17.017 27.672 ;
     RECT  16.417 1.728 17.021 1.8 ;
     RECT  16.913 30.816 17.053 31.032 ;
     RECT  16.625 32.496 17.057 33.096 ;
     RECT  17.053 30.816 17.125 31.128 ;
     RECT  17.057 32.496 17.125 32.52 ;
     RECT  16.913 29.328 17.233 29.784 ;
     RECT  16.693 35.424 17.237 41.016 ;
     RECT  17.017 16.512 17.273 27.672 ;
     RECT  17.233 28.944 17.377 29.784 ;
     RECT  17.273 21.648 17.413 27.672 ;
     RECT  17.377 28.848 17.413 29.784 ;
     RECT  17.021 1.728 17.705 1.752 ;
     RECT  16.409 2.88 18.025 7.464 ;
     RECT  17.413 21.648 18.241 29.784 ;
     RECT  17.125 30.816 18.241 32.52 ;
     RECT  17.521 13.824 18.421 14.76 ;
     RECT  17.273 16.512 18.457 20.664 ;
     RECT  18.025 2.784 18.608 7.464 ;
     RECT  18.421 12.864 18.608 14.76 ;
     RECT  18.457 16.32 18.608 20.664 ;
     RECT  18.241 21.648 18.608 32.52 ;
     RECT  17.237 35.424 18.608 40.968 ;
     RECT  18.608 2.148 18.712 41.052 ;
     RECT  18.712 2.418 18.904 40.782 ;
     RECT  15.436 0.048 18.965 0.216 ;
     RECT  18.904 35.76 19.001 36.12 ;
     RECT  19.001 35.76 19.073 35.88 ;
     RECT  18.904 37.104 19.109 40.344 ;
     RECT  18.904 2.496 19.187 7.464 ;
     RECT  18.904 11.424 19.217 11.448 ;
     RECT  18.965 0.048 19.469 0.168 ;
     RECT  19.187 2.496 19.469 6.648 ;
     RECT  19.073 35.808 19.469 35.88 ;
     RECT  18.904 12.768 19.541 13.944 ;
     RECT  18.904 15.696 19.541 32.52 ;
     RECT  19.109 37.2 19.577 40.344 ;
     RECT  19.577 37.2 19.649 40.104 ;
     RECT  19.469 0.048 19.793 0.12 ;
     RECT  19.469 2.496 19.829 3.672 ;
     RECT  19.829 2.496 19.897 3.624 ;
     RECT  19.649 37.2 19.937 38.856 ;
     RECT  19.897 2.304 20.009 3.624 ;
     RECT  19.649 40.08 20.009 40.104 ;
     RECT  20.009 2.784 20.045 3.624 ;
     RECT  19.469 35.808 20.189 35.832 ;
     RECT  19.793 0.096 20.225 0.12 ;
     RECT  18.904 33.888 20.245 33.912 ;
     RECT  19.541 15.696 20.297 31.944 ;
     RECT  20.245 33.072 20.581 33.912 ;
     RECT  20.297 15.84 20.585 31.944 ;
     RECT  20.581 33.024 20.645 33.912 ;
     RECT  20.585 19.296 20.653 31.944 ;
     RECT  19.937 37.2 20.689 37.992 ;
     RECT  20.653 19.296 20.905 31.992 ;
     RECT  20.645 33.024 20.905 34.248 ;
     RECT  20.905 19.296 21.059 34.248 ;
     RECT  21.059 19.392 21.068 34.248 ;
     RECT  19.541 12.768 21.121 13.848 ;
     RECT  21.068 19.392 21.155 34.344 ;
     RECT  20.585 15.84 21.305 18.216 ;
     RECT  21.121 12.768 21.377 14.664 ;
     RECT  21.085 35.664 21.553 35.688 ;
     RECT  20.689 37.056 21.553 37.992 ;
     RECT  21.155 19.392 21.593 33.576 ;
     RECT  21.305 15.984 21.701 18.216 ;
     RECT  21.593 26.208 21.701 33.576 ;
     RECT  21.553 35.664 21.769 37.992 ;
     RECT  21.377 12.768 21.779 13.704 ;
     RECT  21.593 19.392 22.021 25.128 ;
     RECT  21.701 15.984 22.133 17.208 ;
     RECT  21.701 18.192 22.133 18.216 ;
     RECT  22.021 19.296 22.169 25.128 ;
     RECT  22.169 24.432 22.259 25.128 ;
     RECT  21.769 35.664 22.46 38.808 ;
     RECT  22.169 19.296 22.489 23.448 ;
     RECT  22.46 35.664 22.547 39.768 ;
     RECT  22.259 24.624 22.601 25.128 ;
     RECT  21.701 26.784 22.633 33.576 ;
     RECT  22.489 18.432 22.637 23.448 ;
     RECT  22.547 35.664 22.705 39.048 ;
     RECT  22.705 34.8 22.781 39.048 ;
     RECT  20.045 3.552 22.813 3.576 ;
     RECT  22.133 15.984 22.813 16.92 ;
     RECT  22.781 34.8 22.817 39 ;
     RECT  22.813 3.552 22.853 3.672 ;
     RECT  22.813 15.264 22.961 16.92 ;
     RECT  22.601 24.624 22.961 24.648 ;
     RECT  22.633 26.784 22.993 33.624 ;
     RECT  22.961 16.512 23.033 16.92 ;
     RECT  22.993 26.64 23.101 33.624 ;
     RECT  23.173 40.032 23.425 40.056 ;
     RECT  22.633 43.152 23.749 43.176 ;
     RECT  22.637 18.432 23.857 23.4 ;
     RECT  23.425 40.032 23.965 40.872 ;
     RECT  23.749 42.192 23.965 43.176 ;
     RECT  22.853 3.648 24.008 3.672 ;
     RECT  19.469 4.656 24.008 6.648 ;
     RECT  21.779 12.768 24.008 12.792 ;
     RECT  22.961 15.264 24.008 15.288 ;
     RECT  23.033 16.512 24.008 16.872 ;
     RECT  23.857 18.432 24.008 23.928 ;
     RECT  23.101 26.544 24.008 33.624 ;
     RECT  22.817 34.896 24.008 39 ;
     RECT  23.965 40.032 24.008 43.176 ;
     RECT  24.008 2.148 24.112 43.176 ;
     RECT  24.112 2.418 24.275 43.176 ;
     RECT  24.275 2.418 24.304 41.16 ;
     RECT  24.304 40.128 24.371 41.16 ;
     RECT  24.304 15.552 24.419 24.264 ;
     RECT  24.419 16.512 24.563 24.264 ;
     RECT  24.371 40.128 24.563 41.016 ;
     RECT  24.563 21.936 24.689 24.264 ;
     RECT  24.563 16.512 24.797 18.072 ;
     RECT  24.304 26.592 24.803 39 ;
     RECT  24.304 12.768 24.947 12.792 ;
     RECT  24.304 4.656 24.977 6.648 ;
     RECT  24.803 26.592 25.013 34.056 ;
     RECT  24.563 40.56 25.043 41.016 ;
     RECT  24.797 16.992 25.091 18.072 ;
     RECT  25.013 34.032 25.091 34.056 ;
     RECT  24.977 4.752 25.157 6.648 ;
     RECT  24.563 19.296 25.157 20.424 ;
     RECT  25.157 4.752 25.193 5.016 ;
     RECT  25.043 40.848 25.193 41.016 ;
     RECT  24.304 3.648 25.229 3.672 ;
     RECT  24.803 35.136 25.229 39 ;
     RECT  24.275 42.192 25.229 43.176 ;
     RECT  25.091 17.136 25.265 18.072 ;
     RECT  25.013 26.592 25.301 32.76 ;
     RECT  25.193 40.944 25.331 41.016 ;
     RECT  24.304 25.488 25.333 25.56 ;
     RECT  25.301 26.592 25.333 32.232 ;
     RECT  24.689 22.704 25.373 24.264 ;
     RECT  25.157 6.048 25.379 6.648 ;
     RECT  25.193 4.752 25.445 4.776 ;
     RECT  25.379 6.624 25.475 6.648 ;
     RECT  25.333 25.488 25.475 32.232 ;
     RECT  25.265 17.424 25.516 18.072 ;
     RECT  25.516 17.52 25.549 18.072 ;
     RECT  25.549 17.52 25.589 18.216 ;
     RECT  25.589 17.616 25.597 18.216 ;
     RECT  25.597 17.664 25.633 18.216 ;
     RECT  25.229 42.192 25.669 43.08 ;
     RECT  25.229 36.336 25.724 39 ;
     RECT  25.475 25.488 25.733 28.872 ;
     RECT  25.157 19.344 25.801 20.424 ;
     RECT  25.373 22.704 25.801 23.928 ;
     RECT  25.633 17.664 25.805 17.88 ;
     RECT  25.733 27.456 25.805 28.872 ;
     RECT  25.801 22.608 25.841 23.928 ;
     RECT  25.475 29.856 25.877 32.232 ;
     RECT  25.801 19.344 25.945 20.76 ;
     RECT  25.841 22.608 25.949 23.688 ;
     RECT  25.331 40.992 25.957 41.016 ;
     RECT  25.669 42.144 25.957 43.08 ;
     RECT  25.229 35.136 26.053 35.16 ;
     RECT  25.945 19.344 26.129 20.952 ;
     RECT  25.957 40.992 26.129 43.08 ;
     RECT  26.129 19.344 26.237 20.76 ;
     RECT  25.733 25.488 26.237 25.848 ;
     RECT  26.129 42.144 26.381 43.08 ;
     RECT  25.949 22.608 26.417 22.632 ;
     RECT  26.129 40.992 26.437 41.016 ;
     RECT  25.877 30.912 26.633 32.232 ;
     RECT  25.724 36.336 26.737 39.384 ;
     RECT  26.633 31.104 26.741 32.232 ;
     RECT  26.053 34.752 26.741 35.16 ;
     RECT  26.737 36.336 26.777 39.768 ;
     RECT  26.777 36.72 26.849 39.768 ;
     RECT  26.485 33.456 26.881 33.48 ;
     RECT  26.437 40.896 26.917 41.016 ;
     RECT  26.237 19.728 26.921 19.992 ;
     RECT  26.849 36.72 26.957 39.624 ;
     RECT  26.741 31.104 27.029 31.848 ;
     RECT  26.741 34.752 27.029 34.776 ;
     RECT  26.381 43.008 27.101 43.08 ;
     RECT  27.101 43.056 27.173 43.08 ;
     RECT  25.949 23.664 27.205 23.688 ;
     RECT  25.877 29.856 27.241 29.88 ;
     RECT  25.805 27.456 27.277 28.2 ;
     RECT  26.921 19.776 27.281 19.992 ;
     RECT  27.241 29.616 27.317 29.88 ;
     RECT  26.881 33.456 27.389 33.576 ;
     RECT  27.277 27.36 27.457 28.2 ;
     RECT  27.205 23.664 27.493 24.216 ;
     RECT  27.493 23.664 27.539 24.744 ;
     RECT  27.457 27.36 27.541 28.536 ;
     RECT  27.389 33.456 27.605 33.48 ;
     RECT  27.061 22.56 27.637 22.584 ;
     RECT  27.539 24.48 27.637 24.744 ;
     RECT  27.637 22.56 27.683 23.4 ;
     RECT  27.683 22.848 27.724 23.4 ;
     RECT  26.917 26.208 27.74 26.232 ;
     RECT  27.541 27.36 27.74 28.2 ;
     RECT  27.74 26.208 27.785 28.2 ;
     RECT  27.317 29.616 27.827 29.64 ;
     RECT  27.637 24.48 27.857 24.936 ;
     RECT  27.785 26.208 27.857 27.912 ;
     RECT  27.029 31.104 27.971 31.224 ;
     RECT  27.724 22.848 28.037 22.872 ;
     RECT  27.857 26.208 28.037 27.72 ;
     RECT  25.805 17.856 28.165 17.88 ;
     RECT  27.281 19.776 28.217 19.944 ;
     RECT  27.971 31.2 28.217 31.224 ;
     RECT  28.165 17.856 28.253 18.792 ;
     RECT  26.957 37.584 28.357 39.624 ;
     RECT  28.037 26.208 28.361 26.568 ;
     RECT  27.857 24.48 28.397 24.744 ;
     RECT  28.357 36.816 28.753 39.768 ;
     RECT  26.917 40.848 28.753 41.016 ;
     RECT  28.693 21.84 28.825 21.864 ;
     RECT  28.361 26.544 29.149 26.568 ;
     RECT  29.149 26.544 29.329 26.712 ;
     RECT  28.037 27.696 29.329 27.72 ;
     RECT  28.253 17.856 29.408 17.88 ;
     RECT  28.357 20.352 29.408 20.376 ;
     RECT  28.825 21.504 29.408 21.864 ;
     RECT  29.257 22.848 29.408 22.872 ;
     RECT  28.397 24.48 29.408 24.504 ;
     RECT  29.329 26.544 29.408 27.72 ;
     RECT  29.257 29.04 29.408 29.064 ;
     RECT  28.753 36.816 29.408 41.016 ;
     RECT  29.408 2.148 29.512 41.052 ;
     RECT  29.512 2.418 29.704 41.052 ;
     RECT  29.704 36.816 29.945 39.24 ;
     RECT  29.704 26.544 30.161 27.72 ;
     RECT  29.945 36.816 30.161 39.096 ;
     RECT  30.085 42.144 30.229 42.168 ;
     RECT  30.161 26.832 30.233 27.72 ;
     RECT  29.704 20.352 30.275 21.528 ;
     RECT  30.229 41.616 30.625 42.168 ;
     RECT  30.275 20.544 30.809 21.528 ;
     RECT  30.733 32.544 30.845 32.568 ;
     RECT  30.913 30.816 30.985 30.84 ;
     RECT  30.161 36.816 30.985 38.712 ;
     RECT  30.625 41.616 30.995 43.08 ;
     RECT  30.995 41.616 31.013 41.688 ;
     RECT  30.985 30.192 31.057 30.84 ;
     RECT  31.013 41.568 31.097 41.688 ;
     RECT  30.995 42.768 31.213 43.08 ;
     RECT  29.704 40.32 31.273 40.344 ;
     RECT  31.097 41.616 31.283 41.688 ;
     RECT  31.213 42.768 31.379 42.792 ;
     RECT  29.704 34.656 31.381 34.68 ;
     RECT  31.381 34.656 31.388 35.352 ;
     RECT  30.985 36.624 31.388 38.712 ;
     RECT  31.388 34.656 31.475 38.712 ;
     RECT  31.453 25.056 31.477 25.08 ;
     RECT  31.475 35.328 31.58 38.712 ;
     RECT  31.273 39.888 31.58 40.344 ;
     RECT  29.704 23.952 31.601 23.976 ;
     RECT  31.057 29.616 31.621 30.84 ;
     RECT  30.233 27.12 31.667 27.72 ;
     RECT  31.477 25.056 31.669 25.848 ;
     RECT  31.621 29.04 31.708 30.84 ;
     RECT  31.58 35.328 31.709 40.344 ;
     RECT  31.669 24.72 31.781 25.848 ;
     RECT  30.809 20.544 31.817 20.568 ;
     RECT  31.283 41.616 31.859 41.64 ;
     RECT  31.417 31.92 31.889 32.472 ;
     RECT  31.889 31.92 31.961 31.944 ;
     RECT  31.709 36.624 31.985 40.344 ;
     RECT  31.781 24.72 32.177 25.56 ;
     RECT  31.708 29.04 32.317 30.744 ;
     RECT  32.281 33.024 32.569 33.048 ;
     RECT  32.461 42.192 32.581 42.216 ;
     RECT  31.985 36.624 32.641 40.44 ;
     RECT  31.709 35.328 32.677 35.592 ;
     RECT  32.641 36.624 32.677 41.016 ;
     RECT  32.581 42.192 32.723 43.08 ;
     RECT  32.569 33.024 32.732 33.624 ;
     RECT  32.317 28.176 32.753 30.744 ;
     RECT  32.677 35.328 32.773 41.016 ;
     RECT  31.667 27.12 32.785 27.144 ;
     RECT  32.753 28.176 32.785 30.264 ;
     RECT  32.732 33.024 32.789 33.768 ;
     RECT  32.785 27.12 32.861 30.264 ;
     RECT  32.723 42.24 32.861 43.08 ;
     RECT  32.789 33.6 32.929 33.768 ;
     RECT  32.773 34.896 32.929 41.016 ;
     RECT  32.861 42.24 33.011 42.264 ;
     RECT  32.713 31.776 33.109 31.8 ;
     RECT  32.929 33.6 33.148 41.016 ;
     RECT  32.861 27.744 33.221 30.264 ;
     RECT  33.148 33.6 33.365 40.968 ;
     RECT  32.533 21.36 33.452 21.384 ;
     RECT  29.704 17.856 33.539 17.88 ;
     RECT  33.452 20.784 33.539 21.384 ;
     RECT  32.177 25.536 33.644 25.56 ;
     RECT  33.644 25.536 33.731 26.376 ;
     RECT  33.221 28.176 33.793 30.264 ;
     RECT  33.109 31.68 33.793 31.8 ;
     RECT  33.365 33.6 33.865 40.056 ;
     RECT  33.793 28.176 34.009 31.8 ;
     RECT  34.009 28.176 34.045 31.944 ;
     RECT  34.045 28.176 34.081 32.232 ;
     RECT  33.865 33.264 34.081 40.056 ;
     RECT  33.731 25.536 34.165 25.56 ;
     RECT  34.165 24.672 34.225 25.56 ;
     RECT  33.865 22.512 34.477 22.536 ;
     RECT  33.539 21.36 34.808 21.384 ;
     RECT  34.477 22.464 34.808 22.536 ;
     RECT  34.225 24.624 34.808 25.56 ;
     RECT  34.081 28.176 34.808 40.056 ;
     RECT  34.808 2.148 34.912 41.052 ;
     RECT  34.912 2.418 35.104 40.782 ;
     RECT  35.104 30.432 35.881 40.782 ;
     RECT  35.881 30.432 36.493 41.256 ;
     RECT  36.493 29.808 36.713 41.256 ;
     RECT  36.713 30.432 36.745 41.256 ;
     RECT  36.745 30.432 37.681 41.928 ;
     RECT  37.681 30.096 38.689 41.928 ;
     RECT  38.689 30.048 39.589 41.928 ;
     RECT  39.589 29.616 40.208 41.928 ;
     RECT  40.208 2.148 40.312 41.928 ;
     RECT  40.312 2.418 40.504 41.928 ;
     RECT  40.504 29.136 41.857 41.928 ;
     RECT  41.857 29.136 43.116 29.16 ;
     RECT  41.857 29.16 43.164 29.232 ;
     RECT  41.857 29.232 43.116 29.256 ;
     RECT  41.857 29.256 43.164 29.328 ;
     RECT  41.857 29.328 43.116 29.352 ;
     RECT  41.857 29.352 43.164 29.424 ;
     RECT  41.857 29.424 43.116 29.448 ;
     RECT  41.857 29.448 43.164 29.52 ;
     RECT  41.857 29.52 43.116 29.544 ;
     RECT  41.857 29.544 43.164 29.616 ;
     RECT  41.857 29.616 43.116 29.64 ;
     RECT  41.857 29.64 43.164 29.712 ;
     RECT  41.857 29.712 43.116 29.736 ;
     RECT  41.857 29.736 43.164 29.808 ;
     RECT  41.857 29.808 43.116 29.832 ;
     RECT  41.857 29.832 43.164 29.904 ;
     RECT  41.857 29.904 43.116 29.928 ;
     RECT  41.857 29.928 43.164 30 ;
     RECT  41.857 30 43.116 30.024 ;
     RECT  41.857 30.024 43.164 30.096 ;
     RECT  41.857 30.096 43.116 30.12 ;
     RECT  41.857 30.12 43.164 30.192 ;
     RECT  41.857 30.192 43.116 30.216 ;
     RECT  41.857 30.216 43.164 30.288 ;
     RECT  41.857 30.288 43.116 30.312 ;
     RECT  41.857 30.312 43.164 30.384 ;
     RECT  41.857 30.384 43.116 30.408 ;
     RECT  41.857 30.408 43.164 30.48 ;
     RECT  41.857 30.48 43.116 30.504 ;
     RECT  41.857 30.504 43.164 30.576 ;
     RECT  41.857 30.576 43.116 30.6 ;
     RECT  41.857 30.6 43.164 30.672 ;
     RECT  41.857 30.672 43.116 30.696 ;
     RECT  41.857 30.696 43.164 30.768 ;
     RECT  41.857 30.768 43.116 30.792 ;
     RECT  41.857 30.792 43.164 30.864 ;
     RECT  41.857 30.864 43.116 30.888 ;
     RECT  41.857 30.888 43.164 30.96 ;
     RECT  41.857 30.96 43.116 30.984 ;
     RECT  41.857 30.984 43.164 31.056 ;
     RECT  41.857 31.056 43.116 31.08 ;
     RECT  41.857 31.08 43.164 31.152 ;
     RECT  41.857 31.152 43.116 31.176 ;
     RECT  41.857 31.176 43.164 31.248 ;
     RECT  41.857 31.248 43.116 31.272 ;
     RECT  41.857 31.272 43.164 31.344 ;
     RECT  41.857 31.344 43.116 31.368 ;
     RECT  41.857 31.368 43.164 31.44 ;
     RECT  41.857 31.44 43.116 31.464 ;
     RECT  41.857 31.464 43.164 31.536 ;
     RECT  41.857 31.536 43.116 31.56 ;
     RECT  41.857 31.56 43.164 31.632 ;
     RECT  41.857 31.632 43.116 31.656 ;
     RECT  41.857 31.656 43.164 31.728 ;
     RECT  41.857 31.728 43.116 31.752 ;
     RECT  41.857 31.752 43.164 31.824 ;
     RECT  41.857 31.824 43.116 31.848 ;
     RECT  41.857 31.848 43.164 31.92 ;
     RECT  41.857 31.92 43.116 31.944 ;
     RECT  41.857 31.944 43.164 32.016 ;
     RECT  41.857 32.016 43.116 32.04 ;
     RECT  41.857 32.04 43.164 32.112 ;
     RECT  41.857 32.112 43.116 32.136 ;
     RECT  41.857 32.136 43.164 32.208 ;
     RECT  41.857 32.208 43.116 32.232 ;
     RECT  41.857 32.232 43.164 32.304 ;
     RECT  41.857 32.304 43.116 32.328 ;
     RECT  41.857 32.328 43.164 32.4 ;
     RECT  41.857 32.4 43.116 32.424 ;
     RECT  41.857 32.424 43.164 32.496 ;
     RECT  41.857 32.496 43.116 32.52 ;
     RECT  41.857 32.52 43.164 32.592 ;
     RECT  41.857 32.592 43.116 32.616 ;
     RECT  41.857 32.616 43.164 32.688 ;
     RECT  41.857 32.688 43.116 32.712 ;
     RECT  41.857 32.712 43.164 32.784 ;
     RECT  41.857 32.784 43.116 32.808 ;
     RECT  41.857 32.808 43.164 32.88 ;
     RECT  41.857 32.88 43.116 32.904 ;
     RECT  41.857 32.904 43.164 32.976 ;
     RECT  41.857 32.976 43.116 33 ;
     RECT  41.857 33 43.164 33.072 ;
     RECT  41.857 33.072 43.116 33.096 ;
     RECT  41.857 33.096 43.164 33.168 ;
     RECT  41.857 33.168 43.116 33.192 ;
     RECT  41.857 33.192 43.164 33.264 ;
     RECT  41.857 33.264 43.116 33.288 ;
     RECT  41.857 33.288 43.164 33.36 ;
     RECT  41.857 33.36 43.116 33.384 ;
     RECT  41.857 33.384 43.164 33.456 ;
     RECT  41.857 33.456 43.116 33.48 ;
     RECT  41.857 33.48 43.164 33.552 ;
     RECT  41.857 33.552 43.116 33.576 ;
     RECT  41.857 33.576 43.164 33.648 ;
     RECT  41.857 33.648 43.116 33.672 ;
     RECT  41.857 33.672 43.164 33.744 ;
     RECT  41.857 33.744 43.116 33.768 ;
     RECT  41.857 33.768 43.164 33.84 ;
     RECT  41.857 33.84 43.116 33.864 ;
     RECT  41.857 33.864 43.164 33.936 ;
     RECT  41.857 33.936 43.116 33.96 ;
     RECT  41.857 33.96 43.164 34.032 ;
     RECT  41.857 34.032 43.116 34.056 ;
     RECT  41.857 34.056 43.164 34.128 ;
     RECT  41.857 34.128 43.116 34.152 ;
     RECT  41.857 34.152 43.164 34.224 ;
     RECT  41.857 34.224 43.116 34.248 ;
     RECT  41.857 34.248 43.164 34.32 ;
     RECT  41.857 34.32 43.116 34.344 ;
     RECT  41.857 34.344 43.164 34.416 ;
     RECT  41.857 34.416 43.116 34.44 ;
     RECT  41.857 34.44 43.164 35.28 ;
     RECT  41.857 35.28 43.116 35.304 ;
     RECT  41.857 35.304 43.164 35.376 ;
     RECT  41.857 35.376 43.116 35.4 ;
     RECT  41.857 35.4 43.164 35.472 ;
     RECT  41.857 35.472 43.116 35.496 ;
     RECT  41.857 35.496 43.164 35.568 ;
     RECT  41.857 35.568 43.116 35.592 ;
     RECT  41.857 35.592 43.164 35.664 ;
     RECT  41.857 35.664 43.116 35.688 ;
     RECT  41.857 35.688 43.164 35.76 ;
     RECT  41.857 35.76 43.116 35.784 ;
     RECT  41.857 35.784 43.164 35.856 ;
     RECT  41.857 35.856 43.116 35.88 ;
     RECT  41.857 35.88 43.164 35.952 ;
     RECT  41.857 35.952 43.116 35.976 ;
     RECT  41.857 35.976 43.164 36.048 ;
     RECT  41.857 36.048 43.116 36.072 ;
     RECT  41.857 36.072 43.164 36.144 ;
     RECT  41.857 36.144 43.116 36.168 ;
     RECT  41.857 36.168 43.164 36.24 ;
     RECT  41.857 36.24 43.116 36.264 ;
     RECT  41.857 36.264 43.164 36.336 ;
     RECT  41.857 36.336 43.116 36.36 ;
     RECT  41.857 36.36 43.164 36.432 ;
     RECT  41.857 36.432 43.116 36.456 ;
     RECT  41.857 36.456 43.164 36.528 ;
     RECT  41.857 36.528 43.116 36.552 ;
     RECT  41.857 36.552 43.164 36.624 ;
     RECT  41.857 36.624 43.116 36.648 ;
     RECT  41.857 36.648 43.164 36.72 ;
     RECT  41.857 36.72 43.116 36.744 ;
     RECT  41.857 36.744 43.164 36.816 ;
     RECT  41.857 36.816 43.116 36.84 ;
     RECT  41.857 36.84 43.164 36.912 ;
     RECT  41.857 36.912 43.116 36.936 ;
     RECT  41.857 36.936 43.164 37.008 ;
     RECT  41.857 37.008 43.116 37.032 ;
     RECT  41.857 37.032 43.164 37.104 ;
     RECT  41.857 37.104 43.116 37.128 ;
     RECT  41.857 37.128 43.164 37.2 ;
     RECT  41.857 37.2 43.116 37.224 ;
     RECT  41.857 37.224 43.164 37.296 ;
     RECT  41.857 37.296 43.116 37.32 ;
     RECT  41.857 37.32 43.164 37.392 ;
     RECT  41.857 37.392 43.116 37.416 ;
     RECT  41.857 37.416 43.164 37.488 ;
     RECT  41.857 37.488 43.116 37.512 ;
     RECT  41.857 37.512 43.164 37.584 ;
     RECT  41.857 37.584 43.116 37.608 ;
     RECT  41.857 37.608 43.164 37.68 ;
     RECT  41.857 37.68 43.116 37.704 ;
     RECT  41.857 37.704 43.164 37.776 ;
     RECT  41.857 37.776 43.116 37.8 ;
     RECT  41.857 37.8 43.164 37.872 ;
     RECT  41.857 37.872 43.116 37.896 ;
     RECT  41.857 37.896 43.164 37.968 ;
     RECT  41.857 37.968 43.116 37.992 ;
     RECT  41.857 37.992 43.164 38.064 ;
     RECT  41.857 38.064 43.116 38.088 ;
     RECT  41.857 38.088 43.164 38.16 ;
     RECT  41.857 38.16 43.116 38.184 ;
     RECT  41.857 38.184 43.164 38.256 ;
     RECT  41.857 38.256 43.116 38.28 ;
     RECT  41.857 38.28 43.164 39.12 ;
     RECT  41.857 39.12 43.116 39.144 ;
     RECT  41.857 39.144 43.164 39.216 ;
     RECT  41.857 39.216 43.116 39.24 ;
     RECT  41.857 39.24 43.164 39.312 ;
     RECT  41.857 39.312 43.116 39.336 ;
     RECT  41.857 39.336 43.164 39.408 ;
     RECT  41.857 39.408 43.116 39.432 ;
     RECT  41.857 39.432 43.164 39.504 ;
     RECT  41.857 39.504 43.116 39.528 ;
     RECT  41.857 39.528 43.164 39.6 ;
     RECT  41.857 39.6 43.116 39.624 ;
     RECT  41.857 39.624 43.164 39.696 ;
     RECT  41.857 39.696 43.116 39.72 ;
     RECT  41.857 39.72 43.164 39.792 ;
     RECT  41.857 39.792 43.116 39.816 ;
     RECT  41.857 39.816 43.164 39.888 ;
     RECT  41.857 39.888 43.116 39.912 ;
     RECT  41.857 39.912 43.164 39.984 ;
     RECT  41.857 39.984 43.116 40.008 ;
     RECT  41.857 40.008 43.164 40.08 ;
     RECT  41.857 40.08 43.116 40.104 ;
     RECT  41.857 40.104 43.164 40.176 ;
     RECT  41.857 40.176 43.116 40.2 ;
     RECT  41.857 40.2 43.164 40.272 ;
     RECT  41.857 40.272 43.116 40.296 ;
     RECT  41.857 40.296 43.164 40.368 ;
     RECT  41.857 40.368 43.116 40.392 ;
     RECT  41.857 40.392 43.164 40.464 ;
     RECT  41.857 40.464 43.116 40.488 ;
     RECT  41.857 40.488 43.164 40.56 ;
     RECT  41.857 40.56 43.116 40.584 ;
     RECT  41.857 40.584 43.164 40.656 ;
     RECT  41.857 40.656 43.116 40.68 ;
     RECT  41.857 40.68 43.164 40.752 ;
     RECT  41.857 40.752 43.116 40.776 ;
     RECT  41.857 40.776 43.164 40.848 ;
     RECT  41.857 40.848 43.116 40.872 ;
     RECT  41.857 40.872 43.164 40.944 ;
     RECT  41.857 40.944 43.116 40.968 ;
     RECT  41.857 40.968 43.164 41.04 ;
     RECT  41.857 41.04 43.116 41.064 ;
     RECT  41.857 41.064 43.164 41.136 ;
     RECT  41.857 41.136 43.116 41.16 ;
     RECT  41.857 41.16 43.164 41.232 ;
     RECT  41.857 41.232 43.116 41.256 ;
     RECT  41.857 41.256 43.164 41.328 ;
     RECT  41.857 41.328 43.116 41.352 ;
     RECT  41.857 41.352 43.164 41.424 ;
     RECT  41.857 41.424 43.116 41.448 ;
     RECT  41.857 41.448 43.164 41.52 ;
     RECT  41.857 41.52 43.116 41.544 ;
     RECT  41.857 41.544 43.164 41.616 ;
     RECT  41.857 41.616 43.116 41.64 ;
     RECT  41.857 41.64 43.164 41.712 ;
     RECT  41.857 41.712 43.116 41.736 ;
     RECT  41.857 41.736 43.164 41.808 ;
     RECT  41.857 41.808 43.116 41.832 ;
     RECT  41.857 41.832 43.164 41.904 ;
     RECT  41.857 41.904 43.116 41.928 ;
     RECT  41.857 41.928 43.164 42 ;
     RECT  41.857 42 43.116 42.024 ;
     RECT  41.857 42.024 43.164 42.096 ;
     RECT  41.857 42.096 43.116 42.12 ;
     RECT  43.164 34.896 43.193 34.92 ;
    LAYER M5 ;
     RECT  9.96 0.016 10.032 0.084 ;
     RECT  10.056 0.016 10.128 0.084 ;
     RECT  10.152 0.016 10.224 0.084 ;
     RECT  10.248 0.016 10.32 0.084 ;
     RECT  10.344 0.016 10.416 0.084 ;
     RECT  10.44 0.016 10.512 0.084 ;
     RECT  10.536 0.016 10.608 0.084 ;
     RECT  10.632 0.016 10.704 0.084 ;
     RECT  10.728 0.016 10.8 0.084 ;
     RECT  10.824 0.016 10.896 0.084 ;
     RECT  10.92 0.016 10.992 0.084 ;
     RECT  11.016 0.016 11.088 0.084 ;
     RECT  11.112 0.016 11.184 0.084 ;
     RECT  11.208 0.016 11.28 0.084 ;
     RECT  11.304 0.016 11.376 0.084 ;
     RECT  11.4 0.016 11.472 0.084 ;
     RECT  11.496 0.016 11.568 0.084 ;
     RECT  11.592 0.016 11.664 0.084 ;
     RECT  11.688 0.016 11.76 0.084 ;
     RECT  11.784 0.016 11.856 0.084 ;
     RECT  11.88 0.016 11.952 0.084 ;
     RECT  11.976 0.016 12.048 0.084 ;
     RECT  12.072 0.016 12.144 0.084 ;
     RECT  12.168 0.016 12.24 0.084 ;
     RECT  12.264 0.016 12.336 0.084 ;
     RECT  12.36 0.016 12.432 0.084 ;
     RECT  12.456 0.016 12.528 0.084 ;
     RECT  12.552 0.016 12.624 0.084 ;
     RECT  12.648 0.016 12.72 0.084 ;
     RECT  12.744 0.016 12.816 0.084 ;
     RECT  12.84 0.016 12.912 0.084 ;
     RECT  12.936 0.016 13.008 0.084 ;
     RECT  13.032 0.016 13.104 0.084 ;
     RECT  13.128 0.016 13.2 0.084 ;
     RECT  13.224 0.016 13.296 0.084 ;
     RECT  13.32 0.016 13.392 0.084 ;
     RECT  13.416 0.016 13.488 0.084 ;
     RECT  13.512 0.016 13.584 0.084 ;
     RECT  13.608 0.016 13.68 0.084 ;
     RECT  13.704 0.016 13.776 0.084 ;
     RECT  13.8 0.016 13.872 0.084 ;
     RECT  13.896 0.016 13.968 0.084 ;
     RECT  13.992 0.016 14.064 0.084 ;
     RECT  14.088 0.016 14.16 0.084 ;
     RECT  14.184 0.016 14.256 0.084 ;
     RECT  14.28 0.016 14.352 0.084 ;
     RECT  14.376 0.016 14.448 0.084 ;
     RECT  14.472 0.016 14.544 0.084 ;
     RECT  14.568 0.016 14.64 0.084 ;
     RECT  14.664 0.016 14.736 0.084 ;
     RECT  14.76 0.016 14.832 0.084 ;
     RECT  14.856 0.016 14.928 0.084 ;
     RECT  14.952 0.016 15.024 0.084 ;
     RECT  15.048 0.016 15.12 0.084 ;
     RECT  15.144 0.016 15.216 0.084 ;
     RECT  15.24 0.016 15.312 0.084 ;
     RECT  15.336 0.016 15.408 0.084 ;
     RECT  15.432 0.016 15.504 0.084 ;
     RECT  15.528 0.016 15.6 0.084 ;
     RECT  15.624 0.016 15.696 0.084 ;
     RECT  15.72 0.016 15.792 0.084 ;
     RECT  15.816 0.016 15.888 0.084 ;
     RECT  15.912 0.016 15.984 0.084 ;
     RECT  16.008 0.016 16.08 0.084 ;
     RECT  16.104 0.016 16.176 0.084 ;
     RECT  16.2 0.016 16.272 0.084 ;
     RECT  16.296 0.016 16.368 0.084 ;
     RECT  9.936 0.084 16.392 0.131 ;
     RECT  10.032 0.131 16.392 1.811 ;
     RECT  16.176 1.811 16.392 1.859 ;
     RECT  16.272 1.859 16.296 1.907 ;
     RECT  2.4 2.137 2.52 2.151 ;
     RECT  7.8 2.137 7.92 2.151 ;
     RECT  18.6 2.137 18.72 2.151 ;
     RECT  24 2.137 24.12 2.151 ;
     RECT  29.4 2.137 29.52 2.151 ;
     RECT  34.8 2.137 34.92 2.151 ;
     RECT  40.2 2.137 40.32 2.151 ;
     RECT  10.032 1.811 14.616 3.301 ;
     RECT  10.032 3.301 15.192 4.451 ;
     RECT  10.032 4.451 14.616 4.595 ;
     RECT  11.904 4.595 14.616 5.411 ;
     RECT  10.032 4.595 10.824 5.747 ;
     RECT  11.952 5.411 14.616 5.747 ;
     RECT  18.6 2.151 18.912 6.181 ;
     RECT  10.032 5.747 10.248 6.323 ;
     RECT  13.008 5.747 14.616 6.323 ;
     RECT  25.344 6.037 25.368 6.613 ;
     RECT  7.8 2.151 8.112 6.661 ;
     RECT  6.96 6.661 8.112 6.805 ;
     RECT  11.952 5.747 11.976 6.899 ;
     RECT  13.008 6.323 14.376 6.947 ;
     RECT  6.96 6.805 8.808 7.333 ;
     RECT  18 6.181 18.912 7.429 ;
     RECT  13.056 6.947 14.376 7.475 ;
     RECT  18 7.429 19.176 7.475 ;
     RECT  16.272 6.229 16.296 7.523 ;
     RECT  13.056 7.475 14.232 7.667 ;
     RECT  10.032 6.323 10.056 7.909 ;
     RECT  11.184 6.949 11.208 7.909 ;
     RECT  13.2 7.667 14.232 8.003 ;
     RECT  10.032 7.909 11.208 8.051 ;
     RECT  6.96 7.333 8.856 8.437 ;
     RECT  6.528 8.437 8.856 9.109 ;
     RECT  10.032 8.051 10.248 9.109 ;
     RECT  6.528 9.109 10.248 9.301 ;
     RECT  6.528 9.301 11.064 9.923 ;
     RECT  10.032 9.923 11.064 10.021 ;
     RECT  10.032 10.021 11.4 10.307 ;
     RECT  6.528 9.923 8.904 10.741 ;
     RECT  2.4 2.151 2.712 10.789 ;
     RECT  10.032 10.307 10.248 10.883 ;
     RECT  11.376 10.307 11.4 10.883 ;
     RECT  4.656 10.741 4.68 10.933 ;
     RECT  5.76 10.741 8.904 10.933 ;
     RECT  4.656 10.933 8.904 11.459 ;
     RECT  18.6 7.475 19.176 11.459 ;
     RECT  10.032 10.883 10.056 11.941 ;
     RECT  2.4 10.789 3.528 12.517 ;
     RECT  24 2.151 24.312 12.757 ;
     RECT  25.344 6.613 25.464 12.757 ;
     RECT  18.6 11.459 18.912 12.853 ;
     RECT  0.144 12.805 0.168 12.901 ;
     RECT  0.144 12.901 0.264 13.187 ;
     RECT  14.784 8.821 14.808 13.669 ;
     RECT  4.944 11.459 8.904 14.197 ;
     RECT  9.936 11.941 10.056 14.197 ;
     RECT  0.144 13.187 0.168 14.437 ;
     RECT  2.4 12.517 3.96 14.773 ;
     RECT  4.944 14.197 10.056 14.773 ;
     RECT  0.144 14.437 0.264 14.869 ;
     RECT  0.144 14.869 0.408 14.915 ;
     RECT  18.432 12.853 18.912 15.685 ;
     RECT  18.432 15.685 19.224 15.733 ;
     RECT  2.4 14.773 10.056 16.019 ;
     RECT  14.496 13.669 14.808 16.019 ;
     RECT  21.744 13.333 21.768 16.019 ;
     RECT  0.192 14.915 0.408 16.261 ;
     RECT  2.4 16.019 4.536 16.501 ;
     RECT  18.432 15.733 19.944 17.077 ;
     RECT  21.456 17.029 21.48 17.077 ;
     RECT  18.432 17.077 21.48 17.315 ;
     RECT  0.144 16.261 0.408 17.413 ;
     RECT  0.144 17.413 0.456 17.557 ;
     RECT  15.888 17.557 15.912 17.605 ;
     RECT  24 12.757 25.464 17.605 ;
     RECT  18.432 17.315 19.944 17.651 ;
     RECT  13.2 8.003 13.512 17.989 ;
     RECT  2.304 16.501 4.536 18.037 ;
     RECT  5.616 16.019 10.056 18.037 ;
     RECT  24 17.605 25.56 18.181 ;
     RECT  12.912 17.989 13.512 18.709 ;
     RECT  12.768 18.709 13.512 18.757 ;
     RECT  14.496 16.019 14.52 18.757 ;
     RECT  18.432 17.651 19.368 18.757 ;
     RECT  15.792 17.605 15.912 18.997 ;
     RECT  0.144 17.557 0.552 19.043 ;
     RECT  2.304 18.037 10.056 19.237 ;
     RECT  21.456 17.315 21.48 19.285 ;
     RECT  22.704 18.757 22.728 19.285 ;
     RECT  12.768 18.757 14.52 19.525 ;
     RECT  15.504 18.997 15.912 19.525 ;
     RECT  12.768 19.525 15.912 19.717 ;
     RECT  28.176 18.757 28.2 19.955 ;
     RECT  21.024 19.285 22.728 20.051 ;
     RECT  12.768 19.717 16.584 20.341 ;
     RECT  17.568 18.757 19.368 20.341 ;
     RECT  29.4 2.151 29.712 20.341 ;
     RECT  21.024 20.051 22.056 20.389 ;
     RECT  20.928 20.389 22.056 20.629 ;
     RECT  2.304 19.237 10.44 20.675 ;
     RECT  2.4 20.675 10.44 20.869 ;
     RECT  12.768 20.341 19.368 20.965 ;
     RECT  20.448 20.629 22.056 20.965 ;
     RECT  2.4 20.869 10.776 21.107 ;
     RECT  29.4 20.341 30.264 21.251 ;
     RECT  12.768 20.965 22.056 21.347 ;
     RECT  0.144 19.043 0.504 21.395 ;
     RECT  33.504 17.845 33.528 21.395 ;
     RECT  0.144 21.395 0.36 21.491 ;
     RECT  12.768 21.347 19.656 21.493 ;
     RECT  21.024 21.347 22.056 21.637 ;
     RECT  0.192 21.491 0.36 21.779 ;
     RECT  29.4 21.251 29.712 21.829 ;
     RECT  21.024 21.637 22.104 21.877 ;
     RECT  24 18.181 25.608 22.213 ;
     RECT  0.192 21.779 0.312 22.547 ;
     RECT  2.4 21.107 10.44 22.741 ;
     RECT  0.192 22.547 0.264 23.029 ;
     RECT  12.72 21.493 19.656 23.125 ;
     RECT  0.144 23.029 0.264 23.411 ;
     RECT  2.304 22.741 10.44 23.411 ;
     RECT  23.376 22.213 25.608 23.411 ;
     RECT  12.72 23.125 19.848 23.603 ;
     RECT  2.304 23.411 10.2 23.987 ;
     RECT  12.72 23.603 19.656 23.987 ;
     RECT  0.144 23.411 0.216 24.083 ;
     RECT  27.648 22.549 27.672 24.181 ;
     RECT  12.72 23.987 15.96 24.373 ;
     RECT  28.704 21.829 29.712 24.515 ;
     RECT  34.8 2.151 35.112 24.661 ;
     RECT  21.024 21.877 22.248 24.899 ;
     RECT  12.528 24.373 15.96 24.947 ;
     RECT  27.504 24.181 27.672 24.947 ;
     RECT  21.024 24.899 21.72 25.091 ;
     RECT  17.376 23.987 19.656 25.093 ;
     RECT  21.024 25.091 21.288 25.093 ;
     RECT  12.528 24.947 15.72 25.139 ;
     RECT  12.576 25.139 15.72 25.235 ;
     RECT  0.192 24.083 0.216 25.523 ;
     RECT  17.376 25.093 21.288 25.523 ;
     RECT  2.4 23.987 8.472 25.525 ;
     RECT  9.456 23.987 10.2 25.525 ;
     RECT  34.176 24.661 35.112 25.571 ;
     RECT  12.72 25.235 15.72 25.763 ;
     RECT  31.584 25.045 31.608 25.813 ;
     RECT  31.488 25.813 31.608 25.859 ;
     RECT  17.376 25.523 19.656 26.003 ;
     RECT  24 23.411 25.608 26.243 ;
     RECT  12.72 25.763 15.048 26.245 ;
     RECT  2.4 25.525 10.2 26.387 ;
     RECT  17.376 26.003 19.512 26.531 ;
     RECT  17.568 26.531 19.512 26.579 ;
     RECT  27.504 24.947 27.528 26.725 ;
     RECT  17.616 26.579 19.512 26.819 ;
     RECT  12.384 26.245 15.048 27.205 ;
     RECT  3.744 26.387 10.2 27.251 ;
     RECT  11.376 25.621 11.4 27.299 ;
     RECT  20.784 25.523 21.288 27.395 ;
     RECT  2.4 26.387 2.712 27.445 ;
     RECT  3.744 27.251 9.144 27.445 ;
     RECT  17.616 26.819 19.416 27.539 ;
     RECT  20.784 27.395 20.808 27.587 ;
     RECT  27.504 26.725 27.816 27.685 ;
     RECT  31.488 25.859 31.512 27.685 ;
     RECT  31.488 27.685 31.656 27.731 ;
     RECT  12.384 27.205 15.624 27.781 ;
     RECT  2.4 27.445 9.144 27.971 ;
     RECT  2.4 27.971 2.856 28.067 ;
     RECT  12.336 27.781 15.624 28.067 ;
     RECT  33.696 26.341 33.72 28.165 ;
     RECT  34.8 25.571 35.112 28.165 ;
     RECT  33.696 28.165 35.112 28.211 ;
     RECT  27.504 27.685 27.96 28.547 ;
     RECT  12.336 28.067 15.048 28.835 ;
     RECT  17.616 27.539 19.176 28.933 ;
     RECT  0.144 28.213 0.168 28.979 ;
     RECT  21.024 28.405 21.048 29.075 ;
     RECT  31.632 27.731 31.656 29.075 ;
     RECT  34.032 28.211 35.112 29.123 ;
     RECT  17.472 28.933 19.176 29.267 ;
     RECT  4.224 27.971 9.144 29.413 ;
     RECT  18.432 29.267 19.176 29.605 ;
     RECT  27.792 28.547 27.96 29.651 ;
     RECT  24 26.243 25.56 29.891 ;
     RECT  40.2 2.151 40.512 30.037 ;
     RECT  24 29.891 25.08 30.133 ;
     RECT  2.4 28.067 2.712 30.325 ;
     RECT  3.936 29.413 9.144 30.325 ;
     RECT  0.144 30.373 0.168 30.563 ;
     RECT  2.4 30.325 9.144 30.707 ;
     RECT  2.4 30.707 8.424 30.803 ;
     RECT  18.432 29.605 19.224 30.803 ;
     RECT  12.336 28.835 14.472 30.851 ;
     RECT  31.632 30.181 31.656 30.851 ;
     RECT  12.336 30.851 13.704 30.899 ;
     RECT  18.432 30.803 18.912 30.947 ;
     RECT  15.936 29.317 15.96 30.997 ;
     RECT  15.936 30.997 16.632 31.091 ;
     RECT  27.936 29.651 27.96 31.139 ;
     RECT  2.4 30.803 3.432 31.379 ;
     RECT  5.136 30.803 8.424 31.523 ;
     RECT  23.568 30.133 25.08 31.669 ;
     RECT  34.8 29.123 35.112 31.765 ;
     RECT  5.28 31.523 8.424 32.003 ;
     RECT  12.336 30.899 13.608 32.051 ;
     RECT  0.144 32.053 0.168 32.243 ;
     RECT  12.336 32.051 13.512 32.293 ;
     RECT  34.8 31.765 35.208 32.339 ;
     RECT  23.184 31.669 25.08 32.437 ;
     RECT  15.6 31.861 15.624 32.485 ;
     RECT  16.608 31.091 16.632 32.485 ;
     RECT  40.2 30.037 40.632 32.531 ;
     RECT  10.176 27.251 10.2 32.819 ;
     RECT  6.432 32.003 8.424 33.107 ;
     RECT  15.6 32.485 16.632 33.107 ;
     RECT  20.256 30.997 20.712 33.107 ;
     RECT  2.4 31.379 2.712 33.109 ;
     RECT  22.752 32.437 25.08 33.155 ;
     RECT  20.688 33.107 20.712 33.589 ;
     RECT  2.4 33.109 2.808 33.923 ;
     RECT  23.184 33.155 25.08 34.067 ;
     RECT  12.288 32.293 13.512 34.069 ;
     RECT  0.144 33.829 0.168 34.211 ;
     RECT  5.28 32.003 5.448 34.259 ;
     RECT  7.44 33.107 8.424 34.259 ;
     RECT  20.688 33.589 21.144 34.259 ;
     RECT  21.12 34.259 21.144 34.355 ;
     RECT  34.8 32.339 35.112 34.357 ;
     RECT  5.28 34.259 5.304 34.741 ;
     RECT  31.44 34.645 31.464 34.741 ;
     RECT  5.184 34.741 5.304 34.787 ;
     RECT  32.784 29.029 32.808 34.885 ;
     RECT  32.784 34.885 33.048 34.931 ;
     RECT  12.144 34.069 13.512 35.075 ;
     RECT  6.432 33.107 6.456 35.269 ;
     RECT  5.184 34.787 5.208 35.317 ;
     RECT  13.2 35.075 13.512 35.317 ;
     RECT  34.176 34.357 35.112 35.317 ;
     RECT  15.6 33.107 16.584 35.363 ;
     RECT  31.392 34.741 31.464 35.363 ;
     RECT  34.176 35.317 35.4 35.363 ;
     RECT  23.184 34.067 24.792 35.509 ;
     RECT  23.184 35.509 24.888 35.557 ;
     RECT  22.992 35.557 24.888 35.699 ;
     RECT  15.888 35.363 16.584 35.701 ;
     RECT  15.888 35.701 16.872 35.749 ;
     RECT  18.6 30.947 18.912 35.845 ;
     RECT  6.24 35.269 6.456 35.939 ;
     RECT  12.144 35.075 12.168 35.939 ;
     RECT  31.44 35.363 31.464 35.939 ;
     RECT  4.272 35.317 5.208 35.987 ;
     RECT  34.8 35.363 35.4 36.181 ;
     RECT  34.8 36.181 36.072 36.323 ;
     RECT  6.432 35.939 6.456 36.373 ;
     RECT  7.8 34.259 8.424 36.373 ;
     RECT  22.992 35.699 23.016 36.373 ;
     RECT  24 35.699 24.888 36.421 ;
     RECT  6.432 36.373 8.424 36.515 ;
     RECT  22.848 36.373 23.016 36.515 ;
     RECT  34.8 36.323 35.4 36.515 ;
     RECT  24 36.421 25.608 36.611 ;
     RECT  40.2 32.531 40.512 36.661 ;
     RECT  6.432 36.515 8.112 36.803 ;
     RECT  29.4 24.515 29.712 36.805 ;
     RECT  13.2 35.317 13.608 36.851 ;
     RECT  18.6 35.845 19.368 36.853 ;
     RECT  15.888 35.749 17.16 36.899 ;
     RECT  40.032 36.661 40.512 36.947 ;
     RECT  25.584 36.611 25.608 36.949 ;
     RECT  29.4 36.805 29.88 36.949 ;
     RECT  5.184 35.987 5.208 37.091 ;
     RECT  22.848 36.515 22.872 37.091 ;
     RECT  34.8 36.515 35.208 37.139 ;
     RECT  40.08 36.947 40.512 37.427 ;
     RECT  25.584 36.949 26.376 37.523 ;
     RECT  37.008 37.477 37.032 37.619 ;
     RECT  7.392 36.803 8.112 37.907 ;
     RECT  26.16 37.523 26.376 38.053 ;
     RECT  28.464 36.949 29.88 38.147 ;
     RECT  15.936 36.899 17.16 38.197 ;
     RECT  13.2 36.851 13.512 38.389 ;
     RECT  18.432 36.853 19.368 38.483 ;
     RECT  13.2 38.389 13.656 38.533 ;
     RECT  28.464 38.147 29.712 38.723 ;
     RECT  33.024 34.931 33.048 38.723 ;
     RECT  13.2 38.533 14.088 38.725 ;
     RECT  37.008 38.629 37.032 38.773 ;
     RECT  37.008 38.773 37.56 38.867 ;
     RECT  37.536 38.867 37.56 38.915 ;
     RECT  40.2 37.427 40.512 38.917 ;
     RECT  40.08 38.917 40.512 39.059 ;
     RECT  13.008 38.725 14.088 39.061 ;
     RECT  15.312 38.197 17.16 39.061 ;
     RECT  12.528 39.061 17.16 39.205 ;
     RECT  18.432 38.483 19.032 39.205 ;
     RECT  12.528 39.205 19.032 39.253 ;
     RECT  31.92 39.253 31.944 39.301 ;
     RECT  26.16 38.053 27.048 39.349 ;
     RECT  31.92 39.301 32.712 39.349 ;
     RECT  22.512 38.773 22.536 39.779 ;
     RECT  24 36.611 24.312 40.117 ;
     RECT  11.664 39.253 19.032 40.163 ;
     RECT  11.664 40.163 17.064 40.453 ;
     RECT  24 40.117 24.552 40.549 ;
     RECT  25.776 39.349 27.048 40.549 ;
     RECT  31.632 39.349 32.712 40.933 ;
     RECT  2.4 33.923 2.712 41.049 ;
     RECT  7.8 37.907 8.112 41.049 ;
     RECT  18.6 40.163 18.912 41.049 ;
     RECT  34.8 37.139 35.112 41.049 ;
     RECT  40.2 39.059 40.512 41.049 ;
     RECT  2.4 41.049 2.52 41.063 ;
     RECT  7.8 41.049 7.92 41.063 ;
     RECT  18.6 41.049 18.72 41.063 ;
     RECT  24 40.549 27.048 41.063 ;
     RECT  29.4 38.723 29.712 41.063 ;
     RECT  34.8 41.049 34.92 41.063 ;
     RECT  40.2 41.049 40.32 41.063 ;
     RECT  31.632 40.933 33.192 41.557 ;
     RECT  31.056 41.557 33.192 41.605 ;
     RECT  30.288 41.605 33.192 42.133 ;
     RECT  11.184 40.453 17.064 42.181 ;
     RECT  24.144 41.063 27.048 42.181 ;
     RECT  11.088 42.181 17.064 43.045 ;
     RECT  10.992 43.045 17.064 43.116 ;
     RECT  11.016 43.116 11.088 43.152 ;
     RECT  11.112 43.116 11.184 43.152 ;
     RECT  11.208 43.116 11.28 43.152 ;
     RECT  11.304 43.116 11.376 43.152 ;
     RECT  11.4 43.116 11.472 43.152 ;
     RECT  11.496 43.116 11.568 43.152 ;
     RECT  11.592 43.116 11.664 43.152 ;
     RECT  11.688 43.116 11.76 43.152 ;
     RECT  11.784 43.116 11.856 43.152 ;
     RECT  11.88 43.116 11.952 43.152 ;
     RECT  11.976 43.116 12.048 43.152 ;
     RECT  12.072 43.116 12.144 43.152 ;
     RECT  12.168 43.116 12.24 43.152 ;
     RECT  12.264 43.116 12.336 43.152 ;
     RECT  12.36 43.116 12.432 43.152 ;
     RECT  12.456 43.116 12.528 43.152 ;
     RECT  12.552 43.116 12.624 43.152 ;
     RECT  12.648 43.116 12.72 43.152 ;
     RECT  12.744 43.116 12.816 43.152 ;
     RECT  12.84 43.116 12.912 43.152 ;
     RECT  12.936 43.116 13.008 43.152 ;
     RECT  13.032 43.116 13.104 43.152 ;
     RECT  13.128 43.116 13.2 43.152 ;
     RECT  13.224 43.116 13.296 43.152 ;
     RECT  13.32 43.116 13.392 43.152 ;
     RECT  13.416 43.116 13.488 43.152 ;
     RECT  13.512 43.116 13.584 43.152 ;
     RECT  13.608 43.116 13.68 43.152 ;
     RECT  13.704 43.116 13.776 43.152 ;
     RECT  13.8 43.116 13.872 43.152 ;
     RECT  13.896 43.116 13.968 43.152 ;
     RECT  13.992 43.116 14.448 43.152 ;
     RECT  14.472 43.116 14.544 43.152 ;
     RECT  14.568 43.116 14.64 43.152 ;
     RECT  14.664 43.116 14.736 43.152 ;
     RECT  14.76 43.116 14.832 43.152 ;
     RECT  14.856 43.116 14.928 43.152 ;
     RECT  14.952 43.116 15.024 43.152 ;
     RECT  15.048 43.116 15.12 43.152 ;
     RECT  15.144 43.116 15.216 43.152 ;
     RECT  15.24 43.116 15.312 43.152 ;
     RECT  15.336 43.116 15.408 43.152 ;
     RECT  15.432 43.116 15.504 43.152 ;
     RECT  15.528 43.116 15.6 43.152 ;
     RECT  15.624 43.116 15.696 43.152 ;
     RECT  15.72 43.116 15.792 43.152 ;
     RECT  15.816 43.116 15.888 43.152 ;
     RECT  15.912 43.116 15.984 43.152 ;
     RECT  16.008 43.116 16.08 43.152 ;
     RECT  16.104 43.116 16.176 43.152 ;
     RECT  16.2 43.116 16.272 43.152 ;
     RECT  16.296 43.116 16.368 43.152 ;
     RECT  16.392 43.116 16.464 43.152 ;
     RECT  16.488 43.116 16.56 43.152 ;
     RECT  16.584 43.116 16.656 43.152 ;
     RECT  16.68 43.116 16.752 43.152 ;
     RECT  16.776 43.116 16.848 43.152 ;
     RECT  16.872 43.116 16.944 43.152 ;
     RECT  16.968 43.116 17.04 43.152 ;
     RECT  24.048 42.181 27.048 43.116 ;
     RECT  24.072 43.116 24.144 43.152 ;
     RECT  24.168 43.116 24.24 43.152 ;
     RECT  24.264 43.116 24.336 43.152 ;
     RECT  24.36 43.116 24.432 43.152 ;
     RECT  24.456 43.116 24.528 43.152 ;
     RECT  24.552 43.116 24.624 43.152 ;
     RECT  24.648 43.116 24.72 43.152 ;
     RECT  24.744 43.116 24.816 43.152 ;
     RECT  24.84 43.116 24.912 43.152 ;
     RECT  24.936 43.116 25.008 43.152 ;
     RECT  25.032 43.116 25.104 43.152 ;
     RECT  25.128 43.116 25.2 43.152 ;
     RECT  25.224 43.116 25.296 43.152 ;
     RECT  25.32 43.116 25.392 43.152 ;
     RECT  25.416 43.116 25.488 43.152 ;
     RECT  25.512 43.116 25.584 43.152 ;
     RECT  25.608 43.116 25.68 43.152 ;
     RECT  25.704 43.116 25.776 43.152 ;
     RECT  25.8 43.116 25.872 43.152 ;
     RECT  25.896 43.116 25.968 43.152 ;
     RECT  25.992 43.116 26.064 43.152 ;
     RECT  26.088 43.116 26.16 43.152 ;
     RECT  26.184 43.116 26.256 43.152 ;
     RECT  26.28 43.116 26.352 43.152 ;
     RECT  26.376 43.116 26.448 43.152 ;
     RECT  26.472 43.116 26.544 43.152 ;
     RECT  26.568 43.116 26.64 43.152 ;
     RECT  26.664 43.116 26.736 43.152 ;
     RECT  26.76 43.116 26.832 43.152 ;
     RECT  26.856 43.116 26.928 43.152 ;
     RECT  26.952 43.116 27.024 43.152 ;
     RECT  30.192 42.133 33.192 43.116 ;
     RECT  30.216 43.116 30.288 43.152 ;
     RECT  30.312 43.116 30.384 43.152 ;
     RECT  30.408 43.116 30.48 43.152 ;
     RECT  30.504 43.116 30.576 43.152 ;
     RECT  30.6 43.116 30.672 43.152 ;
     RECT  30.696 43.116 30.768 43.152 ;
     RECT  30.792 43.116 30.864 43.152 ;
     RECT  30.888 43.116 30.96 43.152 ;
     RECT  30.984 43.116 31.056 43.152 ;
     RECT  31.08 43.116 31.152 43.152 ;
     RECT  31.176 43.116 31.248 43.152 ;
     RECT  31.272 43.116 31.344 43.152 ;
     RECT  31.368 43.116 31.44 43.152 ;
     RECT  31.464 43.116 31.536 43.152 ;
     RECT  31.56 43.116 31.632 43.152 ;
     RECT  31.656 43.116 31.728 43.152 ;
     RECT  31.752 43.116 31.824 43.152 ;
     RECT  31.848 43.116 31.92 43.152 ;
     RECT  31.944 43.116 32.016 43.152 ;
     RECT  32.04 43.116 32.112 43.152 ;
     RECT  32.136 43.116 32.208 43.152 ;
     RECT  32.232 43.116 32.304 43.152 ;
     RECT  32.328 43.116 32.4 43.152 ;
     RECT  32.424 43.116 32.496 43.152 ;
     RECT  32.52 43.116 32.592 43.152 ;
     RECT  32.616 43.116 32.688 43.152 ;
     RECT  32.712 43.116 32.784 43.152 ;
     RECT  32.808 43.116 32.88 43.152 ;
     RECT  32.904 43.116 32.976 43.152 ;
     RECT  33 43.116 33.072 43.152 ;
     RECT  33.096 43.116 33.168 43.152 ;
     RECT  14.616 1.811 16.176 1.859 ;
     RECT  14.616 1.859 16.272 1.907 ;
     RECT  14.616 1.907 15.192 3.301 ;
     RECT  10.824 4.595 11.904 5.411 ;
     RECT  10.824 5.411 11.952 5.747 ;
     RECT  10.248 5.747 11.952 6.323 ;
     RECT  11.976 5.747 13.008 6.899 ;
     RECT  24.312 6.037 25.344 12.757 ;
     RECT  10.056 6.323 11.952 6.899 ;
     RECT  8.808 6.805 10.032 7.333 ;
     RECT  10.056 6.899 11.208 6.949 ;
     RECT  10.056 6.949 11.184 7.909 ;
     RECT  8.856 7.333 10.032 9.109 ;
     RECT  14.232 7.475 14.376 8.003 ;
     RECT  13.512 8.003 14.376 8.821 ;
     RECT  10.248 8.051 11.064 9.301 ;
     RECT  13.512 8.821 14.784 13.669 ;
     RECT  8.904 9.923 10.032 11.941 ;
     RECT  10.248 10.307 11.376 10.883 ;
     RECT  4.68 10.741 5.76 10.933 ;
     RECT  3.528 10.789 4.656 11.459 ;
     RECT  3.528 11.459 4.944 12.517 ;
     RECT  8.904 11.941 9.936 14.197 ;
     RECT  3.96 12.517 4.944 14.773 ;
     RECT  0.168 13.187 0.264 14.437 ;
     RECT  13.512 13.669 14.496 18.757 ;
     RECT  0.144 14.915 0.192 16.261 ;
     RECT  4.536 16.019 5.616 18.037 ;
     RECT  19.944 17.029 21.456 17.077 ;
     RECT  19.944 17.315 21.456 17.651 ;
     RECT  14.52 17.557 15.888 17.605 ;
     RECT  14.52 17.605 15.792 18.997 ;
     RECT  33.528 17.845 34.8 21.395 ;
     RECT  21.48 18.757 22.704 19.285 ;
     RECT  22.728 18.757 24 20.051 ;
     RECT  28.2 18.757 29.4 19.955 ;
     RECT  14.52 18.997 15.504 19.525 ;
     RECT  16.584 19.717 17.568 20.341 ;
     RECT  19.368 20.629 20.448 20.965 ;
     RECT  19.656 21.347 21.024 23.125 ;
     RECT  22.248 22.213 23.376 23.411 ;
     RECT  27.672 22.549 28.704 24.515 ;
     RECT  19.848 23.125 21.024 23.603 ;
     RECT  19.656 23.603 21.024 25.093 ;
     RECT  8.472 23.987 9.456 25.525 ;
     RECT  15.96 23.987 17.376 24.947 ;
     RECT  12.528 25.139 12.576 25.235 ;
     RECT  12.528 25.235 12.72 25.621 ;
     RECT  19.656 25.523 20.784 26.003 ;
     RECT  34.176 25.571 34.8 26.341 ;
     RECT  10.2 25.621 11.376 27.299 ;
     RECT  11.4 25.621 12.72 26.245 ;
     RECT  15.048 25.763 15.624 27.205 ;
     RECT  19.512 26.003 20.784 26.819 ;
     RECT  11.4 26.245 12.384 27.299 ;
     RECT  33.72 26.341 34.8 28.165 ;
     RECT  2.712 26.387 3.744 27.445 ;
     RECT  19.416 26.819 20.784 27.539 ;
     RECT  9.144 27.251 10.176 30.707 ;
     RECT  12.336 27.299 12.384 27.781 ;
     RECT  20.808 27.395 21.048 27.587 ;
     RECT  21.024 27.587 21.048 28.405 ;
     RECT  27.96 27.685 29.4 31.139 ;
     RECT  2.856 27.971 4.224 28.067 ;
     RECT  2.712 28.067 4.224 29.413 ;
     RECT  15.048 28.067 15.624 28.835 ;
     RECT  33.696 28.211 34.032 29.029 ;
     RECT  14.472 28.835 15.624 29.317 ;
     RECT  0.144 28.979 0.168 30.373 ;
     RECT  31.656 29.029 32.784 29.075 ;
     RECT  32.808 29.029 34.032 29.123 ;
     RECT  31.632 29.075 32.784 30.181 ;
     RECT  14.472 29.317 15.936 30.851 ;
     RECT  2.712 29.413 3.936 30.325 ;
     RECT  31.656 30.181 32.784 30.851 ;
     RECT  0.144 30.563 0.168 32.053 ;
     RECT  18.912 30.803 19.224 30.997 ;
     RECT  15.6 30.851 15.936 31.091 ;
     RECT  18.912 30.997 20.256 33.107 ;
     RECT  15.6 31.091 16.608 31.861 ;
     RECT  15.624 31.861 16.608 32.485 ;
     RECT  5.448 32.003 6.432 34.259 ;
     RECT  6.456 33.107 7.44 34.259 ;
     RECT  24.792 34.067 24.888 35.509 ;
     RECT  5.304 34.259 6.432 34.787 ;
     RECT  6.456 34.259 7.8 36.373 ;
     RECT  32.808 34.357 34.176 34.885 ;
     RECT  31.464 34.645 32.784 34.931 ;
     RECT  5.208 34.787 6.432 35.269 ;
     RECT  33.048 34.885 34.176 35.363 ;
     RECT  12.168 35.075 13.2 35.939 ;
     RECT  5.208 35.269 6.24 35.939 ;
     RECT  23.016 35.699 24 36.515 ;
     RECT  17.16 35.749 18.6 36.853 ;
     RECT  5.208 35.939 6.432 36.803 ;
     RECT  22.872 36.515 24 37.091 ;
     RECT  24.312 36.611 25.584 37.523 ;
     RECT  17.16 36.853 18.432 39.205 ;
     RECT  15.888 36.899 15.936 38.197 ;
     RECT  40.08 37.427 40.2 38.917 ;
     RECT  37.008 37.619 37.032 38.629 ;
     RECT  27.048 38.053 28.464 38.723 ;
     RECT  14.088 38.533 15.312 39.061 ;
     RECT  22.536 38.773 24 39.779 ;
     RECT  24.312 39.349 25.776 40.117 ;
     RECT  24.552 40.117 25.776 40.549 ;
     RECT  24.048 41.063 24.144 42.181 ;
  END
END ot_qwen_tp8_pv_wide_ctl
END LIBRARY
